VERSION 5.7 ;
  NOWIREEXTENSIONATPIN ON ;
  DIVIDERCHAR "/" ;
  BUSBITCHARS "[]" ;
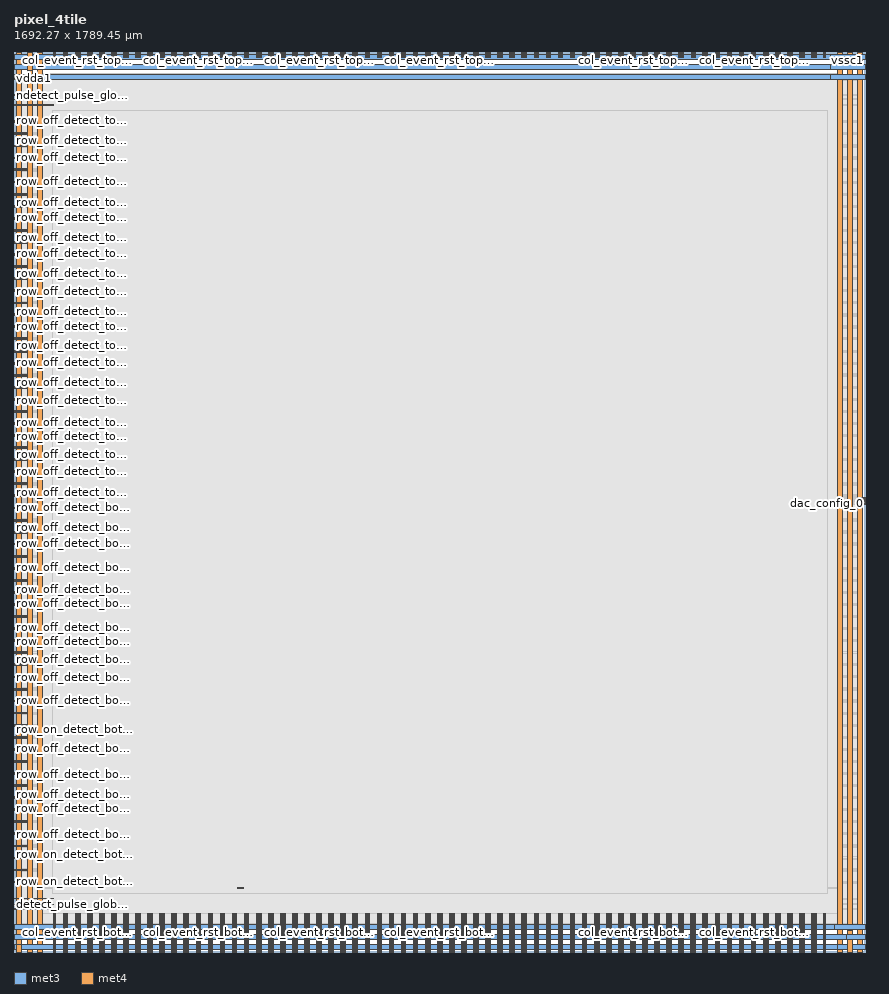
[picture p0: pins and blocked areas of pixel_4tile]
MACRO pixel_4tile
  CLASS BLOCK ;
  FOREIGN pixel_4tile ;
  ORIGIN 75.885 75.665 ;
  SIZE 1692.265 BY 1789.450 ;
  PIN vssa1
    ANTENNADIFFAREA 25319.859375 ;
    PORT
      LAYER met3 ;
        RECT 1547.800 1658.440 1616.380 1668.440 ;
    END
    PORT
      LAYER met3 ;
        RECT -75.885 1658.440 1547.800 1668.440 ;
    END
    PORT
      LAYER met3 ;
        RECT -75.885 -30.000 1555.035 -20.000 ;
    END
    PORT
      LAYER met3 ;
        RECT 1555.035 -30.000 1616.380 -20.000 ;
    END
    PORT
      LAYER met4 ;
        RECT -30.000 -75.665 -20.000 1713.785 ;
    END
    PORT
      LAYER met4 ;
        RECT 1561.380 -75.665 1571.380 1713.785 ;
    END
  END vssa1
  PIN vdda1
    PORT
      LAYER met3 ;
        RECT 1547.800 1678.440 1616.380 1688.440 ;
    END
    PORT
      LAYER met3 ;
        RECT -75.885 1678.440 1547.800 1688.440 ;
    END
    PORT
      LAYER met3 ;
        RECT -75.885 -50.000 1580.160 -40.000 ;
    END
    PORT
      LAYER met3 ;
        RECT 1580.160 -50.000 1616.380 -40.000 ;
    END
    PORT
      LAYER met4 ;
        RECT 1581.380 -33.295 1591.380 1713.785 ;
    END
    PORT
      LAYER met4 ;
        RECT -50.000 1676.075 -40.000 1713.785 ;
    END
    PORT
      LAYER met4 ;
        RECT -50.000 -75.665 -40.000 1676.075 ;
    END
    PORT
      LAYER met4 ;
        RECT 368.795 50.390 380.585 52.050 ;
    END
    PORT
      LAYER met4 ;
        RECT 1581.380 -75.665 1591.380 -33.295 ;
    END
  END vdda1
  PIN vssc1
    ANTENNADIFFAREA 4128.768066 ;
    PORT
      LAYER met3 ;
        RECT 1547.800 1697.955 1616.380 1707.955 ;
    END
    PORT
      LAYER met3 ;
        RECT -75.885 1697.955 1547.800 1707.955 ;
    END
    PORT
      LAYER met3 ;
        RECT -75.885 -70.000 1561.945 -60.000 ;
    END
    PORT
      LAYER met3 ;
        RECT 1561.945 -70.000 1616.380 -60.000 ;
    END
    PORT
      LAYER met4 ;
        RECT -70.000 -60.000 -60.000 1713.785 ;
    END
    PORT
      LAYER met4 ;
        RECT -70.000 -75.665 -60.000 -60.000 ;
    END
    PORT
      LAYER met4 ;
        RECT 1601.380 -75.665 1611.380 1713.785 ;
    END
  END vssc1
  PIN dac_config_2
    ANTENNAGATEAREA 36864.000000 ;
    PORT
      LAYER met3 ;
        RECT 1605.820 826.380 1616.380 827.380 ;
    END
  END dac_config_2
  PIN dac_config_4
    ANTENNAGATEAREA 10321.919922 ;
    PORT
      LAYER met3 ;
        RECT 1605.820 820.260 1616.380 821.260 ;
    END
  END dac_config_4
  PIN dac_config_5
    ANTENNAGATEAREA 10321.919922 ;
    PORT
      LAYER met3 ;
        RECT 1605.820 824.340 1616.380 825.340 ;
    END
  END dac_config_5
  PIN dac_config_3
    ANTENNAGATEAREA 1228.799927 ;
    PORT
      LAYER met3 ;
        RECT 1605.820 822.300 1616.380 823.300 ;
    END
  END dac_config_3
  PIN row_off_detect_top<0>
    ANTENNAGATEAREA 8.064000 ;
    PORT
      LAYER met3 ;
        RECT -75.885 1576.770 -50.260 1577.070 ;
    END
  END row_off_detect_top<0>
  PIN row_off_detect_top<11>
    ANTENNAGATEAREA 8.064000 ;
    PORT
      LAYER met3 ;
        RECT -75.885 1453.690 -50.260 1453.990 ;
    END
  END row_off_detect_top<11>
  PIN row_off_detect_top<25>
    ANTENNAGATEAREA 8.064000 ;
    PORT
      LAYER met3 ;
        RECT -75.885 1285.730 -50.260 1286.030 ;
    END
  END row_off_detect_top<25>
  PIN row_on_detect_top<19>
    ANTENNAGATEAREA 16.128000 ;
    PORT
      LAYER met3 ;
        RECT -75.885 1358.490 -50.260 1358.790 ;
    END
  END row_on_detect_top<19>
  PIN row_on_detect_top<20>
    ANTENNAGATEAREA 16.128000 ;
    PORT
      LAYER met3 ;
        RECT -75.885 1336.050 -50.260 1336.350 ;
    END
  END row_on_detect_top<20>
  PIN row_off_detect_top<12>
    ANTENNAGATEAREA 8.064000 ;
    PORT
      LAYER met3 ;
        RECT -75.885 1432.610 -50.260 1432.910 ;
    END
  END row_off_detect_top<12>
  PIN row_on_detect_top<0>
    ANTENNAGATEAREA 16.128000 ;
    PORT
      LAYER met3 ;
        RECT -75.885 1575.410 -50.260 1575.710 ;
    END
  END row_on_detect_top<0>
  PIN row_on_detect_top<1>
    ANTENNAGATEAREA 16.128000 ;
    PORT
      LAYER met3 ;
        RECT -75.885 1574.730 -50.260 1575.030 ;
    END
  END row_on_detect_top<1>
  PIN row_on_detect_top<2>
    ANTENNAGATEAREA 16.128000 ;
    PORT
      LAYER met3 ;
        RECT -75.885 1551.610 -50.260 1551.910 ;
    END
  END row_on_detect_top<2>
  PIN row_on_detect_top<23>
    ANTENNAGATEAREA 16.128000 ;
    PORT
      LAYER met3 ;
        RECT -75.885 1310.890 -50.260 1311.190 ;
    END
  END row_on_detect_top<23>
  PIN row_off_detect_top<9>
    ANTENNAGATEAREA 8.064000 ;
    PORT
      LAYER met3 ;
        RECT -75.885 1477.490 -50.260 1477.790 ;
    END
  END row_off_detect_top<9>
  PIN row_off_detect_top<10>
    ANTENNAGATEAREA 8.064000 ;
    PORT
      LAYER met3 ;
        RECT -75.885 1456.410 -50.260 1456.710 ;
    END
  END row_off_detect_top<10>
  PIN row_off_detect_top<3>
    ANTENNAGATEAREA 8.064000 ;
    PORT
      LAYER met3 ;
        RECT -75.885 1549.570 -50.260 1549.870 ;
    END
  END row_off_detect_top<3>
  PIN row_off_detect_top<4>
    ANTENNAGATEAREA 8.064000 ;
    PORT
      LAYER met3 ;
        RECT -75.885 1528.490 -50.260 1528.790 ;
    END
  END row_off_detect_top<4>
  PIN row_off_detect_top<24>
    ANTENNAGATEAREA 8.064000 ;
    PORT
      LAYER met3 ;
        RECT -75.885 1288.450 -50.260 1288.750 ;
    END
  END row_off_detect_top<24>
  PIN row_off_detect_top<21>
    ANTENNAGATEAREA 8.064000 ;
    PORT
      LAYER met3 ;
        RECT -75.885 1333.330 -50.260 1333.630 ;
    END
  END row_off_detect_top<21>
  PIN row_off_detect_top<22>
    ANTENNAGATEAREA 8.064000 ;
    PORT
      LAYER met3 ;
        RECT -75.885 1312.930 -50.260 1313.230 ;
    END
  END row_off_detect_top<22>
  PIN row_off_detect_top<17>
    ANTENNAGATEAREA 8.064000 ;
    PORT
      LAYER met3 ;
        RECT -75.885 1381.610 -50.260 1381.910 ;
    END
  END row_off_detect_top<17>
  PIN row_off_detect_top<18>
    ANTENNAGATEAREA 8.064000 ;
    PORT
      LAYER met3 ;
        RECT -75.885 1360.530 -50.260 1360.830 ;
    END
  END row_off_detect_top<18>
  PIN row_off_detect_top<16>
    ANTENNAGATEAREA 8.064000 ;
    PORT
      LAYER met3 ;
        RECT -75.885 1385.010 -50.260 1385.310 ;
    END
  END row_off_detect_top<16>
  PIN row_on_detect_top<17>
    ANTENNAGATEAREA 16.128000 ;
    PORT
      LAYER met3 ;
        RECT -75.885 1382.290 -50.260 1382.590 ;
    END
  END row_on_detect_top<17>
  PIN row_on_detect_top<18>
    ANTENNAGATEAREA 16.128000 ;
    PORT
      LAYER met3 ;
        RECT -75.885 1359.850 -50.260 1360.150 ;
    END
  END row_on_detect_top<18>
  PIN row_on_detect_top<15>
    ANTENNAGATEAREA 16.128000 ;
    PORT
      LAYER met3 ;
        RECT -75.885 1406.090 -50.260 1406.390 ;
    END
  END row_on_detect_top<15>
  PIN row_on_detect_top<25>
    ANTENNAGATEAREA 16.128000 ;
    PORT
      LAYER met3 ;
        RECT -75.885 1286.410 -50.260 1286.710 ;
    END
  END row_on_detect_top<25>
  PIN row_on_detect_top<24>
    ANTENNAGATEAREA 16.128000 ;
    PORT
      LAYER met3 ;
        RECT -75.885 1287.770 -50.260 1288.070 ;
    END
  END row_on_detect_top<24>
  PIN row_off_detect_top<19>
    ANTENNAGATEAREA 8.064000 ;
    PORT
      LAYER met3 ;
        RECT -75.885 1357.130 -50.260 1357.430 ;
    END
  END row_off_detect_top<19>
  PIN row_off_detect_top<20>
    ANTENNAGATEAREA 8.064000 ;
    PORT
      LAYER met3 ;
        RECT -75.885 1336.730 -50.260 1337.030 ;
    END
  END row_off_detect_top<20>
  PIN row_on_detect_top<13>
    ANTENNAGATEAREA 16.128000 ;
    PORT
      LAYER met3 ;
        RECT -75.885 1430.570 -50.260 1430.870 ;
    END
  END row_on_detect_top<13>
  PIN row_on_detect_top<14>
    ANTENNAGATEAREA 16.128000 ;
    PORT
      LAYER met3 ;
        RECT -75.885 1407.450 -50.260 1407.750 ;
    END
  END row_on_detect_top<14>
  PIN row_off_detect_top<23>
    ANTENNAGATEAREA 8.064000 ;
    PORT
      LAYER met3 ;
        RECT -75.885 1309.530 -50.260 1309.830 ;
    END
  END row_off_detect_top<23>
  PIN row_on_detect_top<9>
    ANTENNAGATEAREA 16.128000 ;
    PORT
      LAYER met3 ;
        RECT -75.885 1478.850 -50.260 1479.150 ;
    END
  END row_on_detect_top<9>
  PIN row_on_detect_top<10>
    ANTENNAGATEAREA 16.128000 ;
    PORT
      LAYER met3 ;
        RECT -75.885 1455.730 -50.260 1456.030 ;
    END
  END row_on_detect_top<10>
  PIN row_off_detect_top<15>
    ANTENNAGATEAREA 8.064000 ;
    PORT
      LAYER met3 ;
        RECT -75.885 1405.410 -50.260 1405.710 ;
    END
  END row_off_detect_top<15>
  PIN ndetect_pulse_global_top_left
    ANTENNAGATEAREA 64.000000 ;
    PORT
      LAYER met3 ;
        RECT -75.885 1627.075 2.710 1628.435 ;
    END
  END ndetect_pulse_global_top_left
  PIN row_on_detect_top<11>
    ANTENNAGATEAREA 16.128000 ;
    PORT
      LAYER met3 ;
        RECT -75.885 1454.370 -50.260 1454.670 ;
    END
  END row_on_detect_top<11>
  PIN row_on_detect_top<12>
    ANTENNAGATEAREA 16.128000 ;
    PORT
      LAYER met3 ;
        RECT -75.885 1431.250 -50.260 1431.550 ;
    END
  END row_on_detect_top<12>
  PIN row_on_detect_top<16>
    ANTENNAGATEAREA 16.128000 ;
    PORT
      LAYER met3 ;
        RECT -75.885 1383.650 -50.260 1383.950 ;
    END
  END row_on_detect_top<16>
  PIN row_off_detect_top<1>
    ANTENNAGATEAREA 8.064000 ;
    PORT
      LAYER met3 ;
        RECT -75.885 1573.370 -50.260 1573.670 ;
    END
  END row_off_detect_top<1>
  PIN row_off_detect_top<2>
    ANTENNAGATEAREA 8.064000 ;
    PORT
      LAYER met3 ;
        RECT -75.885 1552.970 -50.260 1553.270 ;
    END
  END row_off_detect_top<2>
  PIN row_on_detect_top<5>
    ANTENNAGATEAREA 16.128000 ;
    PORT
      LAYER met3 ;
        RECT -75.885 1526.450 -50.260 1526.750 ;
    END
  END row_on_detect_top<5>
  PIN row_on_detect_top<6>
    ANTENNAGATEAREA 16.128000 ;
    PORT
      LAYER met3 ;
        RECT -75.885 1503.330 -50.260 1503.630 ;
    END
  END row_on_detect_top<6>
  PIN row_off_detect_top<5>
    ANTENNAGATEAREA 8.064000 ;
    PORT
      LAYER met3 ;
        RECT -75.885 1525.090 -50.260 1525.390 ;
    END
  END row_off_detect_top<5>
  PIN row_off_detect_top<6>
    ANTENNAGATEAREA 8.064000 ;
    PORT
      LAYER met3 ;
        RECT -75.885 1504.690 -50.260 1504.990 ;
    END
  END row_off_detect_top<6>
  PIN row_off_detect_top<7>
    ANTENNAGATEAREA 8.064000 ;
    PORT
      LAYER met3 ;
        RECT -75.885 1501.290 -50.260 1501.590 ;
    END
  END row_off_detect_top<7>
  PIN row_off_detect_top<8>
    ANTENNAGATEAREA 8.064000 ;
    PORT
      LAYER met3 ;
        RECT -75.885 1480.890 -50.260 1481.190 ;
    END
  END row_off_detect_top<8>
  PIN row_off_detect_top<13>
    ANTENNAGATEAREA 8.064000 ;
    PORT
      LAYER met3 ;
        RECT -75.885 1429.210 -50.260 1429.510 ;
    END
  END row_off_detect_top<13>
  PIN row_off_detect_top<14>
    ANTENNAGATEAREA 8.064000 ;
    PORT
      LAYER met3 ;
        RECT -75.885 1408.810 -50.260 1409.110 ;
    END
  END row_off_detect_top<14>
  PIN row_on_detect_top<7>
    ANTENNAGATEAREA 16.128000 ;
    PORT
      LAYER met3 ;
        RECT -75.885 1502.650 -50.260 1502.950 ;
    END
  END row_on_detect_top<7>
  PIN row_on_detect_top<8>
    ANTENNAGATEAREA 16.128000 ;
    PORT
      LAYER met3 ;
        RECT -75.885 1479.530 -50.260 1479.830 ;
    END
  END row_on_detect_top<8>
  PIN row_on_detect_top<26>
    ANTENNAGATEAREA 16.128000 ;
    PORT
      LAYER met3 ;
        RECT -75.885 1263.290 -50.260 1263.590 ;
    END
  END row_on_detect_top<26>
  PIN row_off_detect_top<26>
    ANTENNAGATEAREA 8.064000 ;
    PORT
      LAYER met3 ;
        RECT -75.885 1264.650 -50.260 1264.950 ;
    END
  END row_off_detect_top<26>
  PIN row_on_detect_top<27>
    ANTENNAGATEAREA 16.128000 ;
    PORT
      LAYER met3 ;
        RECT -75.885 1262.610 -50.260 1262.910 ;
    END
  END row_on_detect_top<27>
  PIN row_on_detect_top<21>
    ANTENNAGATEAREA 16.128000 ;
    PORT
      LAYER met3 ;
        RECT -75.885 1334.690 -50.260 1334.990 ;
    END
  END row_on_detect_top<21>
  PIN row_on_detect_top<22>
    ANTENNAGATEAREA 16.128000 ;
    PORT
      LAYER met3 ;
        RECT -75.885 1311.570 -50.260 1311.870 ;
    END
  END row_on_detect_top<22>
  PIN pre_charge_global_top_left
    ANTENNAGATEAREA 1024.000000 ;
    PORT
      LAYER met3 ;
        RECT -75.885 1607.355 2.710 1608.715 ;
    END
  END pre_charge_global_top_left
  PIN row_on_detect_top<3>
    ANTENNAGATEAREA 16.128000 ;
    PORT
      LAYER met3 ;
        RECT -75.885 1550.930 -50.260 1551.230 ;
    END
  END row_on_detect_top<3>
  PIN row_on_detect_top<4>
    ANTENNAGATEAREA 16.128000 ;
    PORT
      LAYER met3 ;
        RECT -75.885 1527.810 -50.260 1528.110 ;
    END
  END row_on_detect_top<4>
  PIN detect_pulse_global_top_left
    ANTENNAGATEAREA 147.199997 ;
    PORT
      LAYER met3 ;
        RECT -75.885 1618.905 2.710 1620.305 ;
    END
  END detect_pulse_global_top_left
  PIN row_off_detect_top<27>
    ANTENNAGATEAREA 8.064000 ;
    PORT
      LAYER met3 ;
        RECT -75.885 1261.250 -50.260 1261.550 ;
    END
  END row_off_detect_top<27>
  PIN row_on_detect_top<39>
    ANTENNAGATEAREA 16.128000 ;
    PORT
      LAYER met3 ;
        RECT -75.885 1118.450 -50.260 1118.750 ;
    END
  END row_on_detect_top<39>
  PIN row_off_detect_top<48>
    ANTENNAGATEAREA 8.064000 ;
    PORT
      LAYER met3 ;
        RECT -75.885 1000.810 -50.260 1001.110 ;
    END
  END row_off_detect_top<48>
  PIN row_on_detect_top<58>
    ANTENNAGATEAREA 16.128000 ;
    PORT
      LAYER met3 ;
        RECT -75.885 879.770 -50.260 880.070 ;
    END
  END row_on_detect_top<58>
  PIN row_off_detect_top<49>
    ANTENNAGATEAREA 8.064000 ;
    PORT
      LAYER met3 ;
        RECT -75.885 997.410 -50.260 997.710 ;
    END
  END row_off_detect_top<49>
  PIN row_off_detect_top<50>
    ANTENNAGATEAREA 8.064000 ;
    PORT
      LAYER met3 ;
        RECT -75.885 977.010 -50.260 977.310 ;
    END
  END row_off_detect_top<50>
  PIN row_on_detect_top<37>
    ANTENNAGATEAREA 16.128000 ;
    PORT
      LAYER met3 ;
        RECT -75.885 1142.930 -50.260 1143.230 ;
    END
  END row_on_detect_top<37>
  PIN row_on_detect_top<38>
    ANTENNAGATEAREA 16.128000 ;
    PORT
      LAYER met3 ;
        RECT -75.885 1119.810 -50.260 1120.110 ;
    END
  END row_on_detect_top<38>
  PIN row_on_detect_top<34>
    ANTENNAGATEAREA 16.128000 ;
    PORT
      LAYER met3 ;
        RECT -75.885 1167.410 -50.260 1167.710 ;
    END
  END row_on_detect_top<34>
  PIN row_on_detect_top<28>
    ANTENNAGATEAREA 16.128000 ;
    PORT
      LAYER met3 ;
        RECT -75.885 1239.490 -50.260 1239.790 ;
    END
  END row_on_detect_top<28>
  PIN row_off_detect_top<58>
    ANTENNAGATEAREA 8.064000 ;
    PORT
      LAYER met3 ;
        RECT -75.885 880.450 -50.260 880.750 ;
    END
  END row_off_detect_top<58>
  PIN row_off_detect_top<59>
    ANTENNAGATEAREA 8.064000 ;
    PORT
      LAYER met3 ;
        RECT -75.885 877.730 -50.260 878.030 ;
    END
  END row_off_detect_top<59>
  PIN row_off_detect_top<38>
    ANTENNAGATEAREA 8.064000 ;
    PORT
      LAYER met3 ;
        RECT -75.885 1120.490 -50.260 1120.790 ;
    END
  END row_off_detect_top<38>
  PIN row_on_detect_top<48>
    ANTENNAGATEAREA 16.128000 ;
    PORT
      LAYER met3 ;
        RECT -75.885 999.450 -50.260 999.750 ;
    END
  END row_on_detect_top<48>
  PIN row_on_detect_top<59>
    ANTENNAGATEAREA 16.128000 ;
    PORT
      LAYER met3 ;
        RECT -75.885 878.410 -50.260 878.710 ;
    END
  END row_on_detect_top<59>
  PIN row_on_detect_top<60>
    ANTENNAGATEAREA 16.128000 ;
    PORT
      LAYER met3 ;
        RECT -75.885 855.290 -50.260 855.590 ;
    END
  END row_on_detect_top<60>
  PIN row_off_detect_top<62>
    ANTENNAGATEAREA 8.064000 ;
    PORT
      LAYER met3 ;
        RECT -75.885 832.850 -50.260 833.150 ;
    END
  END row_off_detect_top<62>
  PIN row_off_detect_top<34>
    ANTENNAGATEAREA 8.064000 ;
    PORT
      LAYER met3 ;
        RECT -75.885 1168.770 -50.260 1169.070 ;
    END
  END row_off_detect_top<34>
  PIN row_off_detect_top<53>
    ANTENNAGATEAREA 8.064000 ;
    PORT
      LAYER met3 ;
        RECT -75.885 949.130 -50.260 949.430 ;
    END
  END row_off_detect_top<53>
  PIN row_off_detect_top<54>
    ANTENNAGATEAREA 8.064000 ;
    PORT
      LAYER met3 ;
        RECT -75.885 928.730 -50.260 929.030 ;
    END
  END row_off_detect_top<54>
  PIN row_off_detect_top<36>
    ANTENNAGATEAREA 8.064000 ;
    PORT
      LAYER met3 ;
        RECT -75.885 1144.970 -50.260 1145.270 ;
    END
  END row_off_detect_top<36>
  PIN row_off_detect_top<60>
    ANTENNAGATEAREA 8.064000 ;
    PORT
      LAYER met3 ;
        RECT -75.885 856.650 -50.260 856.950 ;
    END
  END row_off_detect_top<60>
  PIN row_off_detect_top<44>
    ANTENNAGATEAREA 8.064000 ;
    PORT
      LAYER met3 ;
        RECT -75.885 1048.410 -50.260 1048.710 ;
    END
  END row_off_detect_top<44>
  PIN row_off_detect_top<31>
    ANTENNAGATEAREA 8.064000 ;
    PORT
      LAYER met3 ;
        RECT -75.885 1213.650 -50.260 1213.950 ;
    END
  END row_off_detect_top<31>
  PIN row_off_detect_top<52>
    ANTENNAGATEAREA 8.064000 ;
    PORT
      LAYER met3 ;
        RECT -75.885 952.530 -50.260 952.830 ;
    END
  END row_off_detect_top<52>
  PIN row_on_detect_top<63>
    ANTENNAGATEAREA 16.128000 ;
    PORT
      LAYER met3 ;
        RECT -75.885 830.810 -50.260 831.110 ;
    END
  END row_on_detect_top<63>
  PIN row_off_detect_top<29>
    ANTENNAGATEAREA 8.064000 ;
    PORT
      LAYER met3 ;
        RECT -75.885 1237.450 -50.260 1237.750 ;
    END
  END row_off_detect_top<29>
  PIN row_on_detect_top<42>
    ANTENNAGATEAREA 16.128000 ;
    PORT
      LAYER met3 ;
        RECT -75.885 1071.530 -50.260 1071.830 ;
    END
  END row_on_detect_top<42>
  PIN row_off_detect_top<32>
    ANTENNAGATEAREA 8.064000 ;
    PORT
      LAYER met3 ;
        RECT -75.885 1192.570 -50.260 1192.870 ;
    END
  END row_off_detect_top<32>
  PIN row_off_detect_top<40>
    ANTENNAGATEAREA 8.064000 ;
    PORT
      LAYER met3 ;
        RECT -75.885 1096.690 -50.260 1096.990 ;
    END
  END row_off_detect_top<40>
  PIN row_on_detect_top<57>
    ANTENNAGATEAREA 16.128000 ;
    PORT
      LAYER met3 ;
        RECT -75.885 902.890 -50.260 903.190 ;
    END
  END row_on_detect_top<57>
  PIN row_on_detect_top<56>
    ANTENNAGATEAREA 16.128000 ;
    PORT
      LAYER met3 ;
        RECT -75.885 903.570 -50.260 903.870 ;
    END
  END row_on_detect_top<56>
  PIN row_on_detect_top<40>
    ANTENNAGATEAREA 16.128000 ;
    PORT
      LAYER met3 ;
        RECT -75.885 1095.330 -50.260 1095.630 ;
    END
  END row_on_detect_top<40>
  PIN row_off_detect_top<41>
    ANTENNAGATEAREA 8.064000 ;
    PORT
      LAYER met3 ;
        RECT -75.885 1093.290 -50.260 1093.590 ;
    END
  END row_off_detect_top<41>
  PIN row_on_detect_top<35>
    ANTENNAGATEAREA 16.128000 ;
    PORT
      LAYER met3 ;
        RECT -75.885 1166.730 -50.260 1167.030 ;
    END
  END row_on_detect_top<35>
  PIN row_on_detect_top<36>
    ANTENNAGATEAREA 16.128000 ;
    PORT
      LAYER met3 ;
        RECT -75.885 1143.610 -50.260 1143.910 ;
    END
  END row_on_detect_top<36>
  PIN row_off_detect_top<42>
    ANTENNAGATEAREA 8.064000 ;
    PORT
      LAYER met3 ;
        RECT -75.885 1072.890 -50.260 1073.190 ;
    END
  END row_off_detect_top<42>
  PIN row_off_detect_top<47>
    ANTENNAGATEAREA 8.064000 ;
    PORT
      LAYER met3 ;
        RECT -75.885 1021.210 -50.260 1021.510 ;
    END
  END row_off_detect_top<47>
  PIN row_on_detect_top<33>
    ANTENNAGATEAREA 16.128000 ;
    PORT
      LAYER met3 ;
        RECT -75.885 1190.530 -50.260 1190.830 ;
    END
  END row_on_detect_top<33>
  PIN row_on_detect_top<31>
    ANTENNAGATEAREA 16.128000 ;
    PORT
      LAYER met3 ;
        RECT -75.885 1214.330 -50.260 1214.630 ;
    END
  END row_on_detect_top<31>
  PIN row_on_detect_top<32>
    ANTENNAGATEAREA 16.128000 ;
    PORT
      LAYER met3 ;
        RECT -75.885 1191.210 -50.260 1191.510 ;
    END
  END row_on_detect_top<32>
  PIN row_off_detect_top<57>
    ANTENNAGATEAREA 8.064000 ;
    PORT
      LAYER met3 ;
        RECT -75.885 901.530 -50.260 901.830 ;
    END
  END row_off_detect_top<57>
  PIN row_on_detect_top<47>
    ANTENNAGATEAREA 16.128000 ;
    PORT
      LAYER met3 ;
        RECT -75.885 1022.570 -50.260 1022.870 ;
    END
  END row_on_detect_top<47>
  PIN row_on_detect_top<43>
    ANTENNAGATEAREA 16.128000 ;
    PORT
      LAYER met3 ;
        RECT -75.885 1070.850 -50.260 1071.150 ;
    END
  END row_on_detect_top<43>
  PIN row_off_detect_top<55>
    ANTENNAGATEAREA 8.064000 ;
    PORT
      LAYER met3 ;
        RECT -75.885 925.330 -50.260 925.630 ;
    END
  END row_off_detect_top<55>
  PIN row_off_detect_top<56>
    ANTENNAGATEAREA 8.064000 ;
    PORT
      LAYER met3 ;
        RECT -75.885 904.930 -50.260 905.230 ;
    END
  END row_off_detect_top<56>
  PIN row_off_detect_top<61>
    ANTENNAGATEAREA 8.064000 ;
    PORT
      LAYER met3 ;
        RECT -75.885 853.250 -50.260 853.550 ;
    END
  END row_off_detect_top<61>
  PIN row_on_detect_top<49>
    ANTENNAGATEAREA 16.128000 ;
    PORT
      LAYER met3 ;
        RECT -75.885 998.090 -50.260 998.390 ;
    END
  END row_on_detect_top<49>
  PIN row_on_detect_top<50>
    ANTENNAGATEAREA 16.128000 ;
    PORT
      LAYER met3 ;
        RECT -75.885 975.650 -50.260 975.950 ;
    END
  END row_on_detect_top<50>
  PIN row_on_detect_top<53>
    ANTENNAGATEAREA 16.128000 ;
    PORT
      LAYER met3 ;
        RECT -75.885 950.490 -50.260 950.790 ;
    END
  END row_on_detect_top<53>
  PIN row_on_detect_top<54>
    ANTENNAGATEAREA 16.128000 ;
    PORT
      LAYER met3 ;
        RECT -75.885 928.050 -50.260 928.350 ;
    END
  END row_on_detect_top<54>
  PIN row_off_detect_top<43>
    ANTENNAGATEAREA 8.064000 ;
    PORT
      LAYER met3 ;
        RECT -75.885 1069.490 -50.260 1069.790 ;
    END
  END row_off_detect_top<43>
  PIN row_off_detect_top<33>
    ANTENNAGATEAREA 8.064000 ;
    PORT
      LAYER met3 ;
        RECT -75.885 1189.170 -50.260 1189.470 ;
    END
  END row_off_detect_top<33>
  PIN row_off_detect_top<35>
    ANTENNAGATEAREA 8.064000 ;
    PORT
      LAYER met3 ;
        RECT -75.885 1165.370 -50.260 1165.670 ;
    END
  END row_off_detect_top<35>
  PIN row_off_detect_top<37>
    ANTENNAGATEAREA 8.064000 ;
    PORT
      LAYER met3 ;
        RECT -75.885 1141.570 -50.260 1141.870 ;
    END
  END row_off_detect_top<37>
  PIN row_off_detect_top<45>
    ANTENNAGATEAREA 8.064000 ;
    PORT
      LAYER met3 ;
        RECT -75.885 1045.690 -50.260 1045.990 ;
    END
  END row_off_detect_top<45>
  PIN row_off_detect_top<46>
    ANTENNAGATEAREA 8.064000 ;
    PORT
      LAYER met3 ;
        RECT -75.885 1024.610 -50.260 1024.910 ;
    END
  END row_off_detect_top<46>
  PIN row_on_detect_top<45>
    ANTENNAGATEAREA 16.128000 ;
    PORT
      LAYER met3 ;
        RECT -75.885 1046.370 -50.260 1046.670 ;
    END
  END row_on_detect_top<45>
  PIN row_on_detect_top<46>
    ANTENNAGATEAREA 16.128000 ;
    PORT
      LAYER met3 ;
        RECT -75.885 1023.250 -50.260 1023.550 ;
    END
  END row_on_detect_top<46>
  PIN row_off_detect_top<63>
    ANTENNAGATEAREA 8.064000 ;
    PORT
      LAYER met3 ;
        RECT -75.885 829.450 -50.260 829.750 ;
    END
  END row_off_detect_top<63>
  PIN row_off_detect_top<39>
    ANTENNAGATEAREA 8.064000 ;
    PORT
      LAYER met3 ;
        RECT -75.885 1117.090 -50.260 1117.390 ;
    END
  END row_off_detect_top<39>
  PIN row_off_detect_top<28>
    ANTENNAGATEAREA 8.064000 ;
    PORT
      LAYER met3 ;
        RECT -75.885 1240.850 -50.260 1241.150 ;
    END
  END row_off_detect_top<28>
  PIN row_on_detect_top<61>
    ANTENNAGATEAREA 16.128000 ;
    PORT
      LAYER met3 ;
        RECT -75.885 854.610 -50.260 854.910 ;
    END
  END row_on_detect_top<61>
  PIN row_on_detect_top<62>
    ANTENNAGATEAREA 16.128000 ;
    PORT
      LAYER met3 ;
        RECT -75.885 831.490 -50.260 831.790 ;
    END
  END row_on_detect_top<62>
  PIN row_on_detect_top<29>
    ANTENNAGATEAREA 16.128000 ;
    PORT
      LAYER met3 ;
        RECT -75.885 1238.810 -50.260 1239.110 ;
    END
  END row_on_detect_top<29>
  PIN row_on_detect_top<30>
    ANTENNAGATEAREA 16.128000 ;
    PORT
      LAYER met3 ;
        RECT -75.885 1215.690 -50.260 1215.990 ;
    END
  END row_on_detect_top<30>
  PIN row_off_detect_top<51>
    ANTENNAGATEAREA 8.064000 ;
    PORT
      LAYER met3 ;
        RECT -75.885 973.610 -50.260 973.910 ;
    END
  END row_off_detect_top<51>
  PIN row_on_detect_top<51>
    ANTENNAGATEAREA 16.128000 ;
    PORT
      LAYER met3 ;
        RECT -75.885 974.290 -50.260 974.590 ;
    END
  END row_on_detect_top<51>
  PIN row_on_detect_top<52>
    ANTENNAGATEAREA 16.128000 ;
    PORT
      LAYER met3 ;
        RECT -75.885 951.850 -50.260 952.150 ;
    END
  END row_on_detect_top<52>
  PIN row_off_detect_top<30>
    ANTENNAGATEAREA 8.064000 ;
    PORT
      LAYER met3 ;
        RECT -75.885 1216.370 -50.260 1216.670 ;
    END
  END row_off_detect_top<30>
  PIN row_on_detect_top<41>
    ANTENNAGATEAREA 16.128000 ;
    PORT
      LAYER met3 ;
        RECT -75.885 1094.650 -50.260 1094.950 ;
    END
  END row_on_detect_top<41>
  PIN row_on_detect_top<55>
    ANTENNAGATEAREA 16.128000 ;
    PORT
      LAYER met3 ;
        RECT -75.885 926.690 -50.260 926.990 ;
    END
  END row_on_detect_top<55>
  PIN row_on_detect_top<44>
    ANTENNAGATEAREA 16.128000 ;
    PORT
      LAYER met3 ;
        RECT -75.885 1047.730 -50.260 1048.030 ;
    END
  END row_on_detect_top<44>
  PIN row_on_detect_bot<3>
    ANTENNAGATEAREA 16.128000 ;
    PORT
      LAYER met3 ;
        RECT -75.885 782.530 -50.260 782.830 ;
    END
  END row_on_detect_bot<3>
  PIN row_on_detect_bot<4>
    ANTENNAGATEAREA 16.128000 ;
    PORT
      LAYER met3 ;
        RECT -75.885 759.410 -50.260 759.710 ;
    END
  END row_on_detect_bot<4>
  PIN row_off_detect_bot<29>
    ANTENNAGATEAREA 8.064000 ;
    PORT
      LAYER met3 ;
        RECT -75.885 469.730 -50.260 470.030 ;
    END
  END row_off_detect_bot<29>
  PIN row_off_detect_bot<28>
    ANTENNAGATEAREA 8.064000 ;
    PORT
      LAYER met3 ;
        RECT -75.885 472.450 -50.260 472.750 ;
    END
  END row_off_detect_bot<28>
  PIN row_on_detect_bot<2>
    ANTENNAGATEAREA 16.128000 ;
    PORT
      LAYER met3 ;
        RECT -75.885 783.210 -50.260 783.510 ;
    END
  END row_on_detect_bot<2>
  PIN row_on_detect_bot<28>
    ANTENNAGATEAREA 16.128000 ;
    PORT
      LAYER met3 ;
        RECT -75.885 471.770 -50.260 472.070 ;
    END
  END row_on_detect_bot<28>
  PIN row_off_detect_bot<34>
    ANTENNAGATEAREA 8.064000 ;
    PORT
      LAYER met3 ;
        RECT -75.885 400.370 -50.260 400.670 ;
    END
  END row_off_detect_bot<34>
  PIN row_off_detect_bot<35>
    ANTENNAGATEAREA 8.064000 ;
    PORT
      LAYER met3 ;
        RECT -75.885 397.650 -50.260 397.950 ;
    END
  END row_off_detect_bot<35>
  PIN row_on_detect_bot<26>
    ANTENNAGATEAREA 16.128000 ;
    PORT
      LAYER met3 ;
        RECT -75.885 495.570 -50.260 495.870 ;
    END
  END row_on_detect_bot<26>
  PIN row_on_detect_bot<21>
    ANTENNAGATEAREA 16.128000 ;
    PORT
      LAYER met3 ;
        RECT -75.885 566.290 -50.260 566.590 ;
    END
  END row_on_detect_bot<21>
  PIN row_on_detect_bot<29>
    ANTENNAGATEAREA 16.128000 ;
    PORT
      LAYER met3 ;
        RECT -75.885 470.410 -50.260 470.710 ;
    END
  END row_on_detect_bot<29>
  PIN row_on_detect_bot<27>
    ANTENNAGATEAREA 16.128000 ;
    PORT
      LAYER met3 ;
        RECT -75.885 494.890 -50.260 495.190 ;
    END
  END row_on_detect_bot<27>
  PIN row_on_detect_bot<30>
    ANTENNAGATEAREA 16.128000 ;
    PORT
      LAYER met3 ;
        RECT -75.885 447.290 -50.260 447.590 ;
    END
  END row_on_detect_bot<30>
  PIN row_on_detect_bot<20>
    ANTENNAGATEAREA 16.128000 ;
    PORT
      LAYER met3 ;
        RECT -75.885 567.650 -50.260 567.950 ;
    END
  END row_on_detect_bot<20>
  PIN row_on_detect_bot<12>
    ANTENNAGATEAREA 16.128000 ;
    PORT
      LAYER met3 ;
        RECT -75.885 663.530 -50.260 663.830 ;
    END
  END row_on_detect_bot<12>
  PIN row_off_detect_bot<0>
    ANTENNAGATEAREA 8.064000 ;
    PORT
      LAYER met3 ;
        RECT -75.885 808.370 -50.260 808.670 ;
    END
  END row_off_detect_bot<0>
  PIN row_off_detect_bot<23>
    ANTENNAGATEAREA 8.064000 ;
    PORT
      LAYER met3 ;
        RECT -75.885 541.130 -50.260 541.430 ;
    END
  END row_off_detect_bot<23>
  PIN row_off_detect_bot<22>
    ANTENNAGATEAREA 8.064000 ;
    PORT
      LAYER met3 ;
        RECT -75.885 544.530 -50.260 544.830 ;
    END
  END row_off_detect_bot<22>
  PIN row_off_detect_bot<16>
    ANTENNAGATEAREA 8.064000 ;
    PORT
      LAYER met3 ;
        RECT -75.885 616.610 -50.260 616.910 ;
    END
  END row_off_detect_bot<16>
  PIN row_off_detect_bot<30>
    ANTENNAGATEAREA 8.064000 ;
    PORT
      LAYER met3 ;
        RECT -75.885 448.650 -50.260 448.950 ;
    END
  END row_off_detect_bot<30>
  PIN row_off_detect_bot<13>
    ANTENNAGATEAREA 8.064000 ;
    PORT
      LAYER met3 ;
        RECT -75.885 661.490 -50.260 661.790 ;
    END
  END row_off_detect_bot<13>
  PIN row_off_detect_bot<7>
    ANTENNAGATEAREA 8.064000 ;
    PORT
      LAYER met3 ;
        RECT -75.885 733.570 -50.260 733.870 ;
    END
  END row_off_detect_bot<7>
  PIN row_on_detect_bot<17>
    ANTENNAGATEAREA 16.128000 ;
    PORT
      LAYER met3 ;
        RECT -75.885 614.570 -50.260 614.870 ;
    END
  END row_on_detect_bot<17>
  PIN row_on_detect_bot<18>
    ANTENNAGATEAREA 16.128000 ;
    PORT
      LAYER met3 ;
        RECT -75.885 591.450 -50.260 591.750 ;
    END
  END row_on_detect_bot<18>
  PIN row_on_detect_bot<19>
    ANTENNAGATEAREA 16.128000 ;
    PORT
      LAYER met3 ;
        RECT -75.885 590.090 -50.260 590.390 ;
    END
  END row_on_detect_bot<19>
  PIN row_on_detect_bot<32>
    ANTENNAGATEAREA 16.128000 ;
    PORT
      LAYER met3 ;
        RECT -75.885 423.490 -50.260 423.790 ;
    END
  END row_on_detect_bot<32>
  PIN row_on_detect_bot<1>
    ANTENNAGATEAREA 16.128000 ;
    PORT
      LAYER met3 ;
        RECT -75.885 806.330 -50.260 806.630 ;
    END
  END row_on_detect_bot<1>
  PIN row_off_detect_bot<1>
    ANTENNAGATEAREA 8.064000 ;
    PORT
      LAYER met3 ;
        RECT -75.885 805.650 -50.260 805.950 ;
    END
  END row_off_detect_bot<1>
  PIN row_on_detect_bot<34>
    ANTENNAGATEAREA 16.128000 ;
    PORT
      LAYER met3 ;
        RECT -75.885 399.690 -50.260 399.990 ;
    END
  END row_on_detect_bot<34>
  PIN row_on_detect_bot<13>
    ANTENNAGATEAREA 16.128000 ;
    PORT
      LAYER met3 ;
        RECT -75.885 662.850 -50.260 663.150 ;
    END
  END row_on_detect_bot<13>
  PIN row_on_detect_bot<14>
    ANTENNAGATEAREA 16.128000 ;
    PORT
      LAYER met3 ;
        RECT -75.885 639.730 -50.260 640.030 ;
    END
  END row_on_detect_bot<14>
  PIN row_off_detect_bot<25>
    ANTENNAGATEAREA 8.064000 ;
    PORT
      LAYER met3 ;
        RECT -75.885 517.330 -50.260 517.630 ;
    END
  END row_off_detect_bot<25>
  PIN row_off_detect_bot<24>
    ANTENNAGATEAREA 8.064000 ;
    PORT
      LAYER met3 ;
        RECT -75.885 520.730 -50.260 521.030 ;
    END
  END row_off_detect_bot<24>
  PIN row_off_detect_bot<19>
    ANTENNAGATEAREA 8.064000 ;
    PORT
      LAYER met3 ;
        RECT -75.885 589.410 -50.260 589.710 ;
    END
  END row_off_detect_bot<19>
  PIN row_off_detect_bot<18>
    ANTENNAGATEAREA 8.064000 ;
    PORT
      LAYER met3 ;
        RECT -75.885 592.810 -50.260 593.110 ;
    END
  END row_off_detect_bot<18>
  PIN row_off_detect_bot<15>
    ANTENNAGATEAREA 8.064000 ;
    PORT
      LAYER met3 ;
        RECT -75.885 637.690 -50.260 637.990 ;
    END
  END row_off_detect_bot<15>
  PIN row_off_detect_bot<14>
    ANTENNAGATEAREA 8.064000 ;
    PORT
      LAYER met3 ;
        RECT -75.885 640.410 -50.260 640.710 ;
    END
  END row_off_detect_bot<14>
  PIN row_off_detect_bot<9>
    ANTENNAGATEAREA 8.064000 ;
    PORT
      LAYER met3 ;
        RECT -75.885 709.090 -50.260 709.390 ;
    END
  END row_off_detect_bot<9>
  PIN row_off_detect_bot<8>
    ANTENNAGATEAREA 8.064000 ;
    PORT
      LAYER met3 ;
        RECT -75.885 712.490 -50.260 712.790 ;
    END
  END row_off_detect_bot<8>
  PIN row_on_detect_bot<15>
    ANTENNAGATEAREA 16.128000 ;
    PORT
      LAYER met3 ;
        RECT -75.885 638.370 -50.260 638.670 ;
    END
  END row_on_detect_bot<15>
  PIN row_on_detect_bot<16>
    ANTENNAGATEAREA 16.128000 ;
    PORT
      LAYER met3 ;
        RECT -75.885 615.250 -50.260 615.550 ;
    END
  END row_on_detect_bot<16>
  PIN row_on_detect_bot<31>
    ANTENNAGATEAREA 16.128000 ;
    PORT
      LAYER met3 ;
        RECT -75.885 446.610 -50.260 446.910 ;
    END
  END row_on_detect_bot<31>
  PIN row_on_detect_bot<33>
    ANTENNAGATEAREA 16.128000 ;
    PORT
      LAYER met3 ;
        RECT -75.885 422.810 -50.260 423.110 ;
    END
  END row_on_detect_bot<33>
  PIN row_on_detect_bot<35>
    ANTENNAGATEAREA 16.128000 ;
    PORT
      LAYER met3 ;
        RECT -75.885 398.330 -50.260 398.630 ;
    END
  END row_on_detect_bot<35>
  PIN row_on_detect_bot<25>
    ANTENNAGATEAREA 16.128000 ;
    PORT
      LAYER met3 ;
        RECT -75.885 518.690 -50.260 518.990 ;
    END
  END row_on_detect_bot<25>
  PIN row_on_detect_bot<5>
    ANTENNAGATEAREA 16.128000 ;
    PORT
      LAYER met3 ;
        RECT -75.885 758.730 -50.260 759.030 ;
    END
  END row_on_detect_bot<5>
  PIN row_on_detect_bot<6>
    ANTENNAGATEAREA 16.128000 ;
    PORT
      LAYER met3 ;
        RECT -75.885 735.610 -50.260 735.910 ;
    END
  END row_on_detect_bot<6>
  PIN row_off_detect_bot<32>
    ANTENNAGATEAREA 8.064000 ;
    PORT
      LAYER met3 ;
        RECT -75.885 424.850 -50.260 425.150 ;
    END
  END row_off_detect_bot<32>
  PIN row_off_detect_bot<33>
    ANTENNAGATEAREA 8.064000 ;
    PORT
      LAYER met3 ;
        RECT -75.885 421.450 -50.260 421.750 ;
    END
  END row_off_detect_bot<33>
  PIN row_on_detect_bot<11>
    ANTENNAGATEAREA 16.128000 ;
    PORT
      LAYER met3 ;
        RECT -75.885 686.650 -50.260 686.950 ;
    END
  END row_on_detect_bot<11>
  PIN row_on_detect_bot<23>
    ANTENNAGATEAREA 16.128000 ;
    PORT
      LAYER met3 ;
        RECT -75.885 542.490 -50.260 542.790 ;
    END
  END row_on_detect_bot<23>
  PIN row_on_detect_bot<24>
    ANTENNAGATEAREA 16.128000 ;
    PORT
      LAYER met3 ;
        RECT -75.885 519.730 -50.260 520.350 ;
    END
  END row_on_detect_bot<24>
  PIN row_off_detect_bot<2>
    ANTENNAGATEAREA 8.064000 ;
    PORT
      LAYER met3 ;
        RECT -75.885 784.570 -50.260 784.870 ;
    END
  END row_off_detect_bot<2>
  PIN row_off_detect_bot<3>
    ANTENNAGATEAREA 8.064000 ;
    PORT
      LAYER met3 ;
        RECT -75.885 781.170 -50.260 781.470 ;
    END
  END row_off_detect_bot<3>
  PIN row_off_detect_bot<4>
    ANTENNAGATEAREA 8.064000 ;
    PORT
      LAYER met3 ;
        RECT -75.885 760.770 -50.260 761.070 ;
    END
  END row_off_detect_bot<4>
  PIN row_off_detect_bot<21>
    ANTENNAGATEAREA 8.064000 ;
    PORT
      LAYER met3 ;
        RECT -75.885 565.610 -50.260 565.910 ;
    END
  END row_off_detect_bot<21>
  PIN row_on_detect_bot<0>
    ANTENNAGATEAREA 16.128000 ;
    PORT
      LAYER met3 ;
        RECT -75.885 807.690 -50.260 807.990 ;
    END
  END row_on_detect_bot<0>
  PIN row_off_detect_bot<20>
    ANTENNAGATEAREA 8.064000 ;
    PORT
      LAYER met3 ;
        RECT -75.885 569.010 -50.260 569.310 ;
    END
  END row_off_detect_bot<20>
  PIN row_off_detect_bot<17>
    ANTENNAGATEAREA 8.064000 ;
    PORT
      LAYER met3 ;
        RECT -75.885 613.210 -50.260 613.510 ;
    END
  END row_off_detect_bot<17>
  PIN row_off_detect_bot<12>
    ANTENNAGATEAREA 8.064000 ;
    PORT
      LAYER met3 ;
        RECT -75.885 664.890 -50.260 665.190 ;
    END
  END row_off_detect_bot<12>
  PIN row_off_detect_bot<11>
    ANTENNAGATEAREA 8.064000 ;
    PORT
      LAYER met3 ;
        RECT -75.885 685.290 -50.260 685.590 ;
    END
  END row_off_detect_bot<11>
  PIN row_off_detect_bot<10>
    ANTENNAGATEAREA 8.064000 ;
    PORT
      LAYER met3 ;
        RECT -75.885 688.690 -50.260 688.990 ;
    END
  END row_off_detect_bot<10>
  PIN row_off_detect_bot<6>
    ANTENNAGATEAREA 8.064000 ;
    PORT
      LAYER met3 ;
        RECT -75.885 736.970 -50.260 737.270 ;
    END
  END row_off_detect_bot<6>
  PIN row_off_detect_bot<27>
    ANTENNAGATEAREA 8.064000 ;
    PORT
      LAYER met3 ;
        RECT -75.885 493.530 -50.260 493.830 ;
    END
  END row_off_detect_bot<27>
  PIN row_off_detect_bot<31>
    ANTENNAGATEAREA 8.064000 ;
    PORT
      LAYER met3 ;
        RECT -75.885 445.250 -50.260 445.550 ;
    END
  END row_off_detect_bot<31>
  PIN row_off_detect_bot<5>
    ANTENNAGATEAREA 8.064000 ;
    PORT
      LAYER met3 ;
        RECT -75.885 757.370 -50.260 757.670 ;
    END
  END row_off_detect_bot<5>
  PIN row_on_detect_bot<9>
    ANTENNAGATEAREA 16.128000 ;
    PORT
      LAYER met3 ;
        RECT -75.885 710.450 -50.260 710.750 ;
    END
  END row_on_detect_bot<9>
  PIN row_on_detect_bot<10>
    ANTENNAGATEAREA 16.128000 ;
    PORT
      LAYER met3 ;
        RECT -75.885 687.330 -50.260 687.630 ;
    END
  END row_on_detect_bot<10>
  PIN row_off_detect_bot<26>
    ANTENNAGATEAREA 8.064000 ;
    PORT
      LAYER met3 ;
        RECT -75.885 496.930 -50.260 497.230 ;
    END
  END row_off_detect_bot<26>
  PIN row_on_detect_bot<22>
    ANTENNAGATEAREA 16.128000 ;
    PORT
      LAYER met3 ;
        RECT -75.885 543.700 -50.260 544.150 ;
    END
  END row_on_detect_bot<22>
  PIN row_on_detect_bot<7>
    ANTENNAGATEAREA 16.128000 ;
    PORT
      LAYER met3 ;
        RECT -75.885 734.930 -50.260 735.230 ;
    END
  END row_on_detect_bot<7>
  PIN row_on_detect_bot<8>
    ANTENNAGATEAREA 16.128000 ;
    PORT
      LAYER met3 ;
        RECT -75.885 711.810 -50.260 712.110 ;
    END
  END row_on_detect_bot<8>
  PIN row_off_detect_bot<60>
    ANTENNAGATEAREA 8.064000 ;
    PORT
      LAYER met3 ;
        RECT -75.885 88.930 -50.260 89.230 ;
    END
  END row_off_detect_bot<60>
  PIN row_on_detect_bot<43>
    ANTENNAGATEAREA 16.128000 ;
    PORT
      LAYER met3 ;
        RECT -75.885 302.450 -50.260 302.750 ;
    END
  END row_on_detect_bot<43>
  PIN row_on_detect_bot<36>
    ANTENNAGATEAREA 16.128000 ;
    PORT
      LAYER met3 ;
        RECT -75.885 375.210 -50.260 375.510 ;
    END
  END row_on_detect_bot<36>
  PIN row_off_detect_bot<56>
    ANTENNAGATEAREA 8.064000 ;
    PORT
      LAYER met3 ;
        RECT -75.885 136.530 -50.260 136.830 ;
    END
  END row_off_detect_bot<56>
  PIN row_off_detect_bot<55>
    ANTENNAGATEAREA 8.064000 ;
    PORT
      LAYER met3 ;
        RECT -75.885 157.610 -50.260 157.910 ;
    END
  END row_off_detect_bot<55>
  PIN row_off_detect_bot<57>
    ANTENNAGATEAREA 8.064000 ;
    PORT
      LAYER met3 ;
        RECT -75.885 133.130 -50.260 133.430 ;
    END
  END row_off_detect_bot<57>
  PIN row_on_detect_bot<38>
    ANTENNAGATEAREA 16.128000 ;
    PORT
      LAYER met3 ;
        RECT -75.885 351.410 -50.260 351.710 ;
    END
  END row_on_detect_bot<38>
  PIN row_off_detect_bot<52>
    ANTENNAGATEAREA 8.064000 ;
    PORT
      LAYER met3 ;
        RECT -75.885 184.810 -50.260 185.110 ;
    END
  END row_off_detect_bot<52>
  PIN row_on_detect_bot<63>
    ANTENNAGATEAREA 16.128000 ;
    PORT
      LAYER met3 ;
        RECT -75.885 62.410 -50.260 62.710 ;
    END
  END row_on_detect_bot<63>
  PIN row_on_detect_bot<53>
    ANTENNAGATEAREA 16.128000 ;
    PORT
      LAYER met3 ;
        RECT -75.885 182.090 -50.260 182.680 ;
    END
  END row_on_detect_bot<53>
  PIN row_on_detect_bot<40>
    ANTENNAGATEAREA 16.128000 ;
    PORT
      LAYER met3 ;
        RECT -75.885 327.610 -50.260 327.910 ;
    END
  END row_on_detect_bot<40>
  PIN row_off_detect_bot<37>
    ANTENNAGATEAREA 8.064000 ;
    PORT
      LAYER met3 ;
        RECT -75.885 373.170 -50.260 373.470 ;
    END
  END row_off_detect_bot<37>
  PIN row_on_detect_bot<37>
    ANTENNAGATEAREA 16.128000 ;
    PORT
      LAYER met3 ;
        RECT -75.885 374.530 -50.260 374.830 ;
    END
  END row_on_detect_bot<37>
  PIN row_on_detect_bot<42>
    ANTENNAGATEAREA 16.128000 ;
    PORT
      LAYER met3 ;
        RECT -75.885 303.810 -50.260 304.110 ;
    END
  END row_on_detect_bot<42>
  PIN row_on_detect_bot<49>
    ANTENNAGATEAREA 16.128000 ;
    PORT
      LAYER met3 ;
        RECT -75.885 230.370 -50.260 230.670 ;
    END
  END row_on_detect_bot<49>
  PIN row_on_detect_bot<50>
    ANTENNAGATEAREA 16.128000 ;
    PORT
      LAYER met3 ;
        RECT -75.885 207.250 -50.260 207.550 ;
    END
  END row_on_detect_bot<50>
  PIN row_off_detect_bot<42>
    ANTENNAGATEAREA 8.064000 ;
    PORT
      LAYER met3 ;
        RECT -75.885 304.490 -50.260 304.790 ;
    END
  END row_off_detect_bot<42>
  PIN row_off_detect_bot<36>
    ANTENNAGATEAREA 8.064000 ;
    PORT
      LAYER met3 ;
        RECT -75.885 376.570 -50.260 376.870 ;
    END
  END row_off_detect_bot<36>
  PIN row_off_detect_bot<58>
    ANTENNAGATEAREA 8.064000 ;
    PORT
      LAYER met3 ;
        RECT -75.885 112.730 -50.260 113.030 ;
    END
  END row_off_detect_bot<58>
  PIN row_off_detect_bot<59>
    ANTENNAGATEAREA 8.064000 ;
    PORT
      LAYER met3 ;
        RECT -75.885 109.330 -50.260 109.630 ;
    END
  END row_off_detect_bot<59>
  PIN row_off_detect_bot<46>
    ANTENNAGATEAREA 8.064000 ;
    PORT
      LAYER met3 ;
        RECT -75.885 256.890 -50.260 257.190 ;
    END
  END row_off_detect_bot<46>
  PIN row_off_detect_bot<47>
    ANTENNAGATEAREA 8.064000 ;
    PORT
      LAYER met3 ;
        RECT -75.885 253.490 -50.260 253.790 ;
    END
  END row_off_detect_bot<47>
  PIN row_on_detect_bot<51>
    ANTENNAGATEAREA 16.128000 ;
    PORT
      LAYER met3 ;
        RECT -75.885 206.570 -50.260 206.870 ;
    END
  END row_on_detect_bot<51>
  PIN row_on_detect_bot<52>
    ANTENNAGATEAREA 16.128000 ;
    PORT
      LAYER met3 ;
        RECT -75.885 183.450 -50.260 183.750 ;
    END
  END row_on_detect_bot<52>
  PIN row_off_detect_bot<38>
    ANTENNAGATEAREA 8.064000 ;
    PORT
      LAYER met3 ;
        RECT -75.885 352.770 -50.260 353.070 ;
    END
  END row_off_detect_bot<38>
  PIN row_off_detect_bot<39>
    ANTENNAGATEAREA 8.064000 ;
    PORT
      LAYER met3 ;
        RECT -75.885 349.370 -50.260 349.670 ;
    END
  END row_off_detect_bot<39>
  PIN row_off_detect_bot<40>
    ANTENNAGATEAREA 8.064000 ;
    PORT
      LAYER met3 ;
        RECT -75.885 328.970 -50.260 329.270 ;
    END
  END row_off_detect_bot<40>
  PIN row_on_detect_bot<47>
    ANTENNAGATEAREA 16.128000 ;
    PORT
      LAYER met3 ;
        RECT -75.885 254.850 -50.260 255.150 ;
    END
  END row_on_detect_bot<47>
  PIN row_on_detect_bot<48>
    ANTENNAGATEAREA 16.128000 ;
    PORT
      LAYER met3 ;
        RECT -75.885 231.730 -50.260 232.030 ;
    END
  END row_on_detect_bot<48>
  PIN row_off_detect_bot<63>
    ANTENNAGATEAREA 8.064000 ;
    PORT
      LAYER met3 ;
        RECT -75.885 61.730 -50.260 62.030 ;
    END
  END row_off_detect_bot<63>
  PIN row_on_detect_bot<54>
    ANTENNAGATEAREA 16.128000 ;
    PORT
      LAYER met3 ;
        RECT -75.885 159.650 -50.260 159.950 ;
    END
  END row_on_detect_bot<54>
  PIN row_on_detect_bot<60>
    ANTENNAGATEAREA 16.128000 ;
    PORT
      LAYER met3 ;
        RECT -75.885 87.570 -50.260 87.870 ;
    END
  END row_on_detect_bot<60>
  PIN row_off_detect_bot<53>
    ANTENNAGATEAREA 8.064000 ;
    PORT
      LAYER met3 ;
        RECT -75.885 181.410 -50.260 181.710 ;
    END
  END row_off_detect_bot<53>
  PIN row_on_detect_bot<39>
    ANTENNAGATEAREA 16.128000 ;
    PORT
      LAYER met3 ;
        RECT -75.885 350.730 -50.260 351.030 ;
    END
  END row_on_detect_bot<39>
  PIN row_on_detect_bot<44>
    ANTENNAGATEAREA 16.128000 ;
    PORT
      LAYER met3 ;
        RECT -75.885 279.330 -50.260 279.630 ;
    END
  END row_on_detect_bot<44>
  PIN row_on_detect_bot<61>
    ANTENNAGATEAREA 16.128000 ;
    PORT
      LAYER met3 ;
        RECT -75.885 86.890 -50.260 87.190 ;
    END
  END row_on_detect_bot<61>
  PIN row_off_detect_bot<61>
    ANTENNAGATEAREA 8.064000 ;
    PORT
      LAYER met3 ;
        RECT -75.885 85.530 -50.260 85.830 ;
    END
  END row_off_detect_bot<61>
  PIN row_off_detect_bot<54>
    ANTENNAGATEAREA 8.064000 ;
    PORT
      LAYER met3 ;
        RECT -75.885 161.010 -50.260 161.310 ;
    END
  END row_off_detect_bot<54>
  PIN row_off_detect_bot<43>
    ANTENNAGATEAREA 8.064000 ;
    PORT
      LAYER met3 ;
        RECT -75.885 301.090 -50.260 301.390 ;
    END
  END row_off_detect_bot<43>
  PIN row_off_detect_bot<44>
    ANTENNAGATEAREA 8.064000 ;
    PORT
      LAYER met3 ;
        RECT -75.885 280.690 -50.260 280.990 ;
    END
  END row_off_detect_bot<44>
  PIN row_off_detect_bot<45>
    ANTENNAGATEAREA 8.064000 ;
    PORT
      LAYER met3 ;
        RECT -75.885 277.290 -50.260 277.590 ;
    END
  END row_off_detect_bot<45>
  PIN row_on_detect_bot<62>
    ANTENNAGATEAREA 16.128000 ;
    PORT
      LAYER met3 ;
        RECT -75.885 63.770 -50.260 64.070 ;
    END
  END row_on_detect_bot<62>
  PIN detect_pulse_global_bot_left
    ANTENNAGATEAREA 147.199997 ;
    PORT
      LAYER met3 ;
        RECT -75.885 18.225 3.040 19.585 ;
    END
  END detect_pulse_global_bot_left
  PIN row_off_detect_bot<41>
    ANTENNAGATEAREA 8.064000 ;
    PORT
      LAYER met3 ;
        RECT -75.885 325.570 -50.260 325.870 ;
    END
  END row_off_detect_bot<41>
  PIN row_off_detect_bot<48>
    ANTENNAGATEAREA 8.064000 ;
    PORT
      LAYER met3 ;
        RECT -75.885 232.410 -50.260 232.710 ;
    END
  END row_off_detect_bot<48>
  PIN row_off_detect_bot<49>
    ANTENNAGATEAREA 8.064000 ;
    PORT
      LAYER met3 ;
        RECT -75.885 229.690 -50.260 229.990 ;
    END
  END row_off_detect_bot<49>
  PIN row_off_detect_bot<50>
    ANTENNAGATEAREA 8.064000 ;
    PORT
      LAYER met3 ;
        RECT -75.885 208.610 -50.260 208.910 ;
    END
  END row_off_detect_bot<50>
  PIN row_off_detect_bot<51>
    ANTENNAGATEAREA 8.064000 ;
    PORT
      LAYER met3 ;
        RECT -75.885 205.210 -50.260 205.510 ;
    END
  END row_off_detect_bot<51>
  PIN row_on_detect_bot<58>
    ANTENNAGATEAREA 16.128000 ;
    PORT
      LAYER met3 ;
        RECT -75.885 111.730 -50.260 112.350 ;
    END
  END row_on_detect_bot<58>
  PIN row_on_detect_bot<41>
    ANTENNAGATEAREA 16.128000 ;
    PORT
      LAYER met3 ;
        RECT -75.885 326.930 -50.260 327.230 ;
    END
  END row_on_detect_bot<41>
  PIN row_on_detect_bot<55>
    ANTENNAGATEAREA 16.128000 ;
    PORT
      LAYER met3 ;
        RECT -75.885 158.290 -50.260 158.590 ;
    END
  END row_on_detect_bot<55>
  PIN row_on_detect_bot<56>
    ANTENNAGATEAREA 16.128000 ;
    PORT
      LAYER met3 ;
        RECT -75.885 135.700 -50.260 136.150 ;
    END
  END row_on_detect_bot<56>
  PIN row_on_detect_bot<57>
    ANTENNAGATEAREA 16.128000 ;
    PORT
      LAYER met3 ;
        RECT -75.885 134.490 -50.260 134.790 ;
    END
  END row_on_detect_bot<57>
  PIN ndetect_pulse_global_bot_left
    ANTENNAGATEAREA 64.000000 ;
    PORT
      LAYER met3 ;
        RECT -75.885 9.385 3.040 10.775 ;
    END
  END ndetect_pulse_global_bot_left
  PIN row_on_detect_bot<45>
    ANTENNAGATEAREA 16.128000 ;
    PORT
      LAYER met3 ;
        RECT -75.885 278.650 -50.260 278.950 ;
    END
  END row_on_detect_bot<45>
  PIN pre_charge_global_bot_left
    ANTENNAGATEAREA 1024.000000 ;
    PORT
      LAYER met3 ;
        RECT -75.885 29.755 3.040 31.115 ;
    END
  END pre_charge_global_bot_left
  PIN row_on_detect_bot<59>
    ANTENNAGATEAREA 16.128000 ;
    PORT
      LAYER met3 ;
        RECT -75.885 110.690 -50.260 110.990 ;
    END
  END row_on_detect_bot<59>
  PIN row_on_detect_bot<46>
    ANTENNAGATEAREA 16.128000 ;
    PORT
      LAYER met3 ;
        RECT -75.885 255.530 -50.260 255.830 ;
    END
  END row_on_detect_bot<46>
  PIN row_off_detect_bot<62>
    ANTENNAGATEAREA 8.064000 ;
    PORT
      LAYER met3 ;
        RECT -75.885 64.450 -50.260 64.750 ;
    END
  END row_off_detect_bot<62>
  PIN dac_config_1
    ANTENNAGATEAREA 36864.000000 ;
    PORT
      LAYER met3 ;
        RECT 1605.820 818.220 1616.380 819.220 ;
    END
  END dac_config_1
  PIN dac_config_0
    ANTENNAGATEAREA 36864.000000 ;
    PORT
      LAYER met3 ;
        RECT 1605.820 816.180 1616.380 817.180 ;
    END
  END dac_config_0
  PIN dac_config_6
    ANTENNAGATEAREA 38.399998 ;
    PORT
      LAYER met3 ;
        RECT 1605.820 814.140 1616.380 815.140 ;
    END
  END dac_config_6
  PIN col_event_rst_top_right<20>
    ANTENNAGATEAREA 4.032000 ;
    PORT
      LAYER met4 ;
        RECT 1296.780 1703.180 1298.160 1713.785 ;
    END
  END col_event_rst_top_right<20>
  PIN array_col_top_right<0>
    ANTENNADIFFAREA 0.870000 ;
    PORT
      LAYER met4 ;
        RECT 1534.020 1703.180 1535.860 1713.785 ;
    END
  END array_col_top_right<0>
  PIN col_event_rst_top_right<27>
    ANTENNAGATEAREA 4.032000 ;
    PORT
      LAYER met4 ;
        RECT 1203.220 1703.180 1204.600 1713.785 ;
    END
  END col_event_rst_top_right<27>
  PIN array_col_top_right<7>
    ANTENNADIFFAREA 0.870000 ;
    PORT
      LAYER met4 ;
        RECT 1445.520 1703.180 1447.360 1713.785 ;
    END
  END array_col_top_right<7>
  PIN col_event_rst_top_right<19>
    ANTENNAGATEAREA 4.032000 ;
    PORT
      LAYER met4 ;
        RECT 1299.220 1703.180 1300.600 1713.785 ;
    END
  END col_event_rst_top_right<19>
  PIN col_event_rst_top_right<25>
    ANTENNAGATEAREA 4.032000 ;
    PORT
      LAYER met4 ;
        RECT 1227.220 1703.180 1228.600 1713.785 ;
    END
  END col_event_rst_top_right<25>
  PIN col_event_rst_top_right<18>
    ANTENNAGATEAREA 4.032000 ;
    PORT
      LAYER met4 ;
        RECT 1320.780 1703.180 1322.160 1713.785 ;
    END
  END col_event_rst_top_right<18>
  PIN array_col_top_right<6>
    ANTENNADIFFAREA 0.870000 ;
    PORT
      LAYER met4 ;
        RECT 1462.020 1703.180 1463.860 1713.785 ;
    END
  END array_col_top_right<6>
  PIN array_col_top_right<22>
    ANTENNADIFFAREA 0.870000 ;
    PORT
      LAYER met4 ;
        RECT 1270.365 1703.180 1272.205 1713.785 ;
    END
  END array_col_top_right<22>
  PIN array_col_top_right<1>
    ANTENNADIFFAREA 0.870000 ;
    PORT
      LAYER met4 ;
        RECT 1517.520 1703.180 1519.360 1713.785 ;
    END
  END array_col_top_right<1>
  PIN array_col_top_right<5>
    ANTENNADIFFAREA 0.870000 ;
    PORT
      LAYER met4 ;
        RECT 1469.520 1703.180 1471.360 1713.785 ;
    END
  END array_col_top_right<5>
  PIN col_event_rst_top_right<17>
    ANTENNAGATEAREA 4.032000 ;
    PORT
      LAYER met4 ;
        RECT 1323.220 1703.180 1324.600 1713.785 ;
    END
  END col_event_rst_top_right<17>
  PIN array_col_top_right<28>
    ANTENNADIFFAREA 0.870000 ;
    PORT
      LAYER met4 ;
        RECT 1198.020 1703.180 1199.860 1713.785 ;
    END
  END array_col_top_right<28>
  PIN col_event_rst_top_right<24>
    ANTENNAGATEAREA 4.032000 ;
    PORT
      LAYER met4 ;
        RECT 1248.780 1703.180 1250.160 1713.785 ;
    END
  END col_event_rst_top_right<24>
  PIN col_event_rst_top_right<16>
    ANTENNAGATEAREA 4.032000 ;
    PORT
      LAYER met4 ;
        RECT 1344.780 1703.180 1346.160 1713.785 ;
    END
  END col_event_rst_top_right<16>
  PIN array_col_top_right<8>
    ANTENNADIFFAREA 0.870000 ;
    PORT
      LAYER met4 ;
        RECT 1438.020 1703.180 1439.860 1713.785 ;
    END
  END array_col_top_right<8>
  PIN array_col_top_right<9>
    ANTENNADIFFAREA 0.870000 ;
    PORT
      LAYER met4 ;
        RECT 1421.520 1703.180 1423.360 1713.785 ;
    END
  END array_col_top_right<9>
  PIN col_event_rst_top_right<23>
    ANTENNAGATEAREA 4.032000 ;
    PORT
      LAYER met4 ;
        RECT 1251.220 1703.180 1252.600 1713.785 ;
    END
  END col_event_rst_top_right<23>
  PIN col_event_rst_top_right<15>
    ANTENNAGATEAREA 4.032000 ;
    PORT
      LAYER met4 ;
        RECT 1347.220 1703.180 1348.600 1713.785 ;
    END
  END col_event_rst_top_right<15>
  PIN col_event_rst_top_right<22>
    ANTENNAGATEAREA 4.032000 ;
    PORT
      LAYER met4 ;
        RECT 1272.780 1703.180 1274.160 1713.785 ;
    END
  END col_event_rst_top_right<22>
  PIN col_event_rst_top_right<14>
    ANTENNAGATEAREA 4.032000 ;
    PORT
      LAYER met4 ;
        RECT 1368.780 1703.180 1370.160 1713.785 ;
    END
  END col_event_rst_top_right<14>
  PIN array_col_top_right<3>
    ANTENNADIFFAREA 0.870000 ;
    PORT
      LAYER met4 ;
        RECT 1493.520 1703.180 1495.360 1713.785 ;
    END
  END array_col_top_right<3>
  PIN col_event_rst_top_right<13>
    ANTENNAGATEAREA 4.032000 ;
    PORT
      LAYER met4 ;
        RECT 1371.220 1703.180 1372.600 1713.785 ;
    END
  END col_event_rst_top_right<13>
  PIN col_event_rst_top_right<12>
    ANTENNAGATEAREA 4.032000 ;
    PORT
      LAYER met4 ;
        RECT 1392.780 1703.180 1394.160 1713.785 ;
    END
  END col_event_rst_top_right<12>
  PIN array_col_top_right<20>
    ANTENNADIFFAREA 0.870000 ;
    PORT
      LAYER met4 ;
        RECT 1294.020 1703.180 1295.860 1713.785 ;
    END
  END array_col_top_right<20>
  PIN col_event_rst_top_right<11>
    ANTENNAGATEAREA 4.032000 ;
    PORT
      LAYER met4 ;
        RECT 1395.220 1703.180 1396.600 1713.785 ;
    END
  END col_event_rst_top_right<11>
  PIN array_col_top_right<17>
    ANTENNADIFFAREA 0.870000 ;
    PORT
      LAYER met4 ;
        RECT 1325.520 1703.180 1327.360 1713.785 ;
    END
  END array_col_top_right<17>
  PIN array_col_top_right<4>
    ANTENNADIFFAREA 0.870000 ;
    PORT
      LAYER met4 ;
        RECT 1486.020 1703.180 1487.860 1713.785 ;
    END
  END array_col_top_right<4>
  PIN col_event_rst_top_right<10>
    ANTENNAGATEAREA 4.032000 ;
    PORT
      LAYER met4 ;
        RECT 1416.780 1703.180 1418.160 1713.785 ;
    END
  END col_event_rst_top_right<10>
  PIN array_col_top_right<2>
    ANTENNADIFFAREA 0.870000 ;
    PORT
      LAYER met4 ;
        RECT 1510.020 1703.180 1511.860 1713.785 ;
    END
  END array_col_top_right<2>
  PIN array_col_top_right<12>
    ANTENNADIFFAREA 0.870000 ;
    PORT
      LAYER met4 ;
        RECT 1390.020 1703.180 1391.860 1713.785 ;
    END
  END array_col_top_right<12>
  PIN array_col_top_right<19>
    ANTENNADIFFAREA 0.870000 ;
    PORT
      LAYER met4 ;
        RECT 1301.520 1703.180 1303.360 1713.785 ;
    END
  END array_col_top_right<19>
  PIN array_col_top_right<13>
    ANTENNADIFFAREA 0.870000 ;
    PORT
      LAYER met4 ;
        RECT 1373.520 1703.180 1375.360 1713.785 ;
    END
  END array_col_top_right<13>
  PIN col_event_rst_top_right<9>
    ANTENNAGATEAREA 4.032000 ;
    PORT
      LAYER met4 ;
        RECT 1419.220 1703.180 1420.600 1713.785 ;
    END
  END col_event_rst_top_right<9>
  PIN col_event_rst_top_right<21>
    ANTENNAGATEAREA 4.032000 ;
    PORT
      LAYER met4 ;
        RECT 1275.220 1703.180 1276.600 1713.785 ;
    END
  END col_event_rst_top_right<21>
  PIN array_col_top_right<18>
    ANTENNADIFFAREA 0.870000 ;
    PORT
      LAYER met4 ;
        RECT 1318.020 1703.180 1319.860 1713.785 ;
    END
  END array_col_top_right<18>
  PIN array_col_top_right<16>
    ANTENNADIFFAREA 0.870000 ;
    PORT
      LAYER met4 ;
        RECT 1342.020 1703.180 1343.860 1713.785 ;
    END
  END array_col_top_right<16>
  PIN col_event_rst_top_right<8>
    ANTENNAGATEAREA 4.032000 ;
    PORT
      LAYER met4 ;
        RECT 1440.780 1703.180 1442.160 1713.785 ;
    END
  END col_event_rst_top_right<8>
  PIN array_col_top_right<15>
    ANTENNADIFFAREA 0.870000 ;
    PORT
      LAYER met4 ;
        RECT 1349.520 1703.180 1351.360 1713.785 ;
    END
  END array_col_top_right<15>
  PIN array_col_top_right<11>
    ANTENNADIFFAREA 0.870000 ;
    PORT
      LAYER met4 ;
        RECT 1397.520 1703.180 1399.360 1713.785 ;
    END
  END array_col_top_right<11>
  PIN col_event_rst_top_right<7>
    ANTENNAGATEAREA 4.032000 ;
    PORT
      LAYER met4 ;
        RECT 1443.220 1703.180 1444.600 1713.785 ;
    END
  END col_event_rst_top_right<7>
  PIN array_col_top_right<26>
    ANTENNADIFFAREA 0.870000 ;
    PORT
      LAYER met4 ;
        RECT 1222.020 1703.180 1223.860 1713.785 ;
    END
  END array_col_top_right<26>
  PIN array_col_top_right<10>
    ANTENNADIFFAREA 0.870000 ;
    PORT
      LAYER met4 ;
        RECT 1414.020 1703.180 1415.860 1713.785 ;
    END
  END array_col_top_right<10>
  PIN col_event_rst_top_right<6>
    ANTENNAGATEAREA 4.032000 ;
    PORT
      LAYER met4 ;
        RECT 1464.780 1703.180 1466.160 1713.785 ;
    END
  END col_event_rst_top_right<6>
  PIN array_col_top_right<27>
    ANTENNADIFFAREA 0.870000 ;
    PORT
      LAYER met4 ;
        RECT 1205.520 1703.180 1207.360 1713.785 ;
    END
  END array_col_top_right<27>
  PIN col_event_rst_top_right<5>
    ANTENNAGATEAREA 4.032000 ;
    PORT
      LAYER met4 ;
        RECT 1467.220 1703.180 1468.600 1713.785 ;
    END
  END col_event_rst_top_right<5>
  PIN array_col_top_right<25>
    ANTENNADIFFAREA 0.870000 ;
    PORT
      LAYER met4 ;
        RECT 1229.520 1703.180 1231.360 1713.785 ;
    END
  END array_col_top_right<25>
  PIN col_event_rst_top_right<4>
    ANTENNAGATEAREA 4.032000 ;
    PORT
      LAYER met4 ;
        RECT 1488.780 1703.180 1490.160 1713.785 ;
    END
  END col_event_rst_top_right<4>
  PIN col_event_rst_top_right<28>
    ANTENNAGATEAREA 4.032000 ;
    PORT
      LAYER met4 ;
        RECT 1200.780 1703.180 1202.160 1713.785 ;
    END
  END col_event_rst_top_right<28>
  PIN array_col_top_right<24>
    ANTENNADIFFAREA 0.870000 ;
    PORT
      LAYER met4 ;
        RECT 1246.020 1703.180 1247.860 1713.785 ;
    END
  END array_col_top_right<24>
  PIN col_event_rst_top_right<3>
    ANTENNAGATEAREA 4.032000 ;
    PORT
      LAYER met4 ;
        RECT 1491.220 1703.180 1492.600 1713.785 ;
    END
  END col_event_rst_top_right<3>
  PIN array_col_top_right<23>
    ANTENNADIFFAREA 0.870000 ;
    PORT
      LAYER met4 ;
        RECT 1253.520 1703.180 1255.360 1713.785 ;
    END
  END array_col_top_right<23>
  PIN col_event_rst_top_right<2>
    ANTENNAGATEAREA 4.032000 ;
    PORT
      LAYER met4 ;
        RECT 1512.780 1703.180 1514.160 1713.785 ;
    END
  END col_event_rst_top_right<2>
  PIN col_event_rst_top_right<26>
    ANTENNAGATEAREA 4.032000 ;
    PORT
      LAYER met4 ;
        RECT 1224.780 1703.180 1226.160 1713.785 ;
    END
  END col_event_rst_top_right<26>
  PIN col_event_rst_top_right<1>
    ANTENNAGATEAREA 4.032000 ;
    PORT
      LAYER met4 ;
        RECT 1515.220 1703.180 1516.600 1713.785 ;
    END
  END col_event_rst_top_right<1>
  PIN array_col_top_right<21>
    ANTENNADIFFAREA 0.870000 ;
    PORT
      LAYER met4 ;
        RECT 1277.520 1703.180 1279.360 1713.785 ;
    END
  END array_col_top_right<21>
  PIN col_event_rst_top_right<0>
    ANTENNAGATEAREA 4.032000 ;
    PORT
      LAYER met4 ;
        RECT 1536.780 1703.180 1538.160 1713.785 ;
    END
  END col_event_rst_top_right<0>
  PIN array_col_top_right<14>
    ANTENNADIFFAREA 0.870000 ;
    PORT
      LAYER met4 ;
        RECT 1366.020 1703.180 1367.860 1713.785 ;
    END
  END array_col_top_right<14>
  PIN array_col_top_right<40>
    ANTENNADIFFAREA 0.870000 ;
    PORT
      LAYER met4 ;
        RECT 1054.020 1703.180 1055.860 1713.785 ;
    END
  END array_col_top_right<40>
  PIN array_col_top_right<36>
    ANTENNADIFFAREA 0.870000 ;
    PORT
      LAYER met4 ;
        RECT 1102.020 1703.180 1103.860 1713.785 ;
    END
  END array_col_top_right<36>
  PIN col_event_rst_top_right<40>
    ANTENNAGATEAREA 4.032000 ;
    PORT
      LAYER met4 ;
        RECT 1056.780 1703.180 1058.160 1713.785 ;
    END
  END col_event_rst_top_right<40>
  PIN col_event_rst_top_right<50>
    ANTENNAGATEAREA 4.032000 ;
    PORT
      LAYER met4 ;
        RECT 936.780 1703.180 938.160 1713.785 ;
    END
  END col_event_rst_top_right<50>
  PIN col_event_rst_top_right<39>
    ANTENNAGATEAREA 4.032000 ;
    PORT
      LAYER met4 ;
        RECT 1059.220 1703.180 1060.600 1713.785 ;
    END
  END col_event_rst_top_right<39>
  PIN col_event_rst_top_right<38>
    ANTENNAGATEAREA 4.032000 ;
    PORT
      LAYER met4 ;
        RECT 1080.780 1703.180 1082.160 1713.785 ;
    END
  END col_event_rst_top_right<38>
  PIN array_col_top_right<29>
    ANTENNADIFFAREA 0.870000 ;
    PORT
      LAYER met4 ;
        RECT 1181.520 1703.180 1183.360 1713.785 ;
    END
  END array_col_top_right<29>
  PIN col_event_rst_top_right<49>
    ANTENNAGATEAREA 4.032000 ;
    PORT
      LAYER met4 ;
        RECT 939.220 1703.180 940.600 1713.785 ;
    END
  END col_event_rst_top_right<49>
  PIN array_col_top_right<31>
    ANTENNADIFFAREA 0.870000 ;
    PORT
      LAYER met4 ;
        RECT 1157.520 1703.180 1159.360 1713.785 ;
    END
  END array_col_top_right<31>
  PIN col_event_rst_top_right<37>
    ANTENNAGATEAREA 4.032000 ;
    PORT
      LAYER met4 ;
        RECT 1083.220 1703.180 1084.600 1713.785 ;
    END
  END col_event_rst_top_right<37>
  PIN array_col_top_right<30>
    ANTENNADIFFAREA 0.870000 ;
    PORT
      LAYER met4 ;
        RECT 1174.020 1703.180 1175.860 1713.785 ;
    END
  END array_col_top_right<30>
  PIN col_event_rst_top_right<46>
    ANTENNAGATEAREA 4.032000 ;
    PORT
      LAYER met4 ;
        RECT 984.780 1703.180 986.160 1713.785 ;
    END
  END col_event_rst_top_right<46>
  PIN col_event_rst_top_right<36>
    ANTENNAGATEAREA 4.032000 ;
    PORT
      LAYER met4 ;
        RECT 1104.780 1703.180 1106.160 1713.785 ;
    END
  END col_event_rst_top_right<36>
  PIN col_event_rst_top_right<35>
    ANTENNAGATEAREA 4.032000 ;
    PORT
      LAYER met4 ;
        RECT 1107.220 1703.180 1108.600 1713.785 ;
    END
  END col_event_rst_top_right<35>
  PIN col_event_rst_top_right<62>
    ANTENNAGATEAREA 4.032000 ;
    PORT
      LAYER met4 ;
        RECT 792.780 1703.180 794.160 1713.785 ;
    END
  END col_event_rst_top_right<62>
  PIN col_event_rst_top_right<34>
    ANTENNAGATEAREA 4.032000 ;
    PORT
      LAYER met4 ;
        RECT 1128.780 1703.180 1130.160 1713.785 ;
    END
  END col_event_rst_top_right<34>
  PIN col_event_rst_top_right<33>
    ANTENNAGATEAREA 4.032000 ;
    PORT
      LAYER met4 ;
        RECT 1131.220 1703.180 1132.600 1713.785 ;
    END
  END col_event_rst_top_right<33>
  PIN col_event_rst_top_right<32>
    ANTENNAGATEAREA 4.032000 ;
    PORT
      LAYER met4 ;
        RECT 1152.780 1703.180 1154.160 1713.785 ;
    END
  END col_event_rst_top_right<32>
  PIN col_event_rst_top_right<45>
    ANTENNAGATEAREA 4.032000 ;
    PORT
      LAYER met4 ;
        RECT 987.220 1703.180 988.600 1713.785 ;
    END
  END col_event_rst_top_right<45>
  PIN col_event_rst_top_right<44>
    ANTENNAGATEAREA 4.032000 ;
    PORT
      LAYER met4 ;
        RECT 1008.780 1703.180 1010.160 1713.785 ;
    END
  END col_event_rst_top_right<44>
  PIN col_event_rst_top_right<47>
    ANTENNAGATEAREA 4.032000 ;
    PORT
      LAYER met4 ;
        RECT 963.220 1703.180 964.600 1713.785 ;
    END
  END col_event_rst_top_right<47>
  PIN col_event_rst_top_right<43>
    ANTENNAGATEAREA 4.032000 ;
    PORT
      LAYER met4 ;
        RECT 1011.220 1703.180 1012.600 1713.785 ;
    END
  END col_event_rst_top_right<43>
  PIN col_event_rst_top_right<48>
    ANTENNAGATEAREA 4.032000 ;
    PORT
      LAYER met4 ;
        RECT 960.780 1703.180 962.160 1713.785 ;
    END
  END col_event_rst_top_right<48>
  PIN col_event_rst_top_right<52>
    ANTENNAGATEAREA 4.032000 ;
    PORT
      LAYER met4 ;
        RECT 912.780 1703.180 914.160 1713.785 ;
    END
  END col_event_rst_top_right<52>
  PIN col_event_rst_top_right<56>
    ANTENNAGATEAREA 4.032000 ;
    PORT
      LAYER met4 ;
        RECT 864.780 1703.180 866.160 1713.785 ;
    END
  END col_event_rst_top_right<56>
  PIN col_event_rst_top_right<59>
    ANTENNAGATEAREA 4.032000 ;
    PORT
      LAYER met4 ;
        RECT 819.220 1703.180 820.600 1713.785 ;
    END
  END col_event_rst_top_right<59>
  PIN array_col_top_right<38>
    ANTENNADIFFAREA 0.870000 ;
    PORT
      LAYER met4 ;
        RECT 1078.020 1703.180 1079.860 1713.785 ;
    END
  END array_col_top_right<38>
  PIN col_event_rst_top_right<42>
    ANTENNAGATEAREA 4.032000 ;
    PORT
      LAYER met4 ;
        RECT 1032.780 1703.180 1034.160 1713.785 ;
    END
  END col_event_rst_top_right<42>
  PIN col_event_rst_top_right<51>
    ANTENNAGATEAREA 4.032000 ;
    PORT
      LAYER met4 ;
        RECT 915.220 1703.180 916.600 1713.785 ;
    END
  END col_event_rst_top_right<51>
  PIN col_event_rst_top_right<60>
    ANTENNAGATEAREA 4.032000 ;
    PORT
      LAYER met4 ;
        RECT 816.780 1703.180 818.160 1713.785 ;
    END
  END col_event_rst_top_right<60>
  PIN col_event_rst_top_right<55>
    ANTENNAGATEAREA 4.032000 ;
    PORT
      LAYER met4 ;
        RECT 867.220 1703.180 868.600 1713.785 ;
    END
  END col_event_rst_top_right<55>
  PIN col_event_rst_top_right<41>
    ANTENNAGATEAREA 4.032000 ;
    PORT
      LAYER met4 ;
        RECT 1035.220 1703.180 1036.600 1713.785 ;
    END
  END col_event_rst_top_right<41>
  PIN array_col_top_right<33>
    ANTENNADIFFAREA 0.870000 ;
    PORT
      LAYER met4 ;
        RECT 1133.520 1703.180 1135.360 1713.785 ;
    END
  END array_col_top_right<33>
  PIN array_col_top_right<32>
    ANTENNADIFFAREA 0.870000 ;
    PORT
      LAYER met4 ;
        RECT 1150.020 1703.180 1151.860 1713.785 ;
    END
  END array_col_top_right<32>
  PIN array_col_top_right<61>
    ANTENNADIFFAREA 0.870000 ;
    PORT
      LAYER met4 ;
        RECT 797.520 1703.180 799.360 1713.785 ;
    END
  END array_col_top_right<61>
  PIN array_col_top_right<60>
    ANTENNADIFFAREA 0.870000 ;
    PORT
      LAYER met4 ;
        RECT 814.020 1703.180 815.860 1713.785 ;
    END
  END array_col_top_right<60>
  PIN col_event_rst_top_right<61>
    ANTENNAGATEAREA 4.032000 ;
    PORT
      LAYER met4 ;
        RECT 795.220 1703.180 796.600 1713.785 ;
    END
  END col_event_rst_top_right<61>
  PIN col_event_rst_top_right<57>
    ANTENNAGATEAREA 4.032000 ;
    PORT
      LAYER met4 ;
        RECT 843.220 1703.180 844.600 1713.785 ;
    END
  END col_event_rst_top_right<57>
  PIN col_event_rst_top_right<54>
    ANTENNAGATEAREA 4.032000 ;
    PORT
      LAYER met4 ;
        RECT 888.780 1703.180 890.160 1713.785 ;
    END
  END col_event_rst_top_right<54>
  PIN array_col_top_right<37>
    ANTENNADIFFAREA 0.870000 ;
    PORT
      LAYER met4 ;
        RECT 1085.520 1703.180 1087.360 1713.785 ;
    END
  END array_col_top_right<37>
  PIN col_event_rst_top_right<31>
    ANTENNAGATEAREA 4.032000 ;
    PORT
      LAYER met4 ;
        RECT 1155.220 1703.180 1156.600 1713.785 ;
    END
  END col_event_rst_top_right<31>
  PIN array_col_top_right<58>
    ANTENNADIFFAREA 0.870000 ;
    PORT
      LAYER met4 ;
        RECT 838.020 1703.180 839.860 1713.785 ;
    END
  END array_col_top_right<58>
  PIN array_col_top_right<57>
    ANTENNADIFFAREA 0.870000 ;
    PORT
      LAYER met4 ;
        RECT 845.520 1703.180 847.360 1713.785 ;
    END
  END array_col_top_right<57>
  PIN array_col_top_right<54>
    ANTENNADIFFAREA 0.870000 ;
    PORT
      LAYER met4 ;
        RECT 886.020 1703.180 887.860 1713.785 ;
    END
  END array_col_top_right<54>
  PIN array_col_top_right<51>
    ANTENNADIFFAREA 0.870000 ;
    PORT
      LAYER met4 ;
        RECT 917.520 1703.180 919.360 1713.785 ;
    END
  END array_col_top_right<51>
  PIN col_event_rst_top_right<30>
    ANTENNAGATEAREA 4.032000 ;
    PORT
      LAYER met4 ;
        RECT 1176.780 1703.180 1178.160 1713.785 ;
    END
  END col_event_rst_top_right<30>
  PIN array_col_top_right<50>
    ANTENNADIFFAREA 0.870000 ;
    PORT
      LAYER met4 ;
        RECT 934.020 1703.180 935.860 1713.785 ;
    END
  END array_col_top_right<50>
  PIN array_col_top_right<49>
    ANTENNADIFFAREA 0.870000 ;
    PORT
      LAYER met4 ;
        RECT 941.520 1703.180 943.360 1713.785 ;
    END
  END array_col_top_right<49>
  PIN array_col_top_right<48>
    ANTENNADIFFAREA 0.870000 ;
    PORT
      LAYER met4 ;
        RECT 958.020 1703.180 959.860 1713.785 ;
    END
  END array_col_top_right<48>
  PIN array_col_top_right<45>
    ANTENNADIFFAREA 0.870000 ;
    PORT
      LAYER met4 ;
        RECT 989.520 1703.180 991.360 1713.785 ;
    END
  END array_col_top_right<45>
  PIN array_col_top_right<42>
    ANTENNADIFFAREA 0.870000 ;
    PORT
      LAYER met4 ;
        RECT 1030.020 1703.180 1031.860 1713.785 ;
    END
  END array_col_top_right<42>
  PIN col_event_rst_top_right<29>
    ANTENNAGATEAREA 4.032000 ;
    PORT
      LAYER met4 ;
        RECT 1179.220 1703.180 1180.600 1713.785 ;
    END
  END col_event_rst_top_right<29>
  PIN array_col_top_right<41>
    ANTENNADIFFAREA 0.870000 ;
    PORT
      LAYER met4 ;
        RECT 1037.520 1703.180 1039.360 1713.785 ;
    END
  END array_col_top_right<41>
  PIN array_col_top_right<39>
    ANTENNADIFFAREA 0.870000 ;
    PORT
      LAYER met4 ;
        RECT 1061.520 1703.180 1063.360 1713.785 ;
    END
  END array_col_top_right<39>
  PIN col_event_rst_top_right<53>
    ANTENNAGATEAREA 4.032000 ;
    PORT
      LAYER met4 ;
        RECT 891.220 1703.180 892.600 1713.785 ;
    END
  END col_event_rst_top_right<53>
  PIN array_col_top_right<35>
    ANTENNADIFFAREA 0.870000 ;
    PORT
      LAYER met4 ;
        RECT 1109.520 1703.180 1111.360 1713.785 ;
    END
  END array_col_top_right<35>
  PIN array_col_top_right<34>
    ANTENNADIFFAREA 0.870000 ;
    PORT
      LAYER met4 ;
        RECT 1126.020 1703.180 1127.860 1713.785 ;
    END
  END array_col_top_right<34>
  PIN array_col_top_right<63>
    ANTENNADIFFAREA 0.870000 ;
    PORT
      LAYER met4 ;
        RECT 773.520 1703.180 775.360 1713.785 ;
    END
  END array_col_top_right<63>
  PIN array_col_top_right<62>
    ANTENNADIFFAREA 0.870000 ;
    PORT
      LAYER met4 ;
        RECT 790.020 1703.180 791.860 1713.785 ;
    END
  END array_col_top_right<62>
  PIN col_event_rst_top_right<58>
    ANTENNAGATEAREA 4.032000 ;
    PORT
      LAYER met4 ;
        RECT 840.780 1703.180 842.160 1713.785 ;
    END
  END col_event_rst_top_right<58>
  PIN array_col_top_right<59>
    ANTENNADIFFAREA 0.870000 ;
    PORT
      LAYER met4 ;
        RECT 821.520 1703.180 823.360 1713.785 ;
    END
  END array_col_top_right<59>
  PIN array_col_top_right<56>
    ANTENNADIFFAREA 0.870000 ;
    PORT
      LAYER met4 ;
        RECT 862.020 1703.180 863.860 1713.785 ;
    END
  END array_col_top_right<56>
  PIN array_col_top_right<55>
    ANTENNADIFFAREA 0.870000 ;
    PORT
      LAYER met4 ;
        RECT 869.520 1703.180 871.360 1713.785 ;
    END
  END array_col_top_right<55>
  PIN array_col_top_right<53>
    ANTENNADIFFAREA 0.870000 ;
    PORT
      LAYER met4 ;
        RECT 893.520 1703.180 895.360 1713.785 ;
    END
  END array_col_top_right<53>
  PIN array_col_top_right<52>
    ANTENNADIFFAREA 0.870000 ;
    PORT
      LAYER met4 ;
        RECT 910.020 1703.180 911.860 1713.785 ;
    END
  END array_col_top_right<52>
  PIN array_col_top_right<47>
    ANTENNADIFFAREA 0.870000 ;
    PORT
      LAYER met4 ;
        RECT 965.520 1703.180 967.360 1713.785 ;
    END
  END array_col_top_right<47>
  PIN array_col_top_right<46>
    ANTENNADIFFAREA 0.870000 ;
    PORT
      LAYER met4 ;
        RECT 982.020 1703.180 983.860 1713.785 ;
    END
  END array_col_top_right<46>
  PIN array_col_top_right<44>
    ANTENNADIFFAREA 0.870000 ;
    PORT
      LAYER met4 ;
        RECT 1006.020 1703.180 1007.860 1713.785 ;
    END
  END array_col_top_right<44>
  PIN array_col_top_right<43>
    ANTENNADIFFAREA 0.870000 ;
    PORT
      LAYER met4 ;
        RECT 1013.520 1703.180 1015.360 1713.785 ;
    END
  END array_col_top_right<43>
  PIN col_event_rst_top_right<63>
    ANTENNAGATEAREA 4.032000 ;
    PORT
      LAYER met4 ;
        RECT 771.220 1703.180 772.600 1713.785 ;
    END
  END col_event_rst_top_right<63>
  PIN array_col_top_left<25>
    ANTENNADIFFAREA 0.870000 ;
    PORT
      LAYER met4 ;
        RECT 461.520 1703.180 463.360 1713.785 ;
    END
  END array_col_top_left<25>
  PIN col_event_rst_top_left<32>
    ANTENNAGATEAREA 4.032000 ;
    PORT
      LAYER met4 ;
        RECT 384.780 1703.180 386.160 1713.785 ;
    END
  END col_event_rst_top_left<32>
  PIN array_col_top_left<34>
    ANTENNADIFFAREA 0.870000 ;
    PORT
      LAYER met4 ;
        RECT 358.020 1703.180 359.860 1713.785 ;
    END
  END array_col_top_left<34>
  PIN col_event_rst_top_left<33>
    ANTENNAGATEAREA 4.032000 ;
    PORT
      LAYER met4 ;
        RECT 363.220 1703.180 364.600 1713.785 ;
    END
  END col_event_rst_top_left<33>
  PIN array_col_top_left<33>
    ANTENNADIFFAREA 0.870000 ;
    PORT
      LAYER met4 ;
        RECT 365.520 1703.180 367.360 1713.785 ;
    END
  END array_col_top_left<33>
  PIN col_event_rst_top_left<34>
    ANTENNAGATEAREA 4.032000 ;
    PORT
      LAYER met4 ;
        RECT 360.780 1703.180 362.160 1713.785 ;
    END
  END col_event_rst_top_left<34>
  PIN array_col_top_left<32>
    ANTENNADIFFAREA 0.870000 ;
    PORT
      LAYER met4 ;
        RECT 382.020 1703.180 383.860 1713.785 ;
    END
  END array_col_top_left<32>
  PIN col_event_rst_top_left<12>
    ANTENNAGATEAREA 4.032000 ;
    PORT
      LAYER met4 ;
        RECT 624.780 1703.180 626.160 1713.785 ;
    END
  END col_event_rst_top_left<12>
  PIN col_event_rst_top_left<5>
    ANTENNAGATEAREA 4.032000 ;
    PORT
      LAYER met4 ;
        RECT 699.220 1703.180 700.600 1713.785 ;
    END
  END col_event_rst_top_left<5>
  PIN col_event_rst_top_left<23>
    ANTENNAGATEAREA 4.032000 ;
    PORT
      LAYER met4 ;
        RECT 483.220 1703.180 484.600 1713.785 ;
    END
  END col_event_rst_top_left<23>
  PIN col_event_rst_top_left<6>
    ANTENNAGATEAREA 4.032000 ;
    PORT
      LAYER met4 ;
        RECT 696.780 1703.180 698.160 1713.785 ;
    END
  END col_event_rst_top_left<6>
  PIN col_event_rst_top_left<11>
    ANTENNAGATEAREA 4.032000 ;
    PORT
      LAYER met4 ;
        RECT 627.220 1703.180 628.600 1713.785 ;
    END
  END col_event_rst_top_left<11>
  PIN array_col_top_left<7>
    ANTENNADIFFAREA 0.870000 ;
    PORT
      LAYER met4 ;
        RECT 677.520 1703.180 679.360 1713.785 ;
    END
  END array_col_top_left<7>
  PIN col_event_rst_top_left<18>
    ANTENNAGATEAREA 4.032000 ;
    PORT
      LAYER met4 ;
        RECT 552.780 1703.180 554.160 1713.785 ;
    END
  END col_event_rst_top_left<18>
  PIN col_event_rst_top_left<1>
    ANTENNAGATEAREA 4.032000 ;
    PORT
      LAYER met4 ;
        RECT 747.220 1703.180 748.600 1713.785 ;
    END
  END col_event_rst_top_left<1>
  PIN col_event_rst_top_left<31>
    ANTENNAGATEAREA 4.032000 ;
    PORT
      LAYER met4 ;
        RECT 387.220 1703.180 388.600 1713.785 ;
    END
  END col_event_rst_top_left<31>
  PIN array_col_top_left<18>
    ANTENNADIFFAREA 0.870000 ;
    PORT
      LAYER met4 ;
        RECT 550.020 1703.180 551.860 1713.785 ;
    END
  END array_col_top_left<18>
  PIN array_col_top_left<13>
    ANTENNADIFFAREA 0.870000 ;
    PORT
      LAYER met4 ;
        RECT 605.520 1703.180 607.360 1713.785 ;
    END
  END array_col_top_left<13>
  PIN array_col_top_left<10>
    ANTENNADIFFAREA 0.870000 ;
    PORT
      LAYER met4 ;
        RECT 646.020 1703.180 647.860 1713.785 ;
    END
  END array_col_top_left<10>
  PIN array_col_top_left<26>
    ANTENNADIFFAREA 0.870000 ;
    PORT
      LAYER met4 ;
        RECT 454.020 1703.180 455.860 1713.785 ;
    END
  END array_col_top_left<26>
  PIN array_col_top_left<8>
    ANTENNADIFFAREA 0.870000 ;
    PORT
      LAYER met4 ;
        RECT 670.020 1703.180 671.860 1713.785 ;
    END
  END array_col_top_left<8>
  PIN col_event_rst_top_left<27>
    ANTENNAGATEAREA 4.032000 ;
    PORT
      LAYER met4 ;
        RECT 435.220 1703.180 436.600 1713.785 ;
    END
  END col_event_rst_top_left<27>
  PIN col_event_rst_top_left<21>
    ANTENNAGATEAREA 4.032000 ;
    PORT
      LAYER met4 ;
        RECT 507.220 1703.180 508.600 1713.785 ;
    END
  END col_event_rst_top_left<21>
  PIN col_event_rst_top_left<15>
    ANTENNAGATEAREA 4.032000 ;
    PORT
      LAYER met4 ;
        RECT 579.220 1703.180 580.600 1713.785 ;
    END
  END col_event_rst_top_left<15>
  PIN col_event_rst_top_left<10>
    ANTENNAGATEAREA 4.032000 ;
    PORT
      LAYER met4 ;
        RECT 648.780 1703.180 650.160 1713.785 ;
    END
  END col_event_rst_top_left<10>
  PIN col_event_rst_top_left<9>
    ANTENNAGATEAREA 4.032000 ;
    PORT
      LAYER met4 ;
        RECT 651.220 1703.180 652.600 1713.785 ;
    END
  END col_event_rst_top_left<9>
  PIN col_event_rst_top_left<20>
    ANTENNAGATEAREA 4.032000 ;
    PORT
      LAYER met4 ;
        RECT 528.780 1703.180 530.160 1713.785 ;
    END
  END col_event_rst_top_left<20>
  PIN array_col_top_left<14>
    ANTENNADIFFAREA 0.870000 ;
    PORT
      LAYER met4 ;
        RECT 598.020 1703.180 599.860 1713.785 ;
    END
  END array_col_top_left<14>
  PIN col_event_rst_top_left<17>
    ANTENNAGATEAREA 4.032000 ;
    PORT
      LAYER met4 ;
        RECT 555.220 1703.180 556.600 1713.785 ;
    END
  END col_event_rst_top_left<17>
  PIN array_col_top_left<20>
    ANTENNADIFFAREA 0.870000 ;
    PORT
      LAYER met4 ;
        RECT 526.020 1703.180 527.860 1713.785 ;
    END
  END array_col_top_left<20>
  PIN array_col_top_left<2>
    ANTENNADIFFAREA 0.870000 ;
    PORT
      LAYER met4 ;
        RECT 742.020 1703.180 743.860 1713.785 ;
    END
  END array_col_top_left<2>
  PIN col_event_rst_top_left<24>
    ANTENNAGATEAREA 4.032000 ;
    PORT
      LAYER met4 ;
        RECT 480.780 1703.180 482.160 1713.785 ;
    END
  END col_event_rst_top_left<24>
  PIN col_event_rst_top_left<2>
    ANTENNAGATEAREA 4.032000 ;
    PORT
      LAYER met4 ;
        RECT 744.780 1703.180 746.160 1713.785 ;
    END
  END col_event_rst_top_left<2>
  PIN col_event_rst_top_left<14>
    ANTENNAGATEAREA 4.032000 ;
    PORT
      LAYER met4 ;
        RECT 600.780 1703.180 602.160 1713.785 ;
    END
  END col_event_rst_top_left<14>
  PIN array_col_top_left<21>
    ANTENNADIFFAREA 0.870000 ;
    PORT
      LAYER met4 ;
        RECT 509.520 1703.180 511.360 1713.785 ;
    END
  END array_col_top_left<21>
  PIN array_col_top_left<0>
    ANTENNADIFFAREA 0.870000 ;
    PORT
      LAYER met4 ;
        RECT 766.020 1703.180 767.860 1713.785 ;
    END
  END array_col_top_left<0>
  PIN col_event_rst_top_left<22>
    ANTENNAGATEAREA 4.032000 ;
    PORT
      LAYER met4 ;
        RECT 504.780 1703.180 506.160 1713.785 ;
    END
  END col_event_rst_top_left<22>
  PIN col_event_rst_top_left<13>
    ANTENNAGATEAREA 4.032000 ;
    PORT
      LAYER met4 ;
        RECT 603.220 1703.180 604.600 1713.785 ;
    END
  END col_event_rst_top_left<13>
  PIN array_col_top_left<28>
    ANTENNADIFFAREA 0.870000 ;
    PORT
      LAYER met4 ;
        RECT 430.020 1703.180 431.860 1713.785 ;
    END
  END array_col_top_left<28>
  PIN col_event_rst_top_left<29>
    ANTENNAGATEAREA 4.032000 ;
    PORT
      LAYER met4 ;
        RECT 411.220 1703.180 412.600 1713.785 ;
    END
  END col_event_rst_top_left<29>
  PIN col_event_rst_top_left<28>
    ANTENNAGATEAREA 4.032000 ;
    PORT
      LAYER met4 ;
        RECT 432.780 1703.180 434.160 1713.785 ;
    END
  END col_event_rst_top_left<28>
  PIN col_event_rst_top_left<3>
    ANTENNAGATEAREA 4.032000 ;
    PORT
      LAYER met4 ;
        RECT 723.220 1703.180 724.600 1713.785 ;
    END
  END col_event_rst_top_left<3>
  PIN col_event_rst_top_left<7>
    ANTENNAGATEAREA 4.032000 ;
    PORT
      LAYER met4 ;
        RECT 675.220 1703.180 676.600 1713.785 ;
    END
  END col_event_rst_top_left<7>
  PIN array_col_top_left<24>
    ANTENNADIFFAREA 0.870000 ;
    PORT
      LAYER met4 ;
        RECT 478.020 1703.180 479.860 1713.785 ;
    END
  END array_col_top_left<24>
  PIN array_col_top_left<15>
    ANTENNADIFFAREA 0.870000 ;
    PORT
      LAYER met4 ;
        RECT 581.520 1703.180 583.360 1713.785 ;
    END
  END array_col_top_left<15>
  PIN array_col_top_left<16>
    ANTENNADIFFAREA 0.870000 ;
    PORT
      LAYER met4 ;
        RECT 574.020 1703.180 575.860 1713.785 ;
    END
  END array_col_top_left<16>
  PIN col_event_rst_top_left<19>
    ANTENNAGATEAREA 4.032000 ;
    PORT
      LAYER met4 ;
        RECT 531.220 1703.180 532.600 1713.785 ;
    END
  END col_event_rst_top_left<19>
  PIN array_col_top_left<31>
    ANTENNADIFFAREA 0.870000 ;
    PORT
      LAYER met4 ;
        RECT 389.520 1703.180 391.360 1713.785 ;
    END
  END array_col_top_left<31>
  PIN array_col_top_left<12>
    ANTENNADIFFAREA 0.870000 ;
    PORT
      LAYER met4 ;
        RECT 622.020 1703.180 623.860 1713.785 ;
    END
  END array_col_top_left<12>
  PIN col_event_rst_top_left<16>
    ANTENNAGATEAREA 4.032000 ;
    PORT
      LAYER met4 ;
        RECT 576.780 1703.180 578.160 1713.785 ;
    END
  END col_event_rst_top_left<16>
  PIN col_event_rst_top_left<26>
    ANTENNAGATEAREA 4.032000 ;
    PORT
      LAYER met4 ;
        RECT 456.780 1703.180 458.160 1713.785 ;
    END
  END col_event_rst_top_left<26>
  PIN col_event_rst_top_left<25>
    ANTENNAGATEAREA 4.032000 ;
    PORT
      LAYER met4 ;
        RECT 459.220 1703.180 460.600 1713.785 ;
    END
  END col_event_rst_top_left<25>
  PIN array_col_top_left<1>
    ANTENNADIFFAREA 0.870000 ;
    PORT
      LAYER met4 ;
        RECT 749.520 1703.180 751.360 1713.785 ;
    END
  END array_col_top_left<1>
  PIN array_col_top_left<22>
    ANTENNADIFFAREA 0.870000 ;
    PORT
      LAYER met4 ;
        RECT 502.020 1703.180 503.860 1713.785 ;
    END
  END array_col_top_left<22>
  PIN array_col_top_left<3>
    ANTENNADIFFAREA 0.870000 ;
    PORT
      LAYER met4 ;
        RECT 725.520 1703.180 727.360 1713.785 ;
    END
  END array_col_top_left<3>
  PIN col_event_rst_top_left<0>
    ANTENNAGATEAREA 4.032000 ;
    PORT
      LAYER met4 ;
        RECT 768.780 1703.180 770.160 1713.785 ;
    END
  END col_event_rst_top_left<0>
  PIN col_event_rst_top_left<4>
    ANTENNAGATEAREA 4.032000 ;
    PORT
      LAYER met4 ;
        RECT 720.780 1703.180 722.160 1713.785 ;
    END
  END col_event_rst_top_left<4>
  PIN col_event_rst_top_left<8>
    ANTENNAGATEAREA 4.032000 ;
    PORT
      LAYER met4 ;
        RECT 672.780 1703.180 674.160 1713.785 ;
    END
  END col_event_rst_top_left<8>
  PIN array_col_top_left<23>
    ANTENNADIFFAREA 0.870000 ;
    PORT
      LAYER met4 ;
        RECT 485.520 1703.180 487.360 1713.785 ;
    END
  END array_col_top_left<23>
  PIN array_col_top_left<17>
    ANTENNADIFFAREA 0.870000 ;
    PORT
      LAYER met4 ;
        RECT 557.520 1703.180 559.360 1713.785 ;
    END
  END array_col_top_left<17>
  PIN col_event_rst_top_left<30>
    ANTENNAGATEAREA 4.032000 ;
    PORT
      LAYER met4 ;
        RECT 408.780 1703.180 410.160 1713.785 ;
    END
  END col_event_rst_top_left<30>
  PIN array_col_top_left<6>
    ANTENNADIFFAREA 0.870000 ;
    PORT
      LAYER met4 ;
        RECT 694.020 1703.180 695.860 1713.785 ;
    END
  END array_col_top_left<6>
  PIN array_col_top_left<29>
    ANTENNADIFFAREA 0.870000 ;
    PORT
      LAYER met4 ;
        RECT 413.520 1703.180 415.360 1713.785 ;
    END
  END array_col_top_left<29>
  PIN array_col_top_left<11>
    ANTENNADIFFAREA 0.870000 ;
    PORT
      LAYER met4 ;
        RECT 629.520 1703.180 631.360 1713.785 ;
    END
  END array_col_top_left<11>
  PIN array_col_top_left<9>
    ANTENNADIFFAREA 0.870000 ;
    PORT
      LAYER met4 ;
        RECT 653.520 1703.180 655.360 1713.785 ;
    END
  END array_col_top_left<9>
  PIN array_col_top_left<27>
    ANTENNADIFFAREA 0.870000 ;
    PORT
      LAYER met4 ;
        RECT 437.520 1703.180 439.360 1713.785 ;
    END
  END array_col_top_left<27>
  PIN array_col_top_left<5>
    ANTENNADIFFAREA 0.870000 ;
    PORT
      LAYER met4 ;
        RECT 701.520 1703.180 703.360 1713.785 ;
    END
  END array_col_top_left<5>
  PIN array_col_top_left<4>
    ANTENNADIFFAREA 0.870000 ;
    PORT
      LAYER met4 ;
        RECT 718.020 1703.180 719.860 1713.785 ;
    END
  END array_col_top_left<4>
  PIN array_col_top_left<19>
    ANTENNADIFFAREA 0.870000 ;
    PORT
      LAYER met4 ;
        RECT 533.520 1703.180 535.360 1713.785 ;
    END
  END array_col_top_left<19>
  PIN array_col_top_left<30>
    ANTENNADIFFAREA 0.870000 ;
    PORT
      LAYER met4 ;
        RECT 406.020 1703.180 407.860 1713.785 ;
    END
  END array_col_top_left<30>
  PIN array_col_top_left<35>
    ANTENNADIFFAREA 0.870000 ;
    PORT
      LAYER met4 ;
        RECT 341.520 1703.180 343.360 1713.785 ;
    END
  END array_col_top_left<35>
  PIN col_event_rst_top_left<61>
    ANTENNAGATEAREA 4.032000 ;
    PORT
      LAYER met4 ;
        RECT 27.220 1703.180 28.600 1713.785 ;
    END
  END col_event_rst_top_left<61>
  PIN col_event_rst_top_left<36>
    ANTENNAGATEAREA 4.032000 ;
    PORT
      LAYER met4 ;
        RECT 336.780 1703.180 338.160 1713.785 ;
    END
  END col_event_rst_top_left<36>
  PIN col_event_rst_top_left<40>
    ANTENNAGATEAREA 4.032000 ;
    PORT
      LAYER met4 ;
        RECT 288.780 1703.180 290.160 1713.785 ;
    END
  END col_event_rst_top_left<40>
  PIN array_col_top_left<38>
    ANTENNADIFFAREA 0.870000 ;
    PORT
      LAYER met4 ;
        RECT 310.020 1703.180 311.860 1713.785 ;
    END
  END array_col_top_left<38>
  PIN array_col_top_left<39>
    ANTENNADIFFAREA 0.870000 ;
    PORT
      LAYER met4 ;
        RECT 293.520 1703.180 295.360 1713.785 ;
    END
  END array_col_top_left<39>
  PIN array_col_top_left<40>
    ANTENNADIFFAREA 0.870000 ;
    PORT
      LAYER met4 ;
        RECT 286.020 1703.180 287.860 1713.785 ;
    END
  END array_col_top_left<40>
  PIN array_col_top_left<41>
    ANTENNADIFFAREA 0.870000 ;
    PORT
      LAYER met4 ;
        RECT 269.520 1703.180 271.360 1713.785 ;
    END
  END array_col_top_left<41>
  PIN array_col_top_left<63>
    ANTENNADIFFAREA 0.870000 ;
    PORT
      LAYER met4 ;
        RECT 5.520 1703.180 7.360 1713.785 ;
    END
  END array_col_top_left<63>
  PIN array_col_top_left<42>
    ANTENNADIFFAREA 0.870000 ;
    PORT
      LAYER met4 ;
        RECT 262.020 1703.180 263.860 1713.785 ;
    END
  END array_col_top_left<42>
  PIN array_col_top_left<43>
    ANTENNADIFFAREA 0.870000 ;
    PORT
      LAYER met4 ;
        RECT 245.520 1703.180 247.360 1713.785 ;
    END
  END array_col_top_left<43>
  PIN array_col_top_left<44>
    ANTENNADIFFAREA 0.870000 ;
    PORT
      LAYER met4 ;
        RECT 238.020 1703.180 239.860 1713.785 ;
    END
  END array_col_top_left<44>
  PIN col_event_rst_top_left<43>
    ANTENNAGATEAREA 4.032000 ;
    PORT
      LAYER met4 ;
        RECT 243.220 1703.180 244.600 1713.785 ;
    END
  END col_event_rst_top_left<43>
  PIN array_col_top_left<45>
    ANTENNADIFFAREA 0.870000 ;
    PORT
      LAYER met4 ;
        RECT 221.520 1703.180 223.360 1713.785 ;
    END
  END array_col_top_left<45>
  PIN array_col_top_left<46>
    ANTENNADIFFAREA 0.870000 ;
    PORT
      LAYER met4 ;
        RECT 214.020 1703.180 215.860 1713.785 ;
    END
  END array_col_top_left<46>
  PIN col_event_rst_top_left<44>
    ANTENNAGATEAREA 4.032000 ;
    PORT
      LAYER met4 ;
        RECT 240.780 1703.180 242.160 1713.785 ;
    END
  END col_event_rst_top_left<44>
  PIN col_event_rst_top_left<59>
    ANTENNAGATEAREA 4.032000 ;
    PORT
      LAYER met4 ;
        RECT 51.220 1703.180 52.600 1713.785 ;
    END
  END col_event_rst_top_left<59>
  PIN array_col_top_left<47>
    ANTENNADIFFAREA 0.870000 ;
    PORT
      LAYER met4 ;
        RECT 197.520 1703.180 199.360 1713.785 ;
    END
  END array_col_top_left<47>
  PIN col_event_rst_top_left<58>
    ANTENNAGATEAREA 4.032000 ;
    PORT
      LAYER met4 ;
        RECT 72.780 1703.180 74.160 1713.785 ;
    END
  END col_event_rst_top_left<58>
  PIN array_col_top_left<48>
    ANTENNADIFFAREA 0.870000 ;
    PORT
      LAYER met4 ;
        RECT 190.020 1703.180 191.860 1713.785 ;
    END
  END array_col_top_left<48>
  PIN array_col_top_left<49>
    ANTENNADIFFAREA 0.870000 ;
    PORT
      LAYER met4 ;
        RECT 173.520 1703.180 175.360 1713.785 ;
    END
  END array_col_top_left<49>
  PIN col_event_rst_top_left<63>
    ANTENNAGATEAREA 4.032000 ;
    PORT
      LAYER met4 ;
        RECT 3.220 1703.180 4.600 1713.785 ;
    END
  END col_event_rst_top_left<63>
  PIN col_event_rst_top_left<62>
    ANTENNAGATEAREA 4.032000 ;
    PORT
      LAYER met4 ;
        RECT 24.780 1703.180 26.160 1713.785 ;
    END
  END col_event_rst_top_left<62>
  PIN col_event_rst_top_left<42>
    ANTENNAGATEAREA 4.032000 ;
    PORT
      LAYER met4 ;
        RECT 264.780 1703.180 266.160 1713.785 ;
    END
  END col_event_rst_top_left<42>
  PIN array_col_top_left<50>
    ANTENNADIFFAREA 0.870000 ;
    PORT
      LAYER met4 ;
        RECT 166.020 1703.180 167.860 1713.785 ;
    END
  END array_col_top_left<50>
  PIN col_event_rst_top_left<37>
    ANTENNAGATEAREA 4.032000 ;
    PORT
      LAYER met4 ;
        RECT 315.220 1703.180 316.600 1713.785 ;
    END
  END col_event_rst_top_left<37>
  PIN col_event_rst_top_left<35>
    ANTENNAGATEAREA 4.032000 ;
    PORT
      LAYER met4 ;
        RECT 339.220 1703.180 340.600 1713.785 ;
    END
  END col_event_rst_top_left<35>
  PIN array_col_top_left<37>
    ANTENNADIFFAREA 0.870000 ;
    PORT
      LAYER met4 ;
        RECT 317.520 1703.180 319.360 1713.785 ;
    END
  END array_col_top_left<37>
  PIN col_event_rst_top_left<41>
    ANTENNAGATEAREA 4.032000 ;
    PORT
      LAYER met4 ;
        RECT 267.220 1703.180 268.600 1713.785 ;
    END
  END col_event_rst_top_left<41>
  PIN col_event_rst_top_left<38>
    ANTENNAGATEAREA 4.032000 ;
    PORT
      LAYER met4 ;
        RECT 312.780 1703.180 314.160 1713.785 ;
    END
  END col_event_rst_top_left<38>
  PIN col_event_rst_top_left<54>
    ANTENNAGATEAREA 4.032000 ;
    PORT
      LAYER met4 ;
        RECT 120.780 1703.180 122.160 1713.785 ;
    END
  END col_event_rst_top_left<54>
  PIN col_event_rst_top_left<48>
    ANTENNAGATEAREA 4.032000 ;
    PORT
      LAYER met4 ;
        RECT 192.780 1703.180 194.160 1713.785 ;
    END
  END col_event_rst_top_left<48>
  PIN array_col_top_left<51>
    ANTENNADIFFAREA 0.870000 ;
    PORT
      LAYER met4 ;
        RECT 149.520 1703.180 151.360 1713.785 ;
    END
  END array_col_top_left<51>
  PIN array_col_top_left<52>
    ANTENNADIFFAREA 0.870000 ;
    PORT
      LAYER met4 ;
        RECT 142.020 1703.180 143.860 1713.785 ;
    END
  END array_col_top_left<52>
  PIN array_col_top_left<53>
    ANTENNADIFFAREA 0.870000 ;
    PORT
      LAYER met4 ;
        RECT 125.520 1703.180 127.360 1713.785 ;
    END
  END array_col_top_left<53>
  PIN array_col_top_left<54>
    ANTENNADIFFAREA 0.870000 ;
    PORT
      LAYER met4 ;
        RECT 118.020 1703.180 119.860 1713.785 ;
    END
  END array_col_top_left<54>
  PIN array_col_top_left<55>
    ANTENNADIFFAREA 0.870000 ;
    PORT
      LAYER met4 ;
        RECT 101.520 1703.180 103.360 1713.785 ;
    END
  END array_col_top_left<55>
  PIN array_col_top_left<56>
    ANTENNADIFFAREA 0.870000 ;
    PORT
      LAYER met4 ;
        RECT 94.020 1703.180 95.860 1713.785 ;
    END
  END array_col_top_left<56>
  PIN array_col_top_left<57>
    ANTENNADIFFAREA 0.870000 ;
    PORT
      LAYER met4 ;
        RECT 77.520 1703.180 79.360 1713.785 ;
    END
  END array_col_top_left<57>
  PIN array_col_top_left<58>
    ANTENNADIFFAREA 0.870000 ;
    PORT
      LAYER met4 ;
        RECT 70.020 1703.180 71.860 1713.785 ;
    END
  END array_col_top_left<58>
  PIN array_col_top_left<59>
    ANTENNADIFFAREA 0.870000 ;
    PORT
      LAYER met4 ;
        RECT 53.520 1703.180 55.360 1713.785 ;
    END
  END array_col_top_left<59>
  PIN array_col_top_left<60>
    ANTENNADIFFAREA 0.870000 ;
    PORT
      LAYER met4 ;
        RECT 46.020 1703.180 47.860 1713.785 ;
    END
  END array_col_top_left<60>
  PIN array_col_top_left<61>
    ANTENNADIFFAREA 0.870000 ;
    PORT
      LAYER met4 ;
        RECT 29.520 1703.180 31.360 1713.785 ;
    END
  END array_col_top_left<61>
  PIN array_col_top_left<62>
    ANTENNADIFFAREA 0.870000 ;
    PORT
      LAYER met4 ;
        RECT 22.020 1703.180 23.860 1713.785 ;
    END
  END array_col_top_left<62>
  PIN col_event_rst_top_left<46>
    ANTENNAGATEAREA 4.032000 ;
    PORT
      LAYER met4 ;
        RECT 216.780 1703.180 218.160 1713.785 ;
    END
  END col_event_rst_top_left<46>
  PIN col_event_rst_top_left<57>
    ANTENNAGATEAREA 4.032000 ;
    PORT
      LAYER met4 ;
        RECT 75.220 1703.180 76.600 1713.785 ;
    END
  END col_event_rst_top_left<57>
  PIN col_event_rst_top_left<51>
    ANTENNAGATEAREA 4.032000 ;
    PORT
      LAYER met4 ;
        RECT 147.220 1703.180 148.600 1713.785 ;
    END
  END col_event_rst_top_left<51>
  PIN col_event_rst_top_left<49>
    ANTENNAGATEAREA 4.032000 ;
    PORT
      LAYER met4 ;
        RECT 171.220 1703.180 172.600 1713.785 ;
    END
  END col_event_rst_top_left<49>
  PIN array_col_top_left<36>
    ANTENNADIFFAREA 0.870000 ;
    PORT
      LAYER met4 ;
        RECT 334.020 1703.180 335.860 1713.785 ;
    END
  END array_col_top_left<36>
  PIN col_event_rst_top_left<55>
    ANTENNAGATEAREA 4.032000 ;
    PORT
      LAYER met4 ;
        RECT 99.220 1703.180 100.600 1713.785 ;
    END
  END col_event_rst_top_left<55>
  PIN col_event_rst_top_left<56>
    ANTENNAGATEAREA 4.032000 ;
    PORT
      LAYER met4 ;
        RECT 96.780 1703.180 98.160 1713.785 ;
    END
  END col_event_rst_top_left<56>
  PIN col_event_rst_top_left<45>
    ANTENNAGATEAREA 4.032000 ;
    PORT
      LAYER met4 ;
        RECT 219.220 1703.180 220.600 1713.785 ;
    END
  END col_event_rst_top_left<45>
  PIN col_event_rst_top_left<47>
    ANTENNAGATEAREA 4.032000 ;
    PORT
      LAYER met4 ;
        RECT 195.220 1703.180 196.600 1713.785 ;
    END
  END col_event_rst_top_left<47>
  PIN col_event_rst_top_left<39>
    ANTENNAGATEAREA 4.032000 ;
    PORT
      LAYER met4 ;
        RECT 291.220 1703.180 292.600 1713.785 ;
    END
  END col_event_rst_top_left<39>
  PIN col_event_rst_top_left<53>
    ANTENNAGATEAREA 4.032000 ;
    PORT
      LAYER met4 ;
        RECT 123.220 1703.180 124.600 1713.785 ;
    END
  END col_event_rst_top_left<53>
  PIN col_event_rst_top_left<52>
    ANTENNAGATEAREA 4.032000 ;
    PORT
      LAYER met4 ;
        RECT 144.780 1703.180 146.160 1713.785 ;
    END
  END col_event_rst_top_left<52>
  PIN col_event_rst_top_left<60>
    ANTENNAGATEAREA 4.032000 ;
    PORT
      LAYER met4 ;
        RECT 48.780 1703.180 50.160 1713.785 ;
    END
  END col_event_rst_top_left<60>
  PIN col_event_rst_top_left<50>
    ANTENNAGATEAREA 4.032000 ;
    PORT
      LAYER met4 ;
        RECT 168.780 1703.180 170.160 1713.785 ;
    END
  END col_event_rst_top_left<50>
  PIN col_event_rst_bot_left<59>
    ANTENNAGATEAREA 4.032000 ;
    PORT
      LAYER met4 ;
        RECT 51.220 -75.665 52.600 0.375 ;
    END
  END col_event_rst_bot_left<59>
  PIN col_event_rst_bot_left<58>
    ANTENNAGATEAREA 4.032000 ;
    PORT
      LAYER met4 ;
        RECT 72.780 -75.665 74.160 0.375 ;
    END
  END col_event_rst_bot_left<58>
  PIN col_event_rst_bot_left<57>
    ANTENNAGATEAREA 4.032000 ;
    PORT
      LAYER met4 ;
        RECT 75.220 -75.665 76.600 0.375 ;
    END
  END col_event_rst_bot_left<57>
  PIN col_event_rst_bot_left<56>
    ANTENNAGATEAREA 4.032000 ;
    PORT
      LAYER met4 ;
        RECT 96.780 -75.665 98.160 0.375 ;
    END
  END col_event_rst_bot_left<56>
  PIN col_event_rst_bot_left<55>
    ANTENNAGATEAREA 4.032000 ;
    PORT
      LAYER met4 ;
        RECT 99.220 -75.665 100.600 0.375 ;
    END
  END col_event_rst_bot_left<55>
  PIN col_event_rst_bot_left<54>
    ANTENNAGATEAREA 4.032000 ;
    PORT
      LAYER met4 ;
        RECT 120.780 -75.665 122.160 0.375 ;
    END
  END col_event_rst_bot_left<54>
  PIN col_event_rst_bot_left<53>
    ANTENNAGATEAREA 4.032000 ;
    PORT
      LAYER met4 ;
        RECT 123.220 -75.665 124.600 0.375 ;
    END
  END col_event_rst_bot_left<53>
  PIN col_event_rst_bot_left<52>
    ANTENNAGATEAREA 4.032000 ;
    PORT
      LAYER met4 ;
        RECT 144.780 -75.665 146.160 0.375 ;
    END
  END col_event_rst_bot_left<52>
  PIN col_event_rst_bot_left<51>
    ANTENNAGATEAREA 4.032000 ;
    PORT
      LAYER met4 ;
        RECT 147.220 -75.665 148.600 0.375 ;
    END
  END col_event_rst_bot_left<51>
  PIN col_event_rst_bot_left<50>
    ANTENNAGATEAREA 4.032000 ;
    PORT
      LAYER met4 ;
        RECT 168.780 -75.665 170.160 0.375 ;
    END
  END col_event_rst_bot_left<50>
  PIN col_event_rst_bot_left<49>
    ANTENNAGATEAREA 4.032000 ;
    PORT
      LAYER met4 ;
        RECT 171.220 -75.665 172.600 0.375 ;
    END
  END col_event_rst_bot_left<49>
  PIN col_event_rst_bot_left<48>
    ANTENNAGATEAREA 4.032000 ;
    PORT
      LAYER met4 ;
        RECT 192.780 -75.665 194.160 0.375 ;
    END
  END col_event_rst_bot_left<48>
  PIN col_event_rst_bot_left<47>
    ANTENNAGATEAREA 4.032000 ;
    PORT
      LAYER met4 ;
        RECT 195.220 -75.665 196.600 0.375 ;
    END
  END col_event_rst_bot_left<47>
  PIN col_event_rst_bot_left<46>
    ANTENNAGATEAREA 4.032000 ;
    PORT
      LAYER met4 ;
        RECT 216.780 -75.665 218.160 0.375 ;
    END
  END col_event_rst_bot_left<46>
  PIN col_event_rst_bot_left<45>
    ANTENNAGATEAREA 4.032000 ;
    PORT
      LAYER met4 ;
        RECT 219.220 -75.665 220.600 0.375 ;
    END
  END col_event_rst_bot_left<45>
  PIN col_event_rst_bot_left<44>
    ANTENNAGATEAREA 4.032000 ;
    PORT
      LAYER met4 ;
        RECT 240.780 -75.665 242.160 0.375 ;
    END
  END col_event_rst_bot_left<44>
  PIN col_event_rst_bot_left<43>
    ANTENNAGATEAREA 4.032000 ;
    PORT
      LAYER met4 ;
        RECT 243.220 -75.665 244.600 0.375 ;
    END
  END col_event_rst_bot_left<43>
  PIN col_event_rst_bot_left<42>
    ANTENNAGATEAREA 4.032000 ;
    PORT
      LAYER met4 ;
        RECT 264.780 -75.665 266.160 0.375 ;
    END
  END col_event_rst_bot_left<42>
  PIN col_event_rst_bot_left<41>
    ANTENNAGATEAREA 4.032000 ;
    PORT
      LAYER met4 ;
        RECT 267.220 -75.665 268.600 0.375 ;
    END
  END col_event_rst_bot_left<41>
  PIN col_event_rst_bot_left<40>
    ANTENNAGATEAREA 4.032000 ;
    PORT
      LAYER met4 ;
        RECT 288.780 -75.665 290.160 0.375 ;
    END
  END col_event_rst_bot_left<40>
  PIN col_event_rst_bot_left<39>
    ANTENNAGATEAREA 4.032000 ;
    PORT
      LAYER met4 ;
        RECT 291.220 -75.665 292.600 0.375 ;
    END
  END col_event_rst_bot_left<39>
  PIN col_event_rst_bot_left<38>
    ANTENNAGATEAREA 4.032000 ;
    PORT
      LAYER met4 ;
        RECT 312.780 -75.665 314.160 0.375 ;
    END
  END col_event_rst_bot_left<38>
  PIN col_event_rst_bot_left<37>
    ANTENNAGATEAREA 4.032000 ;
    PORT
      LAYER met4 ;
        RECT 315.220 -75.665 316.600 0.375 ;
    END
  END col_event_rst_bot_left<37>
  PIN col_event_rst_bot_left<36>
    ANTENNAGATEAREA 4.032000 ;
    PORT
      LAYER met4 ;
        RECT 336.780 -75.665 338.160 0.375 ;
    END
  END col_event_rst_bot_left<36>
  PIN col_event_rst_bot_left<35>
    ANTENNAGATEAREA 4.032000 ;
    PORT
      LAYER met4 ;
        RECT 339.220 -75.665 340.600 0.375 ;
    END
  END col_event_rst_bot_left<35>
  PIN col_event_rst_bot_left<63>
    ANTENNAGATEAREA 4.032000 ;
    PORT
      LAYER met4 ;
        RECT 3.220 -75.665 4.600 0.375 ;
    END
  END col_event_rst_bot_left<63>
  PIN col_event_rst_bot_left<62>
    ANTENNAGATEAREA 4.032000 ;
    PORT
      LAYER met4 ;
        RECT 24.780 -75.665 26.160 0.375 ;
    END
  END col_event_rst_bot_left<62>
  PIN col_event_rst_bot_left<61>
    ANTENNAGATEAREA 4.032000 ;
    PORT
      LAYER met4 ;
        RECT 27.220 -75.665 28.600 0.375 ;
    END
  END col_event_rst_bot_left<61>
  PIN col_event_rst_bot_left<60>
    ANTENNAGATEAREA 4.032000 ;
    PORT
      LAYER met4 ;
        RECT 48.780 -75.665 50.160 0.375 ;
    END
  END col_event_rst_bot_left<60>
  PIN array_col_bot_left<55>
    ANTENNADIFFAREA 0.870000 ;
    PORT
      LAYER met4 ;
        RECT 101.520 -75.665 103.360 0.375 ;
    END
  END array_col_bot_left<55>
  PIN array_col_bot_left<42>
    ANTENNADIFFAREA 0.870000 ;
    PORT
      LAYER met4 ;
        RECT 262.020 -75.665 263.860 0.375 ;
    END
  END array_col_bot_left<42>
  PIN array_col_bot_left<41>
    ANTENNADIFFAREA 0.870000 ;
    PORT
      LAYER met4 ;
        RECT 269.520 -75.665 271.360 0.375 ;
    END
  END array_col_bot_left<41>
  PIN array_col_bot_left<40>
    ANTENNADIFFAREA 0.870000 ;
    PORT
      LAYER met4 ;
        RECT 286.020 -75.665 287.860 0.375 ;
    END
  END array_col_bot_left<40>
  PIN array_col_bot_left<43>
    ANTENNADIFFAREA 0.870000 ;
    PORT
      LAYER met4 ;
        RECT 245.520 -75.665 247.360 0.375 ;
    END
  END array_col_bot_left<43>
  PIN array_col_bot_left<60>
    ANTENNADIFFAREA 0.870000 ;
    PORT
      LAYER met4 ;
        RECT 46.020 -75.665 47.860 0.375 ;
    END
  END array_col_bot_left<60>
  PIN array_col_bot_left<45>
    ANTENNADIFFAREA 0.870000 ;
    PORT
      LAYER met4 ;
        RECT 221.520 -75.665 223.360 0.375 ;
    END
  END array_col_bot_left<45>
  PIN array_col_bot_left<44>
    ANTENNADIFFAREA 0.870000 ;
    PORT
      LAYER met4 ;
        RECT 238.020 -75.665 239.860 0.375 ;
    END
  END array_col_bot_left<44>
  PIN array_col_bot_left<62>
    ANTENNADIFFAREA 0.870000 ;
    PORT
      LAYER met4 ;
        RECT 22.020 -75.665 23.860 0.375 ;
    END
  END array_col_bot_left<62>
  PIN array_col_bot_left<58>
    ANTENNADIFFAREA 0.870000 ;
    PORT
      LAYER met4 ;
        RECT 70.020 -75.665 71.860 0.375 ;
    END
  END array_col_bot_left<58>
  PIN array_col_bot_left<54>
    ANTENNADIFFAREA 0.870000 ;
    PORT
      LAYER met4 ;
        RECT 118.020 -75.665 119.860 0.375 ;
    END
  END array_col_bot_left<54>
  PIN array_col_bot_left<53>
    ANTENNADIFFAREA 0.870000 ;
    PORT
      LAYER met4 ;
        RECT 125.520 -75.665 127.360 0.375 ;
    END
  END array_col_bot_left<53>
  PIN array_col_bot_left<50>
    ANTENNADIFFAREA 0.870000 ;
    PORT
      LAYER met4 ;
        RECT 166.020 -75.665 167.860 0.375 ;
    END
  END array_col_bot_left<50>
  PIN array_col_bot_left<49>
    ANTENNADIFFAREA 0.870000 ;
    PORT
      LAYER met4 ;
        RECT 173.520 -75.665 175.360 0.375 ;
    END
  END array_col_bot_left<49>
  PIN array_col_bot_left<37>
    ANTENNADIFFAREA 0.870000 ;
    PORT
      LAYER met4 ;
        RECT 317.520 -75.665 319.360 0.375 ;
    END
  END array_col_bot_left<37>
  PIN array_col_bot_left<36>
    ANTENNADIFFAREA 0.870000 ;
    PORT
      LAYER met4 ;
        RECT 334.020 -75.665 335.860 0.375 ;
    END
  END array_col_bot_left<36>
  PIN array_col_bot_left<61>
    ANTENNADIFFAREA 0.870000 ;
    PORT
      LAYER met4 ;
        RECT 29.520 -75.665 31.360 0.375 ;
    END
  END array_col_bot_left<61>
  PIN array_col_bot_left<57>
    ANTENNADIFFAREA 0.870000 ;
    PORT
      LAYER met4 ;
        RECT 77.520 -75.665 79.360 0.375 ;
    END
  END array_col_bot_left<57>
  PIN array_col_bot_left<56>
    ANTENNADIFFAREA 0.870000 ;
    PORT
      LAYER met4 ;
        RECT 94.020 -75.665 95.860 0.375 ;
    END
  END array_col_bot_left<56>
  PIN array_col_bot_left<52>
    ANTENNADIFFAREA 0.870000 ;
    PORT
      LAYER met4 ;
        RECT 142.020 -75.665 143.860 0.375 ;
    END
  END array_col_bot_left<52>
  PIN array_col_bot_left<51>
    ANTENNADIFFAREA 0.870000 ;
    PORT
      LAYER met4 ;
        RECT 149.520 -75.665 151.360 0.375 ;
    END
  END array_col_bot_left<51>
  PIN array_col_bot_left<48>
    ANTENNADIFFAREA 0.870000 ;
    PORT
      LAYER met4 ;
        RECT 190.020 -75.665 191.860 0.375 ;
    END
  END array_col_bot_left<48>
  PIN array_col_bot_left<47>
    ANTENNADIFFAREA 0.870000 ;
    PORT
      LAYER met4 ;
        RECT 197.520 -75.665 199.360 0.375 ;
    END
  END array_col_bot_left<47>
  PIN array_col_bot_left<46>
    ANTENNADIFFAREA 0.870000 ;
    PORT
      LAYER met4 ;
        RECT 214.020 -75.665 215.860 0.375 ;
    END
  END array_col_bot_left<46>
  PIN array_col_bot_left<63>
    ANTENNADIFFAREA 0.870000 ;
    PORT
      LAYER met4 ;
        RECT 5.520 -75.665 7.360 0.375 ;
    END
  END array_col_bot_left<63>
  PIN array_col_bot_left<39>
    ANTENNADIFFAREA 0.870000 ;
    PORT
      LAYER met4 ;
        RECT 293.520 -75.665 295.360 0.375 ;
    END
  END array_col_bot_left<39>
  PIN array_col_bot_left<38>
    ANTENNADIFFAREA 0.870000 ;
    PORT
      LAYER met4 ;
        RECT 310.020 -75.665 311.860 0.375 ;
    END
  END array_col_bot_left<38>
  PIN array_col_bot_left<35>
    ANTENNADIFFAREA 0.870000 ;
    PORT
      LAYER met4 ;
        RECT 341.520 -75.665 343.360 0.375 ;
    END
  END array_col_bot_left<35>
  PIN array_col_bot_left<59>
    ANTENNADIFFAREA 0.870000 ;
    PORT
      LAYER met4 ;
        RECT 53.520 -75.665 55.360 0.375 ;
    END
  END array_col_bot_left<59>
  PIN col_event_rst_bot_left<0>
    ANTENNAGATEAREA 4.032000 ;
    PORT
      LAYER met4 ;
        RECT 768.780 -75.665 770.160 0.375 ;
    END
  END col_event_rst_bot_left<0>
  PIN col_event_rst_bot_left<34>
    ANTENNAGATEAREA 4.032000 ;
    PORT
      LAYER met4 ;
        RECT 360.780 -75.665 362.160 0.375 ;
    END
  END col_event_rst_bot_left<34>
  PIN col_event_rst_bot_left<33>
    ANTENNAGATEAREA 4.032000 ;
    PORT
      LAYER met4 ;
        RECT 363.220 -75.665 364.600 0.375 ;
    END
  END col_event_rst_bot_left<33>
  PIN col_event_rst_bot_left<32>
    ANTENNAGATEAREA 4.032000 ;
    PORT
      LAYER met4 ;
        RECT 384.780 -75.665 386.160 0.375 ;
    END
  END col_event_rst_bot_left<32>
  PIN col_event_rst_bot_left<31>
    ANTENNAGATEAREA 4.032000 ;
    PORT
      LAYER met4 ;
        RECT 387.220 -75.665 388.600 0.375 ;
    END
  END col_event_rst_bot_left<31>
  PIN col_event_rst_bot_left<30>
    ANTENNAGATEAREA 4.032000 ;
    PORT
      LAYER met4 ;
        RECT 408.780 -75.665 410.160 0.375 ;
    END
  END col_event_rst_bot_left<30>
  PIN col_event_rst_bot_left<29>
    ANTENNAGATEAREA 4.032000 ;
    PORT
      LAYER met4 ;
        RECT 411.220 -75.665 412.600 0.375 ;
    END
  END col_event_rst_bot_left<29>
  PIN col_event_rst_bot_left<28>
    ANTENNAGATEAREA 4.032000 ;
    PORT
      LAYER met4 ;
        RECT 432.780 -75.665 434.160 0.375 ;
    END
  END col_event_rst_bot_left<28>
  PIN col_event_rst_bot_left<27>
    ANTENNAGATEAREA 4.032000 ;
    PORT
      LAYER met4 ;
        RECT 435.220 -75.665 436.600 0.375 ;
    END
  END col_event_rst_bot_left<27>
  PIN col_event_rst_bot_left<26>
    ANTENNAGATEAREA 4.032000 ;
    PORT
      LAYER met4 ;
        RECT 456.780 -75.665 458.160 0.375 ;
    END
  END col_event_rst_bot_left<26>
  PIN array_col_bot_left<20>
    ANTENNADIFFAREA 0.870000 ;
    PORT
      LAYER met4 ;
        RECT 526.020 -75.665 527.860 0.375 ;
    END
  END array_col_bot_left<20>
  PIN array_col_bot_left<23>
    ANTENNADIFFAREA 0.870000 ;
    PORT
      LAYER met4 ;
        RECT 485.520 -75.665 487.360 0.375 ;
    END
  END array_col_bot_left<23>
  PIN array_col_bot_left<31>
    ANTENNADIFFAREA 0.870000 ;
    PORT
      LAYER met4 ;
        RECT 389.520 -75.665 391.360 0.375 ;
    END
  END array_col_bot_left<31>
  PIN col_event_rst_bot_left<25>
    ANTENNAGATEAREA 4.032000 ;
    PORT
      LAYER met4 ;
        RECT 459.220 -75.665 460.600 0.375 ;
    END
  END col_event_rst_bot_left<25>
  PIN col_event_rst_bot_left<24>
    ANTENNAGATEAREA 4.032000 ;
    PORT
      LAYER met4 ;
        RECT 480.780 -75.665 482.160 0.375 ;
    END
  END col_event_rst_bot_left<24>
  PIN array_col_bot_left<21>
    ANTENNADIFFAREA 0.870000 ;
    PORT
      LAYER met4 ;
        RECT 509.520 -75.665 511.360 0.375 ;
    END
  END array_col_bot_left<21>
  PIN array_col_bot_left<22>
    ANTENNADIFFAREA 0.870000 ;
    PORT
      LAYER met4 ;
        RECT 502.020 -75.665 503.860 0.375 ;
    END
  END array_col_bot_left<22>
  PIN array_col_bot_left<16>
    ANTENNADIFFAREA 0.870000 ;
    PORT
      LAYER met4 ;
        RECT 574.020 -75.665 575.860 0.375 ;
    END
  END array_col_bot_left<16>
  PIN col_event_rst_bot_left<23>
    ANTENNAGATEAREA 4.032000 ;
    PORT
      LAYER met4 ;
        RECT 483.220 -75.665 484.600 0.375 ;
    END
  END col_event_rst_bot_left<23>
  PIN array_col_bot_left<32>
    ANTENNADIFFAREA 0.870000 ;
    PORT
      LAYER met4 ;
        RECT 382.020 -75.665 383.860 0.375 ;
    END
  END array_col_bot_left<32>
  PIN array_col_bot_left<7>
    ANTENNADIFFAREA 0.870000 ;
    PORT
      LAYER met4 ;
        RECT 677.520 -75.665 679.360 0.375 ;
    END
  END array_col_bot_left<7>
  PIN array_col_bot_left<0>
    ANTENNADIFFAREA 0.870000 ;
    PORT
      LAYER met4 ;
        RECT 766.020 -75.665 767.860 0.375 ;
    END
  END array_col_bot_left<0>
  PIN col_event_rst_bot_left<22>
    ANTENNAGATEAREA 4.032000 ;
    PORT
      LAYER met4 ;
        RECT 504.780 -75.665 506.160 0.375 ;
    END
  END col_event_rst_bot_left<22>
  PIN col_event_rst_bot_left<21>
    ANTENNAGATEAREA 4.032000 ;
    PORT
      LAYER met4 ;
        RECT 507.220 -75.665 508.600 0.375 ;
    END
  END col_event_rst_bot_left<21>
  PIN array_col_bot_left<15>
    ANTENNADIFFAREA 0.870000 ;
    PORT
      LAYER met4 ;
        RECT 581.520 -75.665 583.360 0.375 ;
    END
  END array_col_bot_left<15>
  PIN array_col_bot_left<14>
    ANTENNADIFFAREA 0.870000 ;
    PORT
      LAYER met4 ;
        RECT 598.020 -75.665 599.860 0.375 ;
    END
  END array_col_bot_left<14>
  PIN array_col_bot_left<5>
    ANTENNADIFFAREA 0.870000 ;
    PORT
      LAYER met4 ;
        RECT 701.520 -75.665 703.360 0.375 ;
    END
  END array_col_bot_left<5>
  PIN array_col_bot_left<4>
    ANTENNADIFFAREA 0.870000 ;
    PORT
      LAYER met4 ;
        RECT 718.020 -75.665 719.860 0.375 ;
    END
  END array_col_bot_left<4>
  PIN array_col_bot_left<30>
    ANTENNADIFFAREA 0.870000 ;
    PORT
      LAYER met4 ;
        RECT 406.020 -75.665 407.860 0.375 ;
    END
  END array_col_bot_left<30>
  PIN array_col_bot_left<33>
    ANTENNADIFFAREA 0.870000 ;
    PORT
      LAYER met4 ;
        RECT 365.520 -75.665 367.360 0.375 ;
    END
  END array_col_bot_left<33>
  PIN array_col_bot_left<26>
    ANTENNADIFFAREA 0.870000 ;
    PORT
      LAYER met4 ;
        RECT 454.020 -75.665 455.860 0.375 ;
    END
  END array_col_bot_left<26>
  PIN col_event_rst_bot_left<20>
    ANTENNAGATEAREA 4.032000 ;
    PORT
      LAYER met4 ;
        RECT 528.780 -75.665 530.160 0.375 ;
    END
  END col_event_rst_bot_left<20>
  PIN array_col_bot_left<2>
    ANTENNADIFFAREA 0.870000 ;
    PORT
      LAYER met4 ;
        RECT 742.020 -75.665 743.860 0.375 ;
    END
  END array_col_bot_left<2>
  PIN array_col_bot_left<3>
    ANTENNADIFFAREA 0.870000 ;
    PORT
      LAYER met4 ;
        RECT 725.520 -75.665 727.360 0.375 ;
    END
  END array_col_bot_left<3>
  PIN col_event_rst_bot_left<19>
    ANTENNAGATEAREA 4.032000 ;
    PORT
      LAYER met4 ;
        RECT 531.220 -75.665 532.600 0.375 ;
    END
  END col_event_rst_bot_left<19>
  PIN col_event_rst_bot_left<18>
    ANTENNAGATEAREA 4.032000 ;
    PORT
      LAYER met4 ;
        RECT 552.780 -75.665 554.160 0.375 ;
    END
  END col_event_rst_bot_left<18>
  PIN col_event_rst_bot_left<17>
    ANTENNAGATEAREA 4.032000 ;
    PORT
      LAYER met4 ;
        RECT 555.220 -75.665 556.600 0.375 ;
    END
  END col_event_rst_bot_left<17>
  PIN col_event_rst_bot_left<16>
    ANTENNAGATEAREA 4.032000 ;
    PORT
      LAYER met4 ;
        RECT 576.780 -75.665 578.160 0.375 ;
    END
  END col_event_rst_bot_left<16>
  PIN array_col_bot_left<10>
    ANTENNADIFFAREA 0.870000 ;
    PORT
      LAYER met4 ;
        RECT 646.020 -75.665 647.860 0.375 ;
    END
  END array_col_bot_left<10>
  PIN array_col_bot_left<11>
    ANTENNADIFFAREA 0.870000 ;
    PORT
      LAYER met4 ;
        RECT 629.520 -75.665 631.360 0.375 ;
    END
  END array_col_bot_left<11>
  PIN array_col_bot_left<6>
    ANTENNADIFFAREA 0.870000 ;
    PORT
      LAYER met4 ;
        RECT 694.020 -75.665 695.860 0.375 ;
    END
  END array_col_bot_left<6>
  PIN col_event_rst_bot_left<15>
    ANTENNAGATEAREA 4.032000 ;
    PORT
      LAYER met4 ;
        RECT 579.220 -75.665 580.600 0.375 ;
    END
  END col_event_rst_bot_left<15>
  PIN col_event_rst_bot_left<14>
    ANTENNAGATEAREA 4.032000 ;
    PORT
      LAYER met4 ;
        RECT 600.780 -75.665 602.160 0.375 ;
    END
  END col_event_rst_bot_left<14>
  PIN array_col_bot_left<29>
    ANTENNADIFFAREA 0.870000 ;
    PORT
      LAYER met4 ;
        RECT 413.520 -75.665 415.360 0.375 ;
    END
  END array_col_bot_left<29>
  PIN array_col_bot_left<28>
    ANTENNADIFFAREA 0.870000 ;
    PORT
      LAYER met4 ;
        RECT 430.020 -75.665 431.860 0.375 ;
    END
  END array_col_bot_left<28>
  PIN array_col_bot_left<24>
    ANTENNADIFFAREA 0.870000 ;
    PORT
      LAYER met4 ;
        RECT 478.020 -75.665 479.860 0.375 ;
    END
  END array_col_bot_left<24>
  PIN array_col_bot_left<19>
    ANTENNADIFFAREA 0.870000 ;
    PORT
      LAYER met4 ;
        RECT 533.520 -75.665 535.360 0.375 ;
    END
  END array_col_bot_left<19>
  PIN col_event_rst_bot_left<13>
    ANTENNAGATEAREA 4.032000 ;
    PORT
      LAYER met4 ;
        RECT 603.220 -75.665 604.600 0.375 ;
    END
  END col_event_rst_bot_left<13>
  PIN col_event_rst_bot_left<12>
    ANTENNAGATEAREA 4.032000 ;
    PORT
      LAYER met4 ;
        RECT 624.780 -75.665 626.160 0.375 ;
    END
  END col_event_rst_bot_left<12>
  PIN col_event_rst_bot_left<11>
    ANTENNAGATEAREA 4.032000 ;
    PORT
      LAYER met4 ;
        RECT 627.220 -75.665 628.600 0.375 ;
    END
  END col_event_rst_bot_left<11>
  PIN col_event_rst_bot_left<10>
    ANTENNAGATEAREA 4.032000 ;
    PORT
      LAYER met4 ;
        RECT 648.780 -75.665 650.160 0.375 ;
    END
  END col_event_rst_bot_left<10>
  PIN col_event_rst_bot_left<9>
    ANTENNAGATEAREA 4.032000 ;
    PORT
      LAYER met4 ;
        RECT 651.220 -75.665 652.600 0.375 ;
    END
  END col_event_rst_bot_left<9>
  PIN col_event_rst_bot_left<8>
    ANTENNAGATEAREA 4.032000 ;
    PORT
      LAYER met4 ;
        RECT 672.780 -75.665 674.160 0.375 ;
    END
  END col_event_rst_bot_left<8>
  PIN col_event_rst_bot_left<7>
    ANTENNAGATEAREA 4.032000 ;
    PORT
      LAYER met4 ;
        RECT 675.220 -75.665 676.600 0.375 ;
    END
  END col_event_rst_bot_left<7>
  PIN col_event_rst_bot_left<6>
    ANTENNAGATEAREA 4.032000 ;
    PORT
      LAYER met4 ;
        RECT 696.780 -75.665 698.160 0.375 ;
    END
  END col_event_rst_bot_left<6>
  PIN col_event_rst_bot_left<5>
    ANTENNAGATEAREA 4.032000 ;
    PORT
      LAYER met4 ;
        RECT 699.220 -75.665 700.600 0.375 ;
    END
  END col_event_rst_bot_left<5>
  PIN array_col_bot_left<1>
    ANTENNADIFFAREA 0.870000 ;
    PORT
      LAYER met4 ;
        RECT 749.520 -75.665 751.360 0.375 ;
    END
  END array_col_bot_left<1>
  PIN array_col_bot_left<12>
    ANTENNADIFFAREA 0.870000 ;
    PORT
      LAYER met4 ;
        RECT 622.020 -75.665 623.860 0.375 ;
    END
  END array_col_bot_left<12>
  PIN array_col_bot_left<13>
    ANTENNADIFFAREA 0.870000 ;
    PORT
      LAYER met4 ;
        RECT 605.520 -75.665 607.360 0.375 ;
    END
  END array_col_bot_left<13>
  PIN col_event_rst_bot_left<4>
    ANTENNAGATEAREA 4.032000 ;
    PORT
      LAYER met4 ;
        RECT 720.780 -75.665 722.160 0.375 ;
    END
  END col_event_rst_bot_left<4>
  PIN col_event_rst_bot_left<3>
    ANTENNAGATEAREA 4.032000 ;
    PORT
      LAYER met4 ;
        RECT 723.220 -75.665 724.600 0.375 ;
    END
  END col_event_rst_bot_left<3>
  PIN col_event_rst_bot_left<2>
    ANTENNAGATEAREA 4.032000 ;
    PORT
      LAYER met4 ;
        RECT 744.780 -75.665 746.160 0.375 ;
    END
  END col_event_rst_bot_left<2>
  PIN array_col_bot_left<34>
    ANTENNADIFFAREA 0.870000 ;
    PORT
      LAYER met4 ;
        RECT 358.020 -75.665 359.860 0.375 ;
    END
  END array_col_bot_left<34>
  PIN array_col_bot_left<27>
    ANTENNADIFFAREA 0.870000 ;
    PORT
      LAYER met4 ;
        RECT 437.520 -75.665 439.360 0.375 ;
    END
  END array_col_bot_left<27>
  PIN array_col_bot_left<25>
    ANTENNADIFFAREA 0.870000 ;
    PORT
      LAYER met4 ;
        RECT 461.520 -75.665 463.360 0.375 ;
    END
  END array_col_bot_left<25>
  PIN array_col_bot_left<18>
    ANTENNADIFFAREA 0.870000 ;
    PORT
      LAYER met4 ;
        RECT 550.020 -75.665 551.860 0.375 ;
    END
  END array_col_bot_left<18>
  PIN array_col_bot_left<17>
    ANTENNADIFFAREA 0.870000 ;
    PORT
      LAYER met4 ;
        RECT 557.520 -75.665 559.360 0.375 ;
    END
  END array_col_bot_left<17>
  PIN array_col_bot_left<9>
    ANTENNADIFFAREA 0.870000 ;
    PORT
      LAYER met4 ;
        RECT 653.520 -75.665 655.360 0.375 ;
    END
  END array_col_bot_left<9>
  PIN array_col_bot_left<8>
    ANTENNADIFFAREA 0.870000 ;
    PORT
      LAYER met4 ;
        RECT 670.020 -75.665 671.860 0.375 ;
    END
  END array_col_bot_left<8>
  PIN col_event_rst_bot_left<1>
    ANTENNAGATEAREA 4.032000 ;
    PORT
      LAYER met4 ;
        RECT 747.220 -75.665 748.600 0.375 ;
    END
  END col_event_rst_bot_left<1>
  PIN col_event_rst_bot_right<63>
    ANTENNAGATEAREA 4.032000 ;
    PORT
      LAYER met4 ;
        RECT 771.220 -75.665 772.600 0.375 ;
    END
  END col_event_rst_bot_right<63>
  PIN col_event_rst_bot_right<53>
    ANTENNAGATEAREA 4.032000 ;
    PORT
      LAYER met4 ;
        RECT 891.220 -75.665 892.600 0.375 ;
    END
  END col_event_rst_bot_right<53>
  PIN col_event_rst_bot_right<52>
    ANTENNAGATEAREA 4.032000 ;
    PORT
      LAYER met4 ;
        RECT 912.780 -75.665 914.160 0.375 ;
    END
  END col_event_rst_bot_right<52>
  PIN col_event_rst_bot_right<51>
    ANTENNAGATEAREA 4.032000 ;
    PORT
      LAYER met4 ;
        RECT 915.220 -75.665 916.600 0.375 ;
    END
  END col_event_rst_bot_right<51>
  PIN col_event_rst_bot_right<50>
    ANTENNAGATEAREA 4.032000 ;
    PORT
      LAYER met4 ;
        RECT 936.780 -75.665 938.160 0.375 ;
    END
  END col_event_rst_bot_right<50>
  PIN col_event_rst_bot_right<49>
    ANTENNAGATEAREA 4.032000 ;
    PORT
      LAYER met4 ;
        RECT 939.220 -75.665 940.600 0.375 ;
    END
  END col_event_rst_bot_right<49>
  PIN col_event_rst_bot_right<48>
    ANTENNAGATEAREA 4.032000 ;
    PORT
      LAYER met4 ;
        RECT 960.780 -75.665 962.160 0.375 ;
    END
  END col_event_rst_bot_right<48>
  PIN col_event_rst_bot_right<47>
    ANTENNAGATEAREA 4.032000 ;
    PORT
      LAYER met4 ;
        RECT 963.220 -75.665 964.600 0.375 ;
    END
  END col_event_rst_bot_right<47>
  PIN col_event_rst_bot_right<46>
    ANTENNAGATEAREA 4.032000 ;
    PORT
      LAYER met4 ;
        RECT 984.780 -75.665 986.160 0.375 ;
    END
  END col_event_rst_bot_right<46>
  PIN col_event_rst_bot_right<45>
    ANTENNAGATEAREA 4.032000 ;
    PORT
      LAYER met4 ;
        RECT 987.220 -75.665 988.600 0.375 ;
    END
  END col_event_rst_bot_right<45>
  PIN col_event_rst_bot_right<44>
    ANTENNAGATEAREA 4.032000 ;
    PORT
      LAYER met4 ;
        RECT 1008.780 -75.665 1010.160 0.375 ;
    END
  END col_event_rst_bot_right<44>
  PIN col_event_rst_bot_right<43>
    ANTENNAGATEAREA 4.032000 ;
    PORT
      LAYER met4 ;
        RECT 1011.220 -75.665 1012.600 0.375 ;
    END
  END col_event_rst_bot_right<43>
  PIN col_event_rst_bot_right<42>
    ANTENNAGATEAREA 4.032000 ;
    PORT
      LAYER met4 ;
        RECT 1032.780 -75.665 1034.160 0.375 ;
    END
  END col_event_rst_bot_right<42>
  PIN col_event_rst_bot_right<41>
    ANTENNAGATEAREA 4.032000 ;
    PORT
      LAYER met4 ;
        RECT 1035.220 -75.665 1036.600 0.375 ;
    END
  END col_event_rst_bot_right<41>
  PIN col_event_rst_bot_right<40>
    ANTENNAGATEAREA 4.032000 ;
    PORT
      LAYER met4 ;
        RECT 1056.780 -75.665 1058.160 0.375 ;
    END
  END col_event_rst_bot_right<40>
  PIN col_event_rst_bot_right<39>
    ANTENNAGATEAREA 4.032000 ;
    PORT
      LAYER met4 ;
        RECT 1059.220 -75.665 1060.600 0.375 ;
    END
  END col_event_rst_bot_right<39>
  PIN array_col_bot_right<55>
    ANTENNADIFFAREA 0.870000 ;
    PORT
      LAYER met4 ;
        RECT 869.520 -75.665 871.360 0.375 ;
    END
  END array_col_bot_right<55>
  PIN array_col_bot_right<62>
    ANTENNADIFFAREA 0.870000 ;
    PORT
      LAYER met4 ;
        RECT 790.020 -75.665 791.860 0.375 ;
    END
  END array_col_bot_right<62>
  PIN array_col_bot_right<59>
    ANTENNADIFFAREA 0.870000 ;
    PORT
      LAYER met4 ;
        RECT 821.520 -75.665 823.360 0.375 ;
    END
  END array_col_bot_right<59>
  PIN array_col_bot_right<58>
    ANTENNADIFFAREA 0.870000 ;
    PORT
      LAYER met4 ;
        RECT 838.020 -75.665 839.860 0.375 ;
    END
  END array_col_bot_right<58>
  PIN array_col_bot_right<54>
    ANTENNADIFFAREA 0.870000 ;
    PORT
      LAYER met4 ;
        RECT 886.020 -75.665 887.860 0.375 ;
    END
  END array_col_bot_right<54>
  PIN col_event_rst_bot_right<38>
    ANTENNAGATEAREA 4.032000 ;
    PORT
      LAYER met4 ;
        RECT 1080.780 -75.665 1082.160 0.375 ;
    END
  END col_event_rst_bot_right<38>
  PIN col_event_rst_bot_right<37>
    ANTENNAGATEAREA 4.032000 ;
    PORT
      LAYER met4 ;
        RECT 1083.220 -75.665 1084.600 0.375 ;
    END
  END col_event_rst_bot_right<37>
  PIN col_event_rst_bot_right<36>
    ANTENNAGATEAREA 4.032000 ;
    PORT
      LAYER met4 ;
        RECT 1104.780 -75.665 1106.160 0.375 ;
    END
  END col_event_rst_bot_right<36>
  PIN col_event_rst_bot_right<35>
    ANTENNAGATEAREA 4.032000 ;
    PORT
      LAYER met4 ;
        RECT 1107.220 -75.665 1108.600 0.375 ;
    END
  END col_event_rst_bot_right<35>
  PIN col_event_rst_bot_right<34>
    ANTENNAGATEAREA 4.032000 ;
    PORT
      LAYER met4 ;
        RECT 1128.780 -75.665 1130.160 0.375 ;
    END
  END col_event_rst_bot_right<34>
  PIN array_col_bot_right<61>
    ANTENNADIFFAREA 0.870000 ;
    PORT
      LAYER met4 ;
        RECT 797.520 -75.665 799.360 0.375 ;
    END
  END array_col_bot_right<61>
  PIN col_event_rst_bot_right<33>
    ANTENNAGATEAREA 4.032000 ;
    PORT
      LAYER met4 ;
        RECT 1131.220 -75.665 1132.600 0.375 ;
    END
  END col_event_rst_bot_right<33>
  PIN col_event_rst_bot_right<32>
    ANTENNAGATEAREA 4.032000 ;
    PORT
      LAYER met4 ;
        RECT 1152.780 -75.665 1154.160 0.375 ;
    END
  END col_event_rst_bot_right<32>
  PIN col_event_rst_bot_right<31>
    ANTENNAGATEAREA 4.032000 ;
    PORT
      LAYER met4 ;
        RECT 1155.220 -75.665 1156.600 0.375 ;
    END
  END col_event_rst_bot_right<31>
  PIN col_event_rst_bot_right<30>
    ANTENNAGATEAREA 4.032000 ;
    PORT
      LAYER met4 ;
        RECT 1176.780 -75.665 1178.160 0.375 ;
    END
  END col_event_rst_bot_right<30>
  PIN col_event_rst_bot_right<29>
    ANTENNAGATEAREA 4.032000 ;
    PORT
      LAYER met4 ;
        RECT 1179.220 -75.665 1180.600 0.375 ;
    END
  END col_event_rst_bot_right<29>
  PIN array_col_bot_right<29>
    ANTENNADIFFAREA 0.870000 ;
    PORT
      LAYER met4 ;
        RECT 1181.520 -75.665 1183.360 0.375 ;
    END
  END array_col_bot_right<29>
  PIN array_col_bot_right<60>
    ANTENNADIFFAREA 0.870000 ;
    PORT
      LAYER met4 ;
        RECT 814.020 -75.665 815.860 0.375 ;
    END
  END array_col_bot_right<60>
  PIN array_col_bot_right<57>
    ANTENNADIFFAREA 0.870000 ;
    PORT
      LAYER met4 ;
        RECT 845.520 -75.665 847.360 0.375 ;
    END
  END array_col_bot_right<57>
  PIN array_col_bot_right<56>
    ANTENNADIFFAREA 0.870000 ;
    PORT
      LAYER met4 ;
        RECT 862.020 -75.665 863.860 0.375 ;
    END
  END array_col_bot_right<56>
  PIN array_col_bot_right<53>
    ANTENNADIFFAREA 0.870000 ;
    PORT
      LAYER met4 ;
        RECT 893.520 -75.665 895.360 0.375 ;
    END
  END array_col_bot_right<53>
  PIN array_col_bot_right<52>
    ANTENNADIFFAREA 0.870000 ;
    PORT
      LAYER met4 ;
        RECT 910.020 -75.665 911.860 0.375 ;
    END
  END array_col_bot_right<52>
  PIN array_col_bot_right<49>
    ANTENNADIFFAREA 0.870000 ;
    PORT
      LAYER met4 ;
        RECT 941.520 -75.665 943.360 0.375 ;
    END
  END array_col_bot_right<49>
  PIN array_col_bot_right<48>
    ANTENNADIFFAREA 0.870000 ;
    PORT
      LAYER met4 ;
        RECT 958.020 -75.665 959.860 0.375 ;
    END
  END array_col_bot_right<48>
  PIN array_col_bot_right<45>
    ANTENNADIFFAREA 0.870000 ;
    PORT
      LAYER met4 ;
        RECT 989.520 -75.665 991.360 0.375 ;
    END
  END array_col_bot_right<45>
  PIN array_col_bot_right<44>
    ANTENNADIFFAREA 0.870000 ;
    PORT
      LAYER met4 ;
        RECT 1006.020 -75.665 1007.860 0.375 ;
    END
  END array_col_bot_right<44>
  PIN array_col_bot_right<41>
    ANTENNADIFFAREA 0.870000 ;
    PORT
      LAYER met4 ;
        RECT 1037.520 -75.665 1039.360 0.375 ;
    END
  END array_col_bot_right<41>
  PIN array_col_bot_right<40>
    ANTENNADIFFAREA 0.870000 ;
    PORT
      LAYER met4 ;
        RECT 1054.020 -75.665 1055.860 0.375 ;
    END
  END array_col_bot_right<40>
  PIN array_col_bot_right<37>
    ANTENNADIFFAREA 0.870000 ;
    PORT
      LAYER met4 ;
        RECT 1085.520 -75.665 1087.360 0.375 ;
    END
  END array_col_bot_right<37>
  PIN array_col_bot_right<36>
    ANTENNADIFFAREA 0.870000 ;
    PORT
      LAYER met4 ;
        RECT 1102.020 -75.665 1103.860 0.375 ;
    END
  END array_col_bot_right<36>
  PIN array_col_bot_right<33>
    ANTENNADIFFAREA 0.870000 ;
    PORT
      LAYER met4 ;
        RECT 1133.520 -75.665 1135.360 0.375 ;
    END
  END array_col_bot_right<33>
  PIN array_col_bot_right<32>
    ANTENNADIFFAREA 0.870000 ;
    PORT
      LAYER met4 ;
        RECT 1150.020 -75.665 1151.860 0.375 ;
    END
  END array_col_bot_right<32>
  PIN array_col_bot_right<51>
    ANTENNADIFFAREA 0.870000 ;
    PORT
      LAYER met4 ;
        RECT 917.520 -75.665 919.360 0.375 ;
    END
  END array_col_bot_right<51>
  PIN array_col_bot_right<50>
    ANTENNADIFFAREA 0.870000 ;
    PORT
      LAYER met4 ;
        RECT 934.020 -75.665 935.860 0.375 ;
    END
  END array_col_bot_right<50>
  PIN array_col_bot_right<47>
    ANTENNADIFFAREA 0.870000 ;
    PORT
      LAYER met4 ;
        RECT 965.520 -75.665 967.360 0.375 ;
    END
  END array_col_bot_right<47>
  PIN array_col_bot_right<46>
    ANTENNADIFFAREA 0.870000 ;
    PORT
      LAYER met4 ;
        RECT 982.020 -75.665 983.860 0.375 ;
    END
  END array_col_bot_right<46>
  PIN array_col_bot_right<43>
    ANTENNADIFFAREA 0.870000 ;
    PORT
      LAYER met4 ;
        RECT 1013.520 -75.665 1015.360 0.375 ;
    END
  END array_col_bot_right<43>
  PIN array_col_bot_right<42>
    ANTENNADIFFAREA 0.870000 ;
    PORT
      LAYER met4 ;
        RECT 1030.020 -75.665 1031.860 0.375 ;
    END
  END array_col_bot_right<42>
  PIN array_col_bot_right<39>
    ANTENNADIFFAREA 0.870000 ;
    PORT
      LAYER met4 ;
        RECT 1061.520 -75.665 1063.360 0.375 ;
    END
  END array_col_bot_right<39>
  PIN array_col_bot_right<38>
    ANTENNADIFFAREA 0.870000 ;
    PORT
      LAYER met4 ;
        RECT 1078.020 -75.665 1079.860 0.375 ;
    END
  END array_col_bot_right<38>
  PIN array_col_bot_right<35>
    ANTENNADIFFAREA 0.870000 ;
    PORT
      LAYER met4 ;
        RECT 1109.520 -75.665 1111.360 0.375 ;
    END
  END array_col_bot_right<35>
  PIN array_col_bot_right<34>
    ANTENNADIFFAREA 0.870000 ;
    PORT
      LAYER met4 ;
        RECT 1126.020 -75.665 1127.860 0.375 ;
    END
  END array_col_bot_right<34>
  PIN array_col_bot_right<31>
    ANTENNADIFFAREA 0.870000 ;
    PORT
      LAYER met4 ;
        RECT 1157.520 -75.665 1159.360 0.375 ;
    END
  END array_col_bot_right<31>
  PIN array_col_bot_right<30>
    ANTENNADIFFAREA 0.870000 ;
    PORT
      LAYER met4 ;
        RECT 1174.020 -75.665 1175.860 0.375 ;
    END
  END array_col_bot_right<30>
  PIN col_event_rst_bot_right<62>
    ANTENNAGATEAREA 4.032000 ;
    PORT
      LAYER met4 ;
        RECT 792.780 -75.665 794.160 0.375 ;
    END
  END col_event_rst_bot_right<62>
  PIN col_event_rst_bot_right<61>
    ANTENNAGATEAREA 4.032000 ;
    PORT
      LAYER met4 ;
        RECT 795.220 -75.665 796.600 0.375 ;
    END
  END col_event_rst_bot_right<61>
  PIN col_event_rst_bot_right<60>
    ANTENNAGATEAREA 4.032000 ;
    PORT
      LAYER met4 ;
        RECT 817.250 -75.665 818.630 0.375 ;
    END
  END col_event_rst_bot_right<60>
  PIN col_event_rst_bot_right<59>
    ANTENNAGATEAREA 4.032000 ;
    PORT
      LAYER met4 ;
        RECT 819.220 -75.665 820.600 0.375 ;
    END
  END col_event_rst_bot_right<59>
  PIN col_event_rst_bot_right<58>
    ANTENNAGATEAREA 4.032000 ;
    PORT
      LAYER met4 ;
        RECT 840.780 -75.665 842.160 0.375 ;
    END
  END col_event_rst_bot_right<58>
  PIN col_event_rst_bot_right<57>
    ANTENNAGATEAREA 4.032000 ;
    PORT
      LAYER met4 ;
        RECT 843.220 -75.665 844.600 0.375 ;
    END
  END col_event_rst_bot_right<57>
  PIN col_event_rst_bot_right<56>
    ANTENNAGATEAREA 4.032000 ;
    PORT
      LAYER met4 ;
        RECT 864.780 -75.665 866.160 0.375 ;
    END
  END col_event_rst_bot_right<56>
  PIN array_col_bot_right<63>
    ANTENNADIFFAREA 0.870000 ;
    PORT
      LAYER met4 ;
        RECT 773.520 -75.665 775.360 0.375 ;
    END
  END array_col_bot_right<63>
  PIN col_event_rst_bot_right<55>
    ANTENNAGATEAREA 4.032000 ;
    PORT
      LAYER met4 ;
        RECT 867.220 -75.665 868.600 0.375 ;
    END
  END col_event_rst_bot_right<55>
  PIN col_event_rst_bot_right<54>
    ANTENNAGATEAREA 4.032000 ;
    PORT
      LAYER met4 ;
        RECT 888.780 -75.665 890.160 0.375 ;
    END
  END col_event_rst_bot_right<54>
  PIN array_col_bot_right<0>
    ANTENNADIFFAREA 0.870000 ;
    PORT
      LAYER met4 ;
        RECT 1534.020 -75.665 1535.860 0.375 ;
    END
  END array_col_bot_right<0>
  PIN array_col_bot_right<3>
    ANTENNADIFFAREA 0.870000 ;
    PORT
      LAYER met4 ;
        RECT 1493.520 -75.665 1495.360 0.375 ;
    END
  END array_col_bot_right<3>
  PIN array_col_bot_right<15>
    ANTENNADIFFAREA 0.870000 ;
    PORT
      LAYER met4 ;
        RECT 1349.520 -75.665 1351.360 0.375 ;
    END
  END array_col_bot_right<15>
  PIN array_col_bot_right<27>
    ANTENNADIFFAREA 0.870000 ;
    PORT
      LAYER met4 ;
        RECT 1205.520 -75.665 1207.360 0.375 ;
    END
  END array_col_bot_right<27>
  PIN array_col_bot_right<26>
    ANTENNADIFFAREA 0.870000 ;
    PORT
      LAYER met4 ;
        RECT 1222.020 -75.665 1223.860 0.375 ;
    END
  END array_col_bot_right<26>
  PIN array_col_bot_right<11>
    ANTENNADIFFAREA 0.870000 ;
    PORT
      LAYER met4 ;
        RECT 1397.520 -75.665 1399.360 0.375 ;
    END
  END array_col_bot_right<11>
  PIN array_col_bot_right<17>
    ANTENNADIFFAREA 0.870000 ;
    PORT
      LAYER met4 ;
        RECT 1325.520 -75.665 1327.360 0.375 ;
    END
  END array_col_bot_right<17>
  PIN array_col_bot_right<2>
    ANTENNADIFFAREA 0.870000 ;
    PORT
      LAYER met4 ;
        RECT 1510.020 -75.665 1511.860 0.375 ;
    END
  END array_col_bot_right<2>
  PIN array_col_bot_right<13>
    ANTENNADIFFAREA 0.870000 ;
    PORT
      LAYER met4 ;
        RECT 1373.520 -75.665 1375.360 0.375 ;
    END
  END array_col_bot_right<13>
  PIN array_col_bot_right<18>
    ANTENNADIFFAREA 0.870000 ;
    PORT
      LAYER met4 ;
        RECT 1318.020 -75.665 1319.860 0.375 ;
    END
  END array_col_bot_right<18>
  PIN array_col_bot_right<9>
    ANTENNADIFFAREA 0.870000 ;
    PORT
      LAYER met4 ;
        RECT 1421.520 -75.665 1423.360 0.375 ;
    END
  END array_col_bot_right<9>
  PIN col_event_rst_bot_right<22>
    ANTENNAGATEAREA 4.032000 ;
    PORT
      LAYER met4 ;
        RECT 1272.780 -75.665 1274.160 0.375 ;
    END
  END col_event_rst_bot_right<22>
  PIN col_event_rst_bot_right<21>
    ANTENNAGATEAREA 4.032000 ;
    PORT
      LAYER met4 ;
        RECT 1275.220 -75.665 1276.600 0.375 ;
    END
  END col_event_rst_bot_right<21>
  PIN col_event_rst_bot_right<20>
    ANTENNAGATEAREA 4.032000 ;
    PORT
      LAYER met4 ;
        RECT 1296.780 -75.665 1298.160 0.375 ;
    END
  END col_event_rst_bot_right<20>
  PIN col_event_rst_bot_right<19>
    ANTENNAGATEAREA 4.032000 ;
    PORT
      LAYER met4 ;
        RECT 1299.220 -75.665 1300.600 0.375 ;
    END
  END col_event_rst_bot_right<19>
  PIN col_event_rst_bot_right<18>
    ANTENNAGATEAREA 4.032000 ;
    PORT
      LAYER met4 ;
        RECT 1320.780 -75.665 1322.160 0.375 ;
    END
  END col_event_rst_bot_right<18>
  PIN col_event_rst_bot_right<17>
    ANTENNAGATEAREA 4.032000 ;
    PORT
      LAYER met4 ;
        RECT 1323.220 -75.665 1324.600 0.375 ;
    END
  END col_event_rst_bot_right<17>
  PIN col_event_rst_bot_right<16>
    ANTENNAGATEAREA 4.032000 ;
    PORT
      LAYER met4 ;
        RECT 1344.780 -75.665 1346.160 0.375 ;
    END
  END col_event_rst_bot_right<16>
  PIN col_event_rst_bot_right<15>
    ANTENNAGATEAREA 4.032000 ;
    PORT
      LAYER met4 ;
        RECT 1347.220 -75.665 1348.600 0.375 ;
    END
  END col_event_rst_bot_right<15>
  PIN col_event_rst_bot_right<14>
    ANTENNAGATEAREA 4.032000 ;
    PORT
      LAYER met4 ;
        RECT 1368.780 -75.665 1370.160 0.375 ;
    END
  END col_event_rst_bot_right<14>
  PIN col_event_rst_bot_right<13>
    ANTENNAGATEAREA 4.032000 ;
    PORT
      LAYER met4 ;
        RECT 1371.220 -75.665 1372.600 0.375 ;
    END
  END col_event_rst_bot_right<13>
  PIN col_event_rst_bot_right<12>
    ANTENNAGATEAREA 4.032000 ;
    PORT
      LAYER met4 ;
        RECT 1392.780 -75.665 1394.160 0.375 ;
    END
  END col_event_rst_bot_right<12>
  PIN col_event_rst_bot_right<11>
    ANTENNAGATEAREA 4.032000 ;
    PORT
      LAYER met4 ;
        RECT 1395.220 -75.665 1396.600 0.375 ;
    END
  END col_event_rst_bot_right<11>
  PIN col_event_rst_bot_right<10>
    ANTENNAGATEAREA 4.032000 ;
    PORT
      LAYER met4 ;
        RECT 1416.780 -75.665 1418.160 0.375 ;
    END
  END col_event_rst_bot_right<10>
  PIN col_event_rst_bot_right<9>
    ANTENNAGATEAREA 4.032000 ;
    PORT
      LAYER met4 ;
        RECT 1419.220 -75.665 1420.600 0.375 ;
    END
  END col_event_rst_bot_right<9>
  PIN col_event_rst_bot_right<8>
    ANTENNAGATEAREA 4.032000 ;
    PORT
      LAYER met4 ;
        RECT 1440.780 -75.665 1442.160 0.375 ;
    END
  END col_event_rst_bot_right<8>
  PIN col_event_rst_bot_right<7>
    ANTENNAGATEAREA 4.032000 ;
    PORT
      LAYER met4 ;
        RECT 1443.220 -75.665 1444.600 0.375 ;
    END
  END col_event_rst_bot_right<7>
  PIN col_event_rst_bot_right<6>
    ANTENNAGATEAREA 4.032000 ;
    PORT
      LAYER met4 ;
        RECT 1464.780 -75.665 1466.160 0.375 ;
    END
  END col_event_rst_bot_right<6>
  PIN col_event_rst_bot_right<5>
    ANTENNAGATEAREA 4.032000 ;
    PORT
      LAYER met4 ;
        RECT 1467.220 -75.665 1468.600 0.375 ;
    END
  END col_event_rst_bot_right<5>
  PIN array_col_bot_right<4>
    ANTENNADIFFAREA 0.870000 ;
    PORT
      LAYER met4 ;
        RECT 1486.020 -75.665 1487.860 0.375 ;
    END
  END array_col_bot_right<4>
  PIN array_col_bot_right<6>
    ANTENNADIFFAREA 0.870000 ;
    PORT
      LAYER met4 ;
        RECT 1462.020 -75.665 1463.860 0.375 ;
    END
  END array_col_bot_right<6>
  PIN array_col_bot_right<22>
    ANTENNADIFFAREA 0.870000 ;
    PORT
      LAYER met4 ;
        RECT 1270.020 -75.665 1271.860 0.375 ;
    END
  END array_col_bot_right<22>
  PIN array_col_bot_right<14>
    ANTENNADIFFAREA 0.870000 ;
    PORT
      LAYER met4 ;
        RECT 1366.020 -75.665 1367.860 0.375 ;
    END
  END array_col_bot_right<14>
  PIN col_event_rst_bot_right<28>
    ANTENNAGATEAREA 4.032000 ;
    PORT
      LAYER met4 ;
        RECT 1200.780 -75.665 1202.160 0.375 ;
    END
  END col_event_rst_bot_right<28>
  PIN array_col_bot_right<10>
    ANTENNADIFFAREA 0.870000 ;
    PORT
      LAYER met4 ;
        RECT 1414.020 -75.665 1415.860 0.375 ;
    END
  END array_col_bot_right<10>
  PIN array_col_bot_right<28>
    ANTENNADIFFAREA 0.870000 ;
    PORT
      LAYER met4 ;
        RECT 1198.020 -75.665 1199.860 0.375 ;
    END
  END array_col_bot_right<28>
  PIN array_col_bot_right<25>
    ANTENNADIFFAREA 0.870000 ;
    PORT
      LAYER met4 ;
        RECT 1229.520 -75.665 1231.360 0.375 ;
    END
  END array_col_bot_right<25>
  PIN col_event_rst_bot_right<27>
    ANTENNAGATEAREA 4.032000 ;
    PORT
      LAYER met4 ;
        RECT 1203.220 -75.665 1204.600 0.375 ;
    END
  END col_event_rst_bot_right<27>
  PIN array_col_bot_right<8>
    ANTENNADIFFAREA 0.870000 ;
    PORT
      LAYER met4 ;
        RECT 1438.020 -75.665 1439.860 0.375 ;
    END
  END array_col_bot_right<8>
  PIN array_col_bot_right<24>
    ANTENNADIFFAREA 0.870000 ;
    PORT
      LAYER met4 ;
        RECT 1246.020 -75.665 1247.860 0.375 ;
    END
  END array_col_bot_right<24>
  PIN array_col_bot_right<21>
    ANTENNADIFFAREA 0.870000 ;
    PORT
      LAYER met4 ;
        RECT 1277.520 -75.665 1279.360 0.375 ;
    END
  END array_col_bot_right<21>
  PIN col_event_rst_bot_right<4>
    ANTENNAGATEAREA 4.032000 ;
    PORT
      LAYER met4 ;
        RECT 1488.780 -75.665 1490.160 0.375 ;
    END
  END col_event_rst_bot_right<4>
  PIN array_col_bot_right<20>
    ANTENNADIFFAREA 0.870000 ;
    PORT
      LAYER met4 ;
        RECT 1294.020 -75.665 1295.860 0.375 ;
    END
  END array_col_bot_right<20>
  PIN col_event_rst_bot_right<3>
    ANTENNAGATEAREA 4.032000 ;
    PORT
      LAYER met4 ;
        RECT 1491.220 -75.665 1492.600 0.375 ;
    END
  END col_event_rst_bot_right<3>
  PIN col_event_rst_bot_right<2>
    ANTENNAGATEAREA 4.032000 ;
    PORT
      LAYER met4 ;
        RECT 1512.780 -75.665 1514.160 0.375 ;
    END
  END col_event_rst_bot_right<2>
  PIN col_event_rst_bot_right<1>
    ANTENNAGATEAREA 4.032000 ;
    PORT
      LAYER met4 ;
        RECT 1515.220 -75.665 1516.600 0.375 ;
    END
  END col_event_rst_bot_right<1>
  PIN col_event_rst_bot_right<0>
    ANTENNAGATEAREA 4.032000 ;
    PORT
      LAYER met4 ;
        RECT 1536.780 -75.665 1538.160 0.375 ;
    END
  END col_event_rst_bot_right<0>
  PIN array_col_bot_right<7>
    ANTENNADIFFAREA 0.870000 ;
    PORT
      LAYER met4 ;
        RECT 1445.520 -75.665 1447.360 0.375 ;
    END
  END array_col_bot_right<7>
  PIN array_col_bot_right<5>
    ANTENNADIFFAREA 0.870000 ;
    PORT
      LAYER met4 ;
        RECT 1469.520 -75.665 1471.360 0.375 ;
    END
  END array_col_bot_right<5>
  PIN col_event_rst_bot_right<26>
    ANTENNAGATEAREA 4.032000 ;
    PORT
      LAYER met4 ;
        RECT 1224.780 -75.665 1226.160 0.375 ;
    END
  END col_event_rst_bot_right<26>
  PIN array_col_bot_right<12>
    ANTENNADIFFAREA 0.870000 ;
    PORT
      LAYER met4 ;
        RECT 1390.020 -75.665 1391.860 0.375 ;
    END
  END array_col_bot_right<12>
  PIN col_event_rst_bot_right<25>
    ANTENNAGATEAREA 4.032000 ;
    PORT
      LAYER met4 ;
        RECT 1227.220 -75.665 1228.600 0.375 ;
    END
  END col_event_rst_bot_right<25>
  PIN col_event_rst_bot_right<24>
    ANTENNAGATEAREA 4.032000 ;
    PORT
      LAYER met4 ;
        RECT 1248.780 -75.665 1250.160 0.375 ;
    END
  END col_event_rst_bot_right<24>
  PIN col_event_rst_bot_right<23>
    ANTENNAGATEAREA 4.032000 ;
    PORT
      LAYER met4 ;
        RECT 1251.220 -75.665 1252.600 0.375 ;
    END
  END col_event_rst_bot_right<23>
  PIN array_col_bot_right<19>
    ANTENNADIFFAREA 0.870000 ;
    PORT
      LAYER met4 ;
        RECT 1301.520 -75.665 1303.360 0.375 ;
    END
  END array_col_bot_right<19>
  PIN array_col_bot_right<1>
    ANTENNADIFFAREA 0.870000 ;
    PORT
      LAYER met4 ;
        RECT 1517.520 -75.665 1519.360 0.375 ;
    END
  END array_col_bot_right<1>
  PIN array_col_bot_right<23>
    ANTENNADIFFAREA 0.870000 ;
    PORT
      LAYER met4 ;
        RECT 1253.520 -75.665 1255.360 0.375 ;
    END
  END array_col_bot_right<23>
  PIN array_col_bot_right<16>
    ANTENNADIFFAREA 0.870000 ;
    PORT
      LAYER met4 ;
        RECT 1342.020 -75.665 1343.860 0.375 ;
    END
  END array_col_bot_right<16>
  OBS
      LAYER nwell ;
        RECT -0.940 -0.005 1542.320 1638.445 ;
      LAYER li1 ;
        RECT -0.605 0.125 1541.985 1638.315 ;
      LAYER met1 ;
        RECT -0.665 -30.000 1591.380 1668.440 ;
      LAYER met2 ;
        RECT -70.000 -30.000 1612.020 1668.440 ;
      LAYER met3 ;
        RECT -69.990 1628.835 1611.380 1658.040 ;
        RECT 9.005 1626.675 1611.380 1628.835 ;
        RECT -69.990 1620.705 1611.380 1626.675 ;
        RECT 9.005 1618.505 1611.380 1620.705 ;
        RECT -69.990 1609.115 1611.380 1618.505 ;
        RECT 9.005 1606.955 1611.380 1609.115 ;
        RECT -69.990 1577.470 1611.380 1606.955 ;
        RECT -43.965 1576.370 1611.380 1577.470 ;
        RECT -69.990 1576.110 1611.380 1576.370 ;
        RECT -43.965 1574.330 1611.380 1576.110 ;
        RECT -69.990 1574.070 1611.380 1574.330 ;
        RECT -43.965 1572.970 1611.380 1574.070 ;
        RECT -69.990 1553.670 1611.380 1572.970 ;
        RECT -43.965 1552.570 1611.380 1553.670 ;
        RECT -69.990 1552.310 1611.380 1552.570 ;
        RECT -43.965 1550.530 1611.380 1552.310 ;
        RECT -69.990 1550.270 1611.380 1550.530 ;
        RECT -43.965 1549.170 1611.380 1550.270 ;
        RECT -69.990 1529.190 1611.380 1549.170 ;
        RECT -43.965 1527.410 1611.380 1529.190 ;
        RECT -69.990 1527.150 1611.380 1527.410 ;
        RECT -43.965 1526.050 1611.380 1527.150 ;
        RECT -69.990 1525.790 1611.380 1526.050 ;
        RECT -43.965 1524.690 1611.380 1525.790 ;
        RECT -69.990 1505.390 1611.380 1524.690 ;
        RECT -43.965 1504.290 1611.380 1505.390 ;
        RECT -69.990 1504.030 1611.380 1504.290 ;
        RECT -43.965 1502.250 1611.380 1504.030 ;
        RECT -69.990 1501.990 1611.380 1502.250 ;
        RECT -43.965 1500.890 1611.380 1501.990 ;
        RECT -69.990 1481.590 1611.380 1500.890 ;
        RECT -43.965 1480.490 1611.380 1481.590 ;
        RECT -69.990 1480.230 1611.380 1480.490 ;
        RECT -43.965 1478.450 1611.380 1480.230 ;
        RECT -69.990 1478.190 1611.380 1478.450 ;
        RECT -43.965 1477.090 1611.380 1478.190 ;
        RECT -69.990 1457.110 1611.380 1477.090 ;
        RECT -43.965 1455.330 1611.380 1457.110 ;
        RECT -69.990 1455.070 1611.380 1455.330 ;
        RECT -43.965 1453.290 1611.380 1455.070 ;
        RECT -69.990 1433.310 1611.380 1453.290 ;
        RECT -43.965 1432.210 1611.380 1433.310 ;
        RECT -69.990 1431.950 1611.380 1432.210 ;
        RECT -43.965 1430.170 1611.380 1431.950 ;
        RECT -69.990 1429.910 1611.380 1430.170 ;
        RECT -43.965 1428.810 1611.380 1429.910 ;
        RECT -69.990 1409.510 1611.380 1428.810 ;
        RECT -43.965 1408.410 1611.380 1409.510 ;
        RECT -69.990 1408.150 1611.380 1408.410 ;
        RECT -43.965 1407.050 1611.380 1408.150 ;
        RECT -69.990 1406.790 1611.380 1407.050 ;
        RECT -43.965 1406.730 1611.380 1406.790 ;
        RECT -69.990 1406.390 1611.380 1406.730 ;
        RECT -43.965 1405.010 1611.380 1406.390 ;
        RECT -69.990 1385.710 1611.380 1405.010 ;
        RECT -43.965 1384.610 1611.380 1385.710 ;
        RECT -69.990 1384.350 1611.380 1384.610 ;
        RECT -43.965 1383.250 1611.380 1384.350 ;
        RECT -69.990 1382.990 1611.380 1383.250 ;
        RECT -43.965 1381.210 1611.380 1382.990 ;
        RECT -69.990 1361.230 1611.380 1381.210 ;
        RECT -43.965 1359.850 1611.380 1361.230 ;
        RECT -69.990 1359.700 1611.380 1359.850 ;
        RECT -43.965 1359.450 1611.380 1359.700 ;
        RECT -69.990 1359.190 1611.380 1359.450 ;
        RECT -43.965 1358.090 1611.380 1359.190 ;
        RECT -69.990 1357.830 1611.380 1358.090 ;
        RECT -43.965 1356.730 1611.380 1357.830 ;
        RECT -69.990 1337.430 1611.380 1356.730 ;
        RECT -43.965 1336.050 1611.380 1337.430 ;
        RECT -69.990 1335.730 1611.380 1336.050 ;
        RECT -43.965 1335.650 1611.380 1335.730 ;
        RECT -69.990 1335.390 1611.380 1335.650 ;
        RECT -43.965 1334.290 1611.380 1335.390 ;
        RECT -69.990 1334.030 1611.380 1334.290 ;
        RECT -43.965 1332.930 1611.380 1334.030 ;
        RECT -69.990 1313.630 1611.380 1332.930 ;
        RECT -43.965 1312.530 1611.380 1313.630 ;
        RECT -69.990 1312.270 1611.380 1312.530 ;
        RECT -43.965 1310.490 1611.380 1312.270 ;
        RECT -69.990 1310.230 1611.380 1310.490 ;
        RECT -43.965 1309.130 1611.380 1310.230 ;
        RECT -69.990 1289.150 1611.380 1309.130 ;
        RECT -43.965 1287.370 1611.380 1289.150 ;
        RECT -69.990 1287.110 1611.380 1287.370 ;
        RECT -43.965 1285.330 1611.380 1287.110 ;
        RECT -69.990 1265.350 1611.380 1285.330 ;
        RECT -43.965 1264.250 1611.380 1265.350 ;
        RECT -69.990 1263.990 1611.380 1264.250 ;
        RECT -43.965 1262.210 1611.380 1263.990 ;
        RECT -69.990 1261.950 1611.380 1262.210 ;
        RECT -43.965 1260.850 1611.380 1261.950 ;
        RECT -69.990 1241.550 1611.380 1260.850 ;
        RECT -43.965 1240.450 1611.380 1241.550 ;
        RECT -69.990 1240.190 1611.380 1240.450 ;
        RECT -43.965 1238.410 1611.380 1240.190 ;
        RECT -69.990 1238.150 1611.380 1238.410 ;
        RECT -43.965 1237.050 1611.380 1238.150 ;
        RECT -69.990 1217.070 1611.380 1237.050 ;
        RECT -43.965 1215.290 1611.380 1217.070 ;
        RECT -69.990 1215.030 1611.380 1215.290 ;
        RECT -43.965 1213.250 1611.380 1215.030 ;
        RECT -69.990 1193.270 1611.380 1213.250 ;
        RECT -43.965 1192.170 1611.380 1193.270 ;
        RECT -69.990 1191.910 1611.380 1192.170 ;
        RECT -43.965 1190.130 1611.380 1191.910 ;
        RECT -69.990 1189.870 1611.380 1190.130 ;
        RECT -43.965 1188.770 1611.380 1189.870 ;
        RECT -69.990 1169.470 1611.380 1188.770 ;
        RECT -43.965 1168.370 1611.380 1169.470 ;
        RECT -69.990 1168.110 1611.380 1168.370 ;
        RECT -43.965 1166.330 1611.380 1168.110 ;
        RECT -69.990 1166.070 1611.380 1166.330 ;
        RECT -43.965 1164.970 1611.380 1166.070 ;
        RECT -69.990 1145.670 1611.380 1164.970 ;
        RECT -43.965 1144.570 1611.380 1145.670 ;
        RECT -69.990 1144.310 1611.380 1144.570 ;
        RECT -43.965 1142.530 1611.380 1144.310 ;
        RECT -69.990 1142.270 1611.380 1142.530 ;
        RECT -43.965 1141.170 1611.380 1142.270 ;
        RECT -69.990 1121.190 1611.380 1141.170 ;
        RECT -43.965 1119.410 1611.380 1121.190 ;
        RECT -69.990 1119.150 1611.380 1119.410 ;
        RECT -43.965 1118.050 1611.380 1119.150 ;
        RECT -69.990 1117.790 1611.380 1118.050 ;
        RECT -43.965 1116.690 1611.380 1117.790 ;
        RECT -69.990 1097.390 1611.380 1116.690 ;
        RECT -43.965 1096.290 1611.380 1097.390 ;
        RECT -69.990 1096.030 1611.380 1096.290 ;
        RECT -43.965 1094.250 1611.380 1096.030 ;
        RECT -69.990 1093.990 1611.380 1094.250 ;
        RECT -43.965 1092.890 1611.380 1093.990 ;
        RECT -69.990 1073.590 1611.380 1092.890 ;
        RECT -43.965 1072.490 1611.380 1073.590 ;
        RECT -69.990 1072.230 1611.380 1072.490 ;
        RECT -43.965 1070.450 1611.380 1072.230 ;
        RECT -69.990 1070.190 1611.380 1070.450 ;
        RECT -43.965 1069.090 1611.380 1070.190 ;
        RECT -69.990 1049.110 1611.380 1069.090 ;
        RECT -43.965 1047.330 1611.380 1049.110 ;
        RECT -69.990 1047.070 1611.380 1047.330 ;
        RECT -43.965 1045.290 1611.380 1047.070 ;
        RECT -69.990 1025.310 1611.380 1045.290 ;
        RECT -43.965 1024.210 1611.380 1025.310 ;
        RECT -69.990 1023.950 1611.380 1024.210 ;
        RECT -43.965 1022.170 1611.380 1023.950 ;
        RECT -69.990 1021.910 1611.380 1022.170 ;
        RECT -43.965 1020.810 1611.380 1021.910 ;
        RECT -69.990 1001.510 1611.380 1020.810 ;
        RECT -43.965 1000.410 1611.380 1001.510 ;
        RECT -69.990 1000.150 1611.380 1000.410 ;
        RECT -43.965 999.050 1611.380 1000.150 ;
        RECT -69.990 998.790 1611.380 999.050 ;
        RECT -43.965 998.730 1611.380 998.790 ;
        RECT -69.990 998.390 1611.380 998.730 ;
        RECT -43.965 997.010 1611.380 998.390 ;
        RECT -69.990 977.710 1611.380 997.010 ;
        RECT -43.965 976.610 1611.380 977.710 ;
        RECT -69.990 976.350 1611.380 976.610 ;
        RECT -43.965 975.250 1611.380 976.350 ;
        RECT -69.990 974.990 1611.380 975.250 ;
        RECT -43.965 973.210 1611.380 974.990 ;
        RECT -69.990 953.230 1611.380 973.210 ;
        RECT -43.965 951.850 1611.380 953.230 ;
        RECT -69.990 951.700 1611.380 951.850 ;
        RECT -43.965 951.450 1611.380 951.700 ;
        RECT -69.990 951.190 1611.380 951.450 ;
        RECT -43.965 950.090 1611.380 951.190 ;
        RECT -69.990 949.830 1611.380 950.090 ;
        RECT -43.965 948.730 1611.380 949.830 ;
        RECT -69.990 929.430 1611.380 948.730 ;
        RECT -43.965 928.050 1611.380 929.430 ;
        RECT -69.990 927.730 1611.380 928.050 ;
        RECT -43.965 927.650 1611.380 927.730 ;
        RECT -69.990 927.390 1611.380 927.650 ;
        RECT -43.965 926.290 1611.380 927.390 ;
        RECT -69.990 926.030 1611.380 926.290 ;
        RECT -43.965 924.930 1611.380 926.030 ;
        RECT -69.990 905.630 1611.380 924.930 ;
        RECT -43.965 904.530 1611.380 905.630 ;
        RECT -69.990 904.270 1611.380 904.530 ;
        RECT -43.965 902.490 1611.380 904.270 ;
        RECT -69.990 902.230 1611.380 902.490 ;
        RECT -43.965 901.130 1611.380 902.230 ;
        RECT -69.990 881.150 1611.380 901.130 ;
        RECT -43.965 879.370 1611.380 881.150 ;
        RECT -69.990 879.110 1611.380 879.370 ;
        RECT -43.965 877.330 1611.380 879.110 ;
        RECT -69.990 857.350 1611.380 877.330 ;
        RECT -43.965 856.250 1611.380 857.350 ;
        RECT -69.990 855.990 1611.380 856.250 ;
        RECT -43.965 854.210 1611.380 855.990 ;
        RECT -69.990 853.950 1611.380 854.210 ;
        RECT -43.965 852.850 1611.380 853.950 ;
        RECT -69.990 833.550 1611.380 852.850 ;
        RECT -43.965 832.450 1611.380 833.550 ;
        RECT -69.990 832.190 1611.380 832.450 ;
        RECT -43.965 830.410 1611.380 832.190 ;
        RECT -69.990 830.150 1611.380 830.410 ;
        RECT -43.965 829.050 1611.380 830.150 ;
        RECT -69.990 827.780 1611.380 829.050 ;
        RECT -69.990 825.980 1605.420 827.780 ;
        RECT -69.990 825.740 1611.380 825.980 ;
        RECT -69.990 823.940 1605.420 825.740 ;
        RECT -69.990 823.700 1611.380 823.940 ;
        RECT -69.990 821.900 1605.420 823.700 ;
        RECT -69.990 821.660 1611.380 821.900 ;
        RECT -69.990 819.860 1605.420 821.660 ;
        RECT -69.990 819.620 1611.380 819.860 ;
        RECT -69.990 817.820 1605.420 819.620 ;
        RECT -69.990 817.580 1611.380 817.820 ;
        RECT -69.990 815.780 1605.420 817.580 ;
        RECT -69.990 815.540 1611.380 815.780 ;
        RECT -69.990 813.740 1605.420 815.540 ;
        RECT -69.990 809.070 1611.380 813.740 ;
        RECT -43.965 807.290 1611.380 809.070 ;
        RECT -69.990 807.030 1611.380 807.290 ;
        RECT -43.965 805.250 1611.380 807.030 ;
        RECT -69.990 785.270 1611.380 805.250 ;
        RECT -43.965 784.170 1611.380 785.270 ;
        RECT -69.990 783.910 1611.380 784.170 ;
        RECT -43.965 782.130 1611.380 783.910 ;
        RECT -69.990 781.870 1611.380 782.130 ;
        RECT -43.965 780.770 1611.380 781.870 ;
        RECT -69.990 761.470 1611.380 780.770 ;
        RECT -43.965 760.370 1611.380 761.470 ;
        RECT -69.990 760.110 1611.380 760.370 ;
        RECT -43.965 758.330 1611.380 760.110 ;
        RECT -69.990 758.070 1611.380 758.330 ;
        RECT -43.965 756.970 1611.380 758.070 ;
        RECT -69.990 737.670 1611.380 756.970 ;
        RECT -43.965 736.570 1611.380 737.670 ;
        RECT -69.990 736.310 1611.380 736.570 ;
        RECT -43.965 734.530 1611.380 736.310 ;
        RECT -69.990 734.270 1611.380 734.530 ;
        RECT -43.965 733.170 1611.380 734.270 ;
        RECT -69.990 713.190 1611.380 733.170 ;
        RECT -43.965 711.410 1611.380 713.190 ;
        RECT -69.990 711.150 1611.380 711.410 ;
        RECT -43.965 710.050 1611.380 711.150 ;
        RECT -69.990 709.790 1611.380 710.050 ;
        RECT -43.965 708.690 1611.380 709.790 ;
        RECT -69.990 689.390 1611.380 708.690 ;
        RECT -43.965 688.290 1611.380 689.390 ;
        RECT -69.990 688.030 1611.380 688.290 ;
        RECT -43.965 686.250 1611.380 688.030 ;
        RECT -69.990 685.990 1611.380 686.250 ;
        RECT -43.965 684.890 1611.380 685.990 ;
        RECT -69.990 665.590 1611.380 684.890 ;
        RECT -43.965 664.490 1611.380 665.590 ;
        RECT -69.990 664.230 1611.380 664.490 ;
        RECT -43.965 662.450 1611.380 664.230 ;
        RECT -69.990 662.190 1611.380 662.450 ;
        RECT -43.965 661.090 1611.380 662.190 ;
        RECT -69.990 641.110 1611.380 661.090 ;
        RECT -43.965 639.330 1611.380 641.110 ;
        RECT -69.990 639.070 1611.380 639.330 ;
        RECT -43.965 637.290 1611.380 639.070 ;
        RECT -69.990 617.310 1611.380 637.290 ;
        RECT -43.965 616.210 1611.380 617.310 ;
        RECT -69.990 615.950 1611.380 616.210 ;
        RECT -43.965 614.170 1611.380 615.950 ;
        RECT -69.990 613.910 1611.380 614.170 ;
        RECT -43.965 612.810 1611.380 613.910 ;
        RECT -69.990 593.510 1611.380 612.810 ;
        RECT -43.965 592.410 1611.380 593.510 ;
        RECT -69.990 592.150 1611.380 592.410 ;
        RECT -43.965 591.050 1611.380 592.150 ;
        RECT -69.990 590.790 1611.380 591.050 ;
        RECT -43.965 590.730 1611.380 590.790 ;
        RECT -69.990 590.390 1611.380 590.730 ;
        RECT -43.965 589.010 1611.380 590.390 ;
        RECT -69.990 569.710 1611.380 589.010 ;
        RECT -43.965 568.610 1611.380 569.710 ;
        RECT -69.990 568.350 1611.380 568.610 ;
        RECT -43.965 567.250 1611.380 568.350 ;
        RECT -69.990 566.990 1611.380 567.250 ;
        RECT -43.965 565.210 1611.380 566.990 ;
        RECT -69.990 545.230 1611.380 565.210 ;
        RECT -43.965 543.300 1611.380 545.230 ;
        RECT -69.990 543.190 1611.380 543.300 ;
        RECT -43.965 542.090 1611.380 543.190 ;
        RECT -69.990 541.830 1611.380 542.090 ;
        RECT -43.965 540.730 1611.380 541.830 ;
        RECT -69.990 521.430 1611.380 540.730 ;
        RECT -43.965 518.290 1611.380 521.430 ;
        RECT -69.990 518.030 1611.380 518.290 ;
        RECT -43.965 516.930 1611.380 518.030 ;
        RECT -69.990 497.630 1611.380 516.930 ;
        RECT -43.965 496.530 1611.380 497.630 ;
        RECT -69.990 496.270 1611.380 496.530 ;
        RECT -43.965 494.490 1611.380 496.270 ;
        RECT -69.990 494.230 1611.380 494.490 ;
        RECT -43.965 493.130 1611.380 494.230 ;
        RECT -69.990 473.150 1611.380 493.130 ;
        RECT -43.965 471.370 1611.380 473.150 ;
        RECT -69.990 471.110 1611.380 471.370 ;
        RECT -43.965 469.330 1611.380 471.110 ;
        RECT -69.990 449.350 1611.380 469.330 ;
        RECT -43.965 448.250 1611.380 449.350 ;
        RECT -69.990 447.990 1611.380 448.250 ;
        RECT -43.965 446.210 1611.380 447.990 ;
        RECT -69.990 445.950 1611.380 446.210 ;
        RECT -43.965 444.850 1611.380 445.950 ;
        RECT -69.990 425.550 1611.380 444.850 ;
        RECT -43.965 424.450 1611.380 425.550 ;
        RECT -69.990 424.190 1611.380 424.450 ;
        RECT -43.965 422.410 1611.380 424.190 ;
        RECT -69.990 422.150 1611.380 422.410 ;
        RECT -43.965 421.050 1611.380 422.150 ;
        RECT -69.990 401.070 1611.380 421.050 ;
        RECT -43.965 399.290 1611.380 401.070 ;
        RECT -69.990 399.030 1611.380 399.290 ;
        RECT -43.965 397.250 1611.380 399.030 ;
        RECT -69.990 377.270 1611.380 397.250 ;
        RECT -43.965 376.170 1611.380 377.270 ;
        RECT -69.990 375.910 1611.380 376.170 ;
        RECT -43.965 374.130 1611.380 375.910 ;
        RECT -69.990 373.870 1611.380 374.130 ;
        RECT -43.965 372.770 1611.380 373.870 ;
        RECT -69.990 353.470 1611.380 372.770 ;
        RECT -43.965 352.370 1611.380 353.470 ;
        RECT -69.990 352.110 1611.380 352.370 ;
        RECT -43.965 350.330 1611.380 352.110 ;
        RECT -69.990 350.070 1611.380 350.330 ;
        RECT -43.965 348.970 1611.380 350.070 ;
        RECT -69.990 329.670 1611.380 348.970 ;
        RECT -43.965 328.570 1611.380 329.670 ;
        RECT -69.990 328.310 1611.380 328.570 ;
        RECT -43.965 326.530 1611.380 328.310 ;
        RECT -69.990 326.270 1611.380 326.530 ;
        RECT -43.965 325.170 1611.380 326.270 ;
        RECT -69.990 305.190 1611.380 325.170 ;
        RECT -43.965 303.410 1611.380 305.190 ;
        RECT -69.990 303.150 1611.380 303.410 ;
        RECT -43.965 302.050 1611.380 303.150 ;
        RECT -69.990 301.790 1611.380 302.050 ;
        RECT -43.965 300.690 1611.380 301.790 ;
        RECT -69.990 281.390 1611.380 300.690 ;
        RECT -43.965 280.290 1611.380 281.390 ;
        RECT -69.990 280.030 1611.380 280.290 ;
        RECT -43.965 278.250 1611.380 280.030 ;
        RECT -69.990 277.990 1611.380 278.250 ;
        RECT -43.965 276.890 1611.380 277.990 ;
        RECT -69.990 257.590 1611.380 276.890 ;
        RECT -43.965 256.490 1611.380 257.590 ;
        RECT -69.990 256.230 1611.380 256.490 ;
        RECT -43.965 254.450 1611.380 256.230 ;
        RECT -69.990 254.190 1611.380 254.450 ;
        RECT -43.965 253.090 1611.380 254.190 ;
        RECT -69.990 233.110 1611.380 253.090 ;
        RECT -43.965 231.330 1611.380 233.110 ;
        RECT -69.990 231.070 1611.380 231.330 ;
        RECT -43.965 229.290 1611.380 231.070 ;
        RECT -69.990 209.310 1611.380 229.290 ;
        RECT -43.965 208.210 1611.380 209.310 ;
        RECT -69.990 207.950 1611.380 208.210 ;
        RECT -43.965 206.170 1611.380 207.950 ;
        RECT -69.990 205.910 1611.380 206.170 ;
        RECT -43.965 204.810 1611.380 205.910 ;
        RECT -69.990 185.510 1611.380 204.810 ;
        RECT -43.965 184.410 1611.380 185.510 ;
        RECT -69.990 184.150 1611.380 184.410 ;
        RECT -43.965 181.010 1611.380 184.150 ;
        RECT -69.990 161.710 1611.380 181.010 ;
        RECT -43.965 160.610 1611.380 161.710 ;
        RECT -69.990 160.350 1611.380 160.610 ;
        RECT -43.965 159.250 1611.380 160.350 ;
        RECT -69.990 158.990 1611.380 159.250 ;
        RECT -43.965 157.210 1611.380 158.990 ;
        RECT -69.990 137.230 1611.380 157.210 ;
        RECT -43.965 135.300 1611.380 137.230 ;
        RECT -69.990 135.190 1611.380 135.300 ;
        RECT -43.965 134.090 1611.380 135.190 ;
        RECT -69.990 133.830 1611.380 134.090 ;
        RECT -43.965 132.730 1611.380 133.830 ;
        RECT -69.990 113.430 1611.380 132.730 ;
        RECT -43.965 110.290 1611.380 113.430 ;
        RECT -69.990 110.030 1611.380 110.290 ;
        RECT -43.965 108.930 1611.380 110.030 ;
        RECT -69.990 89.630 1611.380 108.930 ;
        RECT -43.965 88.530 1611.380 89.630 ;
        RECT -69.990 88.270 1611.380 88.530 ;
        RECT -43.965 86.490 1611.380 88.270 ;
        RECT -69.990 86.230 1611.380 86.490 ;
        RECT -43.965 85.130 1611.380 86.230 ;
        RECT -69.990 65.150 1611.380 85.130 ;
        RECT -43.965 63.370 1611.380 65.150 ;
        RECT -69.990 63.110 1611.380 63.370 ;
        RECT -43.965 61.330 1611.380 63.110 ;
        RECT -69.990 31.515 1611.380 61.330 ;
        RECT 9.335 29.355 1611.380 31.515 ;
        RECT -69.990 19.985 1611.380 29.355 ;
        RECT 9.335 17.825 1611.380 19.985 ;
        RECT -69.990 11.175 1611.380 17.825 ;
        RECT 9.335 8.985 1611.380 11.175 ;
        RECT -69.990 -19.600 1611.380 8.985 ;
      LAYER met4 ;
        RECT -20.000 52.450 1561.380 1670.345 ;
        RECT -20.000 49.990 368.395 52.450 ;
        RECT 380.985 49.990 1561.380 52.450 ;
        RECT -20.000 0.775 1561.380 49.990 ;
      LAYER met5 ;
        RECT 0.000 40.050 1541.380 1598.390 ;
  END
END pixel_4tile
END LIBRARY
